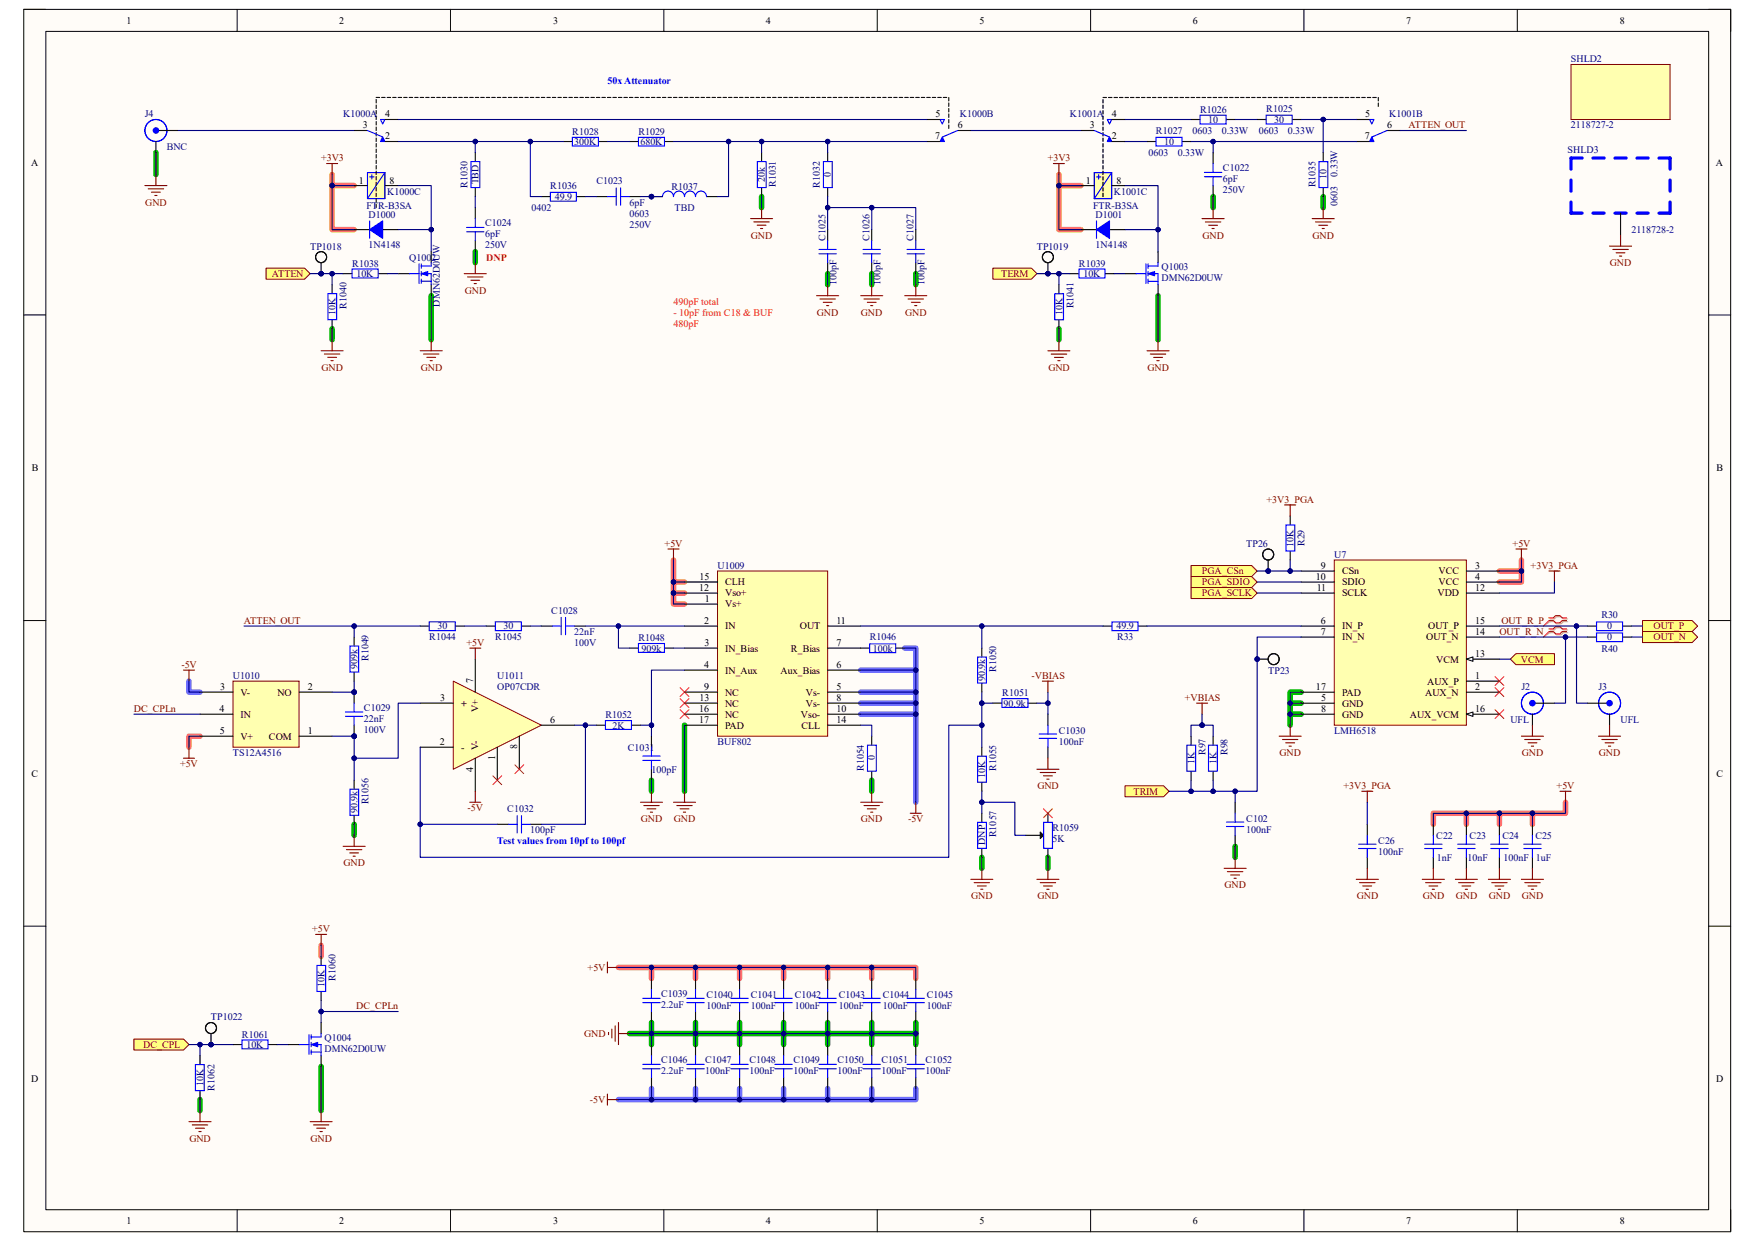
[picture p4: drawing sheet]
<svg xmlns="http://www.w3.org/2000/svg" width="297mm" height="210mm" viewBox="0 0 297 210" stroke-linecap="round" stroke-linejoin="round" font-family="sans-serif">
<defs><g id="words">
<g font-size="1.7">
<text x="21.4" y="4">1</text>
<text x="57.4" y="4">2</text>
<text x="93.6" y="4">3</text>
<text x="129.6" y="4">4</text>
<text x="165.8" y="4">5</text>
<text x="201.8" y="4">6</text>
<text x="238" y="4">7</text>
<text x="274.1" y="4">8</text>
<text x="61.4" y="21.7">3</text>
<text x="65.2" y="23.6">2</text>
<text x="65.2" y="19.9">4</text>
<text x="158.3" y="23.6">7</text>
<text x="158.3" y="19.9">5</text>
<text x="162.1" y="21.7">6</text>
<text x="184.4" y="21.7">3</text>
<text x="188.2" y="23.6">2</text>
<text x="188.2" y="19.9">4</text>
<text x="231" y="23.6">7</text>
<text x="231" y="19.9">5</text>
<text x="234.8" y="21.7">6</text>
<text x="5.3" y="28">A</text>
<text x="290.4" y="28">A</text>
<text x="60.7" y="31.1">1</text>
<text x="65.9" y="31.1">8</text>
<text x="183.8" y="31.1">1</text>
<text x="188.9" y="31.1">8</text>
<text x="5.4" y="79.8">B</text>
<text x="290.5" y="79.8">B</text>
<text x="118.3" y="100">12</text>
<text x="118.4" y="98.1">15</text>
<text x="119.3" y="101.9">1</text>
<text x="122.7" y="100.9">Vso+</text>
<text x="122.7" y="99.1">CLH</text>
<text x="222.7" y="98.1">10</text>
<text x="222.8" y="100">11</text>
<text x="223.5" y="96.3">9</text>
<text x="227.1" y="97.2">CSn</text>
<text x="227.1" y="99.1">SDIO</text>
<text x="227.1" y="100.9">SCLK</text>
<text x="243.3" y="100.9">VDD</text>
<text x="243.5" y="97.2">VCC</text>
<text x="243.5" y="99.1">VCC</text>
<text x="249.6" y="100">12</text>
<text x="249.6" y="96.3">3</text>
<text x="249.6" y="98.1">4</text>
<text x="119.2" y="105.6">2</text>
<text x="122.7" y="102.8">Vs+</text>
<text x="122.7" y="106.5">IN</text>
<text x="135.3" y="106.5">OUT</text>
<text x="141.6" y="105.6">11</text>
<text x="223.5" y="105.6">6</text>
<text x="223.5" y="107.4">7</text>
<text x="227.1" y="106.5">IN_P</text>
<text x="241.7" y="106.5">OUT_P</text>
<text x="249.6" y="107.4">14</text>
<text x="249.6" y="105.6">15</text>
<text x="119.2" y="113.1">4</text>
<text x="119.3" y="109.3">3</text>
<text x="122.7" y="110.3">IN_Bias</text>
<text x="133.9" y="110.3">R_Bias</text>
<text x="141.6" y="113.1">6</text>
<text x="141.6" y="109.3">7</text>
<text x="227.1" y="108.4">IN_N</text>
<text x="241.4" y="108.4">OUT_N</text>
<text x="243.1" y="112.1">VCM</text>
<text x="249.6" y="111.2">13</text>
<text x="37.3" y="116.8">3</text>
<text x="40.7" y="117.7">V-</text>
<text x="46.9" y="117.7">NO</text>
<text x="52.1" y="116.8">2</text>
<text x="74.5" y="118.7">3</text>
<text x="78" y="119.6">+</text>
<text x="80.1" y="115.7" transform="rotate(-90 80.1 115.7)">7</text>
<text x="118.4" y="118.7">13</text>
<text x="119.2" y="116.8">9</text>
<text x="122.7" y="114">IN_Aux</text>
<text x="122.7" y="117.7">NC</text>
<text x="122.7" y="119.6">NC</text>
<text x="132.1" y="114">Aux_Bias</text>
<text x="136.4" y="117.7">Vs-</text>
<text x="136.4" y="119.6">Vs-</text>
<text x="141.6" y="116.8">5</text>
<text x="141.6" y="118.7">8</text>
<text x="222.7" y="116.8">17</text>
<text x="223.6" y="118.7">5</text>
<text x="227.1" y="119.6">GND</text>
<text x="227.1" y="117.7">PAD</text>
<text x="241.2" y="117.7">AUX_N</text>
<text x="241.5" y="115.9">AUX_P</text>
<text x="249.6" y="114.9">1</text>
<text x="249.6" y="116.8">2</text>
<text x="37.2" y="120.5">4</text>
<text x="37.2" y="124.2">5</text>
<text x="40.7" y="125.2">V+</text>
<text x="40.7" y="121.5">IN</text>
<text x="45.5" y="125.2">COM</text>
<text x="52.1" y="124.2">1</text>
<text x="81" y="120.6" transform="rotate(-90 81 120.6)">V+</text>
<text x="93.1" y="122.4">6</text>
<text x="118.3" y="120.5">16</text>
<text x="118.3" y="122.4">17</text>
<text x="122.7" y="121.5">NC</text>
<text x="122.7" y="123.3">PAD</text>
<text x="135.6" y="121.5">Vso-</text>
<text x="135.6" y="123.3">CLL</text>
<text x="141.6" y="120.5">10</text>
<text x="141.6" y="122.4">14</text>
<text x="223.6" y="120.5">8</text>
<text x="227.1" y="121.5">GND</text>
<text x="238.6" y="121.5">AUX_VCM</text>
<text x="249.6" y="120.5">16</text>
<text x="5.3" y="131.4">C</text>
<text x="74.4" y="126.1">2</text>
<text x="78" y="127">-</text>
<text x="80.1" y="130.6" transform="rotate(-90 80.1 130.6)">4</text>
<text x="81" y="127" transform="rotate(-90 81 127)">V-</text>
<text x="83.8" y="128.6" transform="rotate(-90 83.8 128.6)">1</text>
<text x="87.5" y="126.8" transform="rotate(-90 87.5 126.8)">8</text>
<text x="290.5" y="131.4">C</text>
<text x="5.3" y="183.2">D</text>
<text x="290.4" y="183.2">D</text>
<text x="21.4" y="207.2">1</text>
<text x="57.4" y="207.2">2</text>
<text x="93.6" y="207.2">3</text>
<text x="129.6" y="207.2">4</text>
<text x="165.8" y="207.2">5</text>
<text x="201.8" y="207.2">6</text>
<text x="238" y="207.2">7</text>
<text x="274.1" y="207.2">8</text>
</g>
<g font-size="1.7" fill="#000080">
<text x="265.9" y="10.5">SHLD2</text>
<text x="24.5" y="19.9">J4</text>
<text x="58.1" y="19.9">K1000A</text>
<text x="96.9" y="22.9">R1028</text>
<text x="108" y="22.9">R1029</text>
<text x="162.4" y="19.9">K1000B</text>
<text x="181.1" y="19.9">K1001A</text>
<text x="195.6" y="22.6">R1027</text>
<text x="201.8" y="22.6">0603</text>
<text x="203.1" y="19.1">R1026</text>
<text x="204.5" y="20.8">10</text>
<text x="206.8" y="22.6">0.33W</text>
<text x="213" y="22.6">0603</text>
<text x="214.3" y="18.9">R1025</text>
<text x="215.6" y="20.8">30</text>
<text x="217.9" y="22.6">0.33W</text>
<text x="235.1" y="19.9">K1001B</text>
<text x="265.9" y="21.7">2118727-2</text>
<text x="28.2" y="25.4">BNC</text>
<text x="97.2" y="24.5">300K</text>
<text x="108.4" y="24.5">680K</text>
<text x="140.6" y="29.9" transform="rotate(-90 140.6 29.9)">0</text>
<text x="194.4" y="26.4">0603</text>
<text x="197" y="24.5">10</text>
<text x="199.3" y="26.4">0.33W</text>
<text x="207" y="29">C1022</text>
<text x="226.4" y="29.9" transform="rotate(-90 226.4 29.9)">0.33W</text>
<text x="265.3" y="25.8">SHLD3</text>
<text x="62" y="35.3">FTR-B3SA</text>
<text x="65.5" y="32.9">K1000C</text>
<text x="79.1" y="31.7" transform="rotate(-90 79.1 31.7)">R1030</text>
<text x="81" y="31.2" transform="rotate(-90 81 31.2)">TBD</text>
<text x="90" y="35.7">0402</text>
<text x="93.1" y="32">R1036</text>
<text x="93.9" y="33.9">49.9</text>
<text x="100.9" y="31.1">C1023</text>
<text x="106.5" y="34.8">6pF</text>
<text x="113.6" y="32.2">R1037</text>
<text x="114.2" y="35.7">TBD</text>
<text x="129.5" y="30.8" transform="rotate(-90 129.5 30.8)">20k</text>
<text x="131.3" y="31.7" transform="rotate(-90 131.3 31.7)">R1031</text>
<text x="138.8" y="31.7" transform="rotate(-90 138.8 31.7)">R1032</text>
<text x="185" y="35.3">FTR-B3SA</text>
<text x="188.5" y="32.9">K1001C</text>
<text x="207" y="32.7">250V</text>
<text x="207" y="30.9">6pF</text>
<text x="222.6" y="31.7" transform="rotate(-90 222.6 31.7)">R1035</text>
<text x="224.5" y="30.4" transform="rotate(-90 224.5 30.4)">10</text>
<text x="226.4" y="34.9" transform="rotate(-90 226.4 34.9)">0603</text>
<text x="62.4" y="36.9">D1000</text>
<text x="82.1" y="38.3">C1024</text>
<text x="82.1" y="40.2">6pF</text>
<text x="106.5" y="36.7">0603</text>
<text x="106.5" y="38.5">250V</text>
<text x="139.7" y="40.7" transform="rotate(-90 139.7 40.7)">C1025</text>
<text x="147.1" y="40.7" transform="rotate(-90 147.1 40.7)">C1026</text>
<text x="154.6" y="40.7" transform="rotate(-90 154.6 40.7)">C1027</text>
<text x="185.4" y="36.9">D1001</text>
<text x="276.1" y="39.5">2118728-2</text>
<text x="52.5" y="42.2">TP1018</text>
<text x="59.6" y="45.2">R1038</text>
<text x="60.3" y="46.9">10K</text>
<text x="62.4" y="42">1N4148</text>
<text x="69.3" y="44.1">Q1002</text>
<text x="82.1" y="42">250V</text>
<text x="175.5" y="42.2">TP1019</text>
<text x="182.6" y="45.2">R1039</text>
<text x="183.3" y="46.9">10K</text>
<text x="185.4" y="42">1N4148</text>
<text x="196.6" y="45.8">Q1003</text>
<text x="196.6" y="47.6">DMN62D0UW</text>
<text x="56.8" y="53.3" transform="rotate(-90 56.8 53.3)">10K</text>
<text x="58.6" y="52.2" transform="rotate(-90 58.6 52.2)">R1040</text>
<text x="74.5" y="51.9" transform="rotate(-90 74.5 51.9)">DMN62D0UW</text>
<text x="141.6" y="48.2" transform="rotate(-90 141.6 48.2)">100pF</text>
<text x="149" y="48.2" transform="rotate(-90 149 48.2)">100pF</text>
<text x="156.5" y="48.2" transform="rotate(-90 156.5 48.2)">100pF</text>
<text x="179.8" y="53.3" transform="rotate(-90 179.8 53.3)">10K</text>
<text x="181.6" y="52.2" transform="rotate(-90 181.6 52.2)">R1041</text>
<text x="210.9" y="92.5">TP26</text>
<text x="218.9" y="92.5" transform="rotate(-90 218.9 92.5)">10K</text>
<text x="220.8" y="92.4" transform="rotate(-90 220.8 92.4)">R29</text>
<text x="225.8" y="94.4">U7</text>
<text x="121.4" y="96.3">U1009</text>
<text x="74" y="106.5">30</text>
<text x="85.2" y="106.5">30</text>
<text x="93.3" y="103.9">C1028</text>
<text x="97.2" y="107.4">22nF</text>
<text x="188.9" y="106.5">49.9</text>
<text x="271" y="104.6">R30</text>
<text x="272" y="106.5">0</text>
<text x="60.5" y="113.2" transform="rotate(-90 60.5 113.2)">909k</text>
<text x="62.4" y="111.9" transform="rotate(-90 62.4 111.9)">R1049</text>
<text x="72.6" y="108.4">R1044</text>
<text x="83.8" y="108.4">R1045</text>
<text x="97.2" y="109.3">100V</text>
<text x="108" y="108.5">R1048</text>
<text x="108.5" y="110.3">909k</text>
<text x="147.2" y="108.4">R1046</text>
<text x="147.7" y="110.3">100k</text>
<text x="168.6" y="113.7" transform="rotate(-90 168.6 113.7)">R1050</text>
<text x="189.1" y="108.4">R33</text>
<text x="271" y="110.3">R40</text>
<text x="272" y="108.4">0</text>
<text x="39.4" y="114.9">U1010</text>
<text x="84.2" y="114.9">U1011</text>
<text x="84.2" y="116.8">OP07CDR</text>
<text x="166.7" y="115.3" transform="rotate(-90 166.7 115.3)">90.9k</text>
<text x="169.6" y="117.7">R1051</text>
<text x="169.8" y="119.6">90.9k</text>
<text x="214.6" y="114">TP23</text>
<text x="257.5" y="116.8">J2</text>
<text x="270.5" y="116.8">J3</text>
<text x="61.6" y="124">100V</text>
<text x="61.6" y="120.3">C1029</text>
<text x="61.6" y="122.2">22nF</text>
<text x="102.4" y="121.6">R1052</text>
<text x="103.6" y="123.3">2K</text>
<text x="179.2" y="124.2">C1030</text>
<text x="225.8" y="124.2">LMH6518</text>
<text x="255.6" y="122.4">UFL</text>
<text x="274.2" y="122.4">UFL</text>
<text x="39.4" y="128">TS12A4516</text>
<text x="106.3" y="127">C1031</text>
<text x="110.2" y="130.8">100pF</text>
<text x="121.4" y="126.1">BUF802</text>
<text x="146.2" y="130.5" transform="rotate(-90 146.2 130.5)">R1054</text>
<text x="148.1" y="128.7" transform="rotate(-90 148.1 128.7)">0</text>
<text x="166.7" y="131.6" transform="rotate(-90 166.7 131.6)">10K</text>
<text x="168.6" y="130.5" transform="rotate(-90 168.6 130.5)">R1055</text>
<text x="179.2" y="126.1">100nF</text>
<text x="202.1" y="129.3" transform="rotate(-90 202.1 129.3)">1K</text>
<text x="204" y="127.8" transform="rotate(-90 204 127.8)">R97</text>
<text x="205.9" y="129.3" transform="rotate(-90 205.9 129.3)">1K</text>
<text x="207.7" y="127.8" transform="rotate(-90 207.7 127.8)">R98</text>
<text x="60.5" y="137.7" transform="rotate(-90 60.5 137.7)">90.9k</text>
<text x="62.4" y="136.1" transform="rotate(-90 62.4 136.1)">R1056</text>
<text x="85.9" y="137.5">C1032</text>
<text x="89.7" y="141">100pF</text>
<text x="166.7" y="143" transform="rotate(-90 166.7 143)">DNP</text>
<text x="168.6" y="141.7" transform="rotate(-90 168.6 141.7)">R1057</text>
<text x="178.1" y="140.7">R1059</text>
<text x="178.1" y="142.5">5K</text>
<text x="210.9" y="139.1">C102</text>
<text x="210.9" y="141">100nF</text>
<text x="233.3" y="142.9">C26</text>
<text x="243.1" y="141.9">C22</text>
<text x="248.7" y="141.9">C23</text>
<text x="254.3" y="141.9">C24</text>
<text x="259.8" y="141.9">C25</text>
<text x="233.3" y="144.7">100nF</text>
<text x="243.2" y="145.7">1nF</text>
<text x="248.3" y="145.7">10nF</text>
<text x="254.4" y="145.7">100nF 1uF</text>
<text x="54.9" y="167" transform="rotate(-90 54.9 167)">10K</text>
<text x="56.8" y="165.9" transform="rotate(-90 56.8 165.9)">R1060</text>
<text x="35.7" y="172.7">TP1022</text>
<text x="111.9" y="168.8">C1039</text>
<text x="111.9" y="170.6">2.2uF</text>
<text x="119.5" y="169">C1040</text>
<text x="119.5" y="170.8">100nF</text>
<text x="127" y="169">C1041</text>
<text x="127" y="170.8">100nF</text>
<text x="134.5" y="169">C1042</text>
<text x="134.5" y="170.8">100nF</text>
<text x="141.9" y="169">C1043</text>
<text x="141.9" y="170.8">100nF</text>
<text x="149.4" y="169">C1044</text>
<text x="149.4" y="170.8">100nF</text>
<text x="156.8" y="169">C1045</text>
<text x="156.8" y="170.8">100nF</text>
<text x="40.9" y="175.6">R1061</text>
<text x="41.7" y="177.3">10K</text>
<text x="54.9" y="176.2">Q1004</text>
<text x="54.9" y="178.1">DMN62D0UW</text>
<text x="111.9" y="180">C1046</text>
<text x="119.3" y="180">C1047</text>
<text x="126.8" y="180">C1048</text>
<text x="134.3" y="180">C1049</text>
<text x="141.7" y="180">C1050</text>
<text x="149.2" y="180">C1051</text>
<text x="156.6" y="180">C1052</text>
<text x="34.4" y="183.8" transform="rotate(-90 34.4 183.8)">10K</text>
<text x="36.3" y="184.6" transform="rotate(-90 36.3 184.6)">R1062</text>
<text x="111.9" y="181.8">2.2uF</text>
<text x="119.3" y="181.8">100nF</text>
<text x="126.8" y="181.8">100nF</text>
<text x="134.3" y="181.8">100nF</text>
<text x="141.7" y="181.8">100nF</text>
<text x="149.2" y="181.8">100nF</text>
<text x="156.6" y="181.8">100nF</text>
</g>
<g font-size="1.7" fill="#00f">
<text x="102.8" y="14.3">50x Attenuator</text>
<text x="84.2" y="142.9">Test values from 10pf to 100pf</text>
</g>
<g font-size="1.7" fill="#800000">
<text x="238.4" y="21.7">ATTEN_OUT</text>
<text x="54.4" y="27.3">+3V3</text>
<text x="177.3" y="27.3">+3V3</text>
<text x="24.6" y="34.8">GND</text>
<text x="127.1" y="40.4">GND</text>
<text x="203.5" y="40.4">GND</text>
<text x="222.1" y="40.4">GND</text>
<text x="46" y="46.9">ATTEN</text>
<text x="169.4" y="46.9">TERM</text>
<text x="272.5" y="45">GND</text>
<text x="78.7" y="49.7">GND</text>
<text x="138.3" y="53.4">GND</text>
<text x="145.7" y="53.4">GND</text>
<text x="153.2" y="53.4">GND</text>
<text x="54.4" y="62.7">GND</text>
<text x="71.2" y="62.7">GND</text>
<text x="177.4" y="62.7">GND</text>
<text x="194.2" y="62.7">GND</text>
<text x="214.3" y="85.1">+3V3_PGA</text>
<text x="112.5" y="92.5">+5V</text>
<text x="256" y="92.5">+5V</text>
<text x="203.4" y="97.2">PGA_CSn</text>
<text x="203.4" y="100.9">PGA_SCLK</text>
<text x="203.4" y="99.1">PGA_SDIO</text>
<text x="259" y="96.3">+3V3_PGA</text>
<text x="41.3" y="105.6">ATTEN_OUT</text>
<text x="253.7" y="107.4">OUT_R_N</text>
<text x="254.1" y="105.6">OUT_R_P</text>
<text x="279.8" y="106.5">OUT_P</text>
<text x="30.7" y="113.1">-5V</text>
<text x="79" y="109.3">+5V</text>
<text x="257.4" y="112.1">VCM</text>
<text x="279.8" y="108.4">OUT_N</text>
<text x="174.6" y="114.9">-VBIAS</text>
<text x="200.5" y="118.7">+VBIAS</text>
<text x="22.6" y="120.5">DC_CPLn</text>
<text x="30.5" y="129.8">+5V</text>
<text x="216.5" y="128">GND</text>
<text x="257.6" y="128">GND</text>
<text x="270.6" y="128">GND</text>
<text x="79.1" y="137.3">-5V</text>
<text x="175.6" y="133.6">GND</text>
<text x="191.8" y="134.5">TRIM</text>
<text x="227.4" y="133.6">+3V3_PGA</text>
<text x="263.4" y="133.6">+5V</text>
<text x="108.5" y="139.1">GND</text>
<text x="114" y="139.1">GND</text>
<text x="145.7" y="139.1">GND</text>
<text x="153.7" y="139.1">-5V</text>
<text x="58.1" y="146.6">GND</text>
<text x="164.4" y="152.2">GND</text>
<text x="175.6" y="152.2">GND</text>
<text x="207.2" y="150.3">GND</text>
<text x="229.6" y="152.2">GND</text>
<text x="240.8" y="152.2">GND</text>
<text x="246.4" y="152.2">GND</text>
<text x="252" y="152.2">GND</text>
<text x="257.6" y="152.2">GND</text>
<text x="52.8" y="157.8">+5V</text>
<text x="99.4" y="164.3">+5V</text>
<text x="60.3" y="170.8">DC_CPLn</text>
<text x="24.2" y="177.3">DC_CPL</text>
<text x="98.8" y="175.5">GND</text>
<text x="99.8" y="186.6">-5V</text>
<text x="32" y="193.2">GND</text>
<text x="52.5" y="193.2">GND</text>
</g>
<g font-size="1.7" fill="#f00">
<text x="82.3" y="44.1">DNP</text>
<text x="114" y="51.6">490pF total</text>
<text x="114" y="53.4">- 10pF from C18 &amp; BUF</text>
<text x="114" y="55.3">480pF</text>
</g>
</g></defs>
<path d="M4 1.6h288.9v206.8h-288.9z" fill-rule="evenodd" fill="#fffcf8"/>
<path d="M4 1.6h288.9v206.8h-288.9z" fill="none" stroke="#000" stroke-width=".17"/>
<path d="M7.8 5.3h281.4v199.4h-281.4z" fill-rule="evenodd" fill="#fffcf8"/>
<g fill="none" stroke="#000" stroke-width=".17">
<path d="M4 1.6h3.7M7.8 5.3h281.4v199.4h-281.4zM40.1 1.6v3.7M76.2 1.6v3.7M112.3 1.6v3.7M148.5 1.6v3.7M184.6 1.6v3.7M220.7 1.6v3.7M256.8 1.6v3.7M289.2 1.6h3.7v3.7M4 53.3h3.7M289.2 53.3h3.7"/>
<path d="M4 105h3.8M289.2 105h3.7M4 156.7h3.8M289.2 156.7h3.7M40.1 204.7v3.7M76.2 204.7v3.7M112.4 204.7v3.7M148.5 204.7v3.7M184.6 204.7v3.7M220.7 204.7v3.7M256.8 204.7v3.7M292.9 204.7v3.7"/>
</g>
<g fill="none" stroke="#00be00" stroke-width=".93">
<path d="M26.4 25.8v3.7M128.9 33.3v1.8M205.3 33.3v1.8M223.9 33.3v1.8M56.2 55.6v1.9M73 50v7.5M80.4 42.6v1.8M140.1 46.3v1.9M147.5 46.3v1.9M155 46.3v1.9M179.2 55.6v1.9M196 50v7.5"/>
<path d="M218.3 119h1.9M220.2 117.1h-1.9v3.8h1.9M59.9 139.5v1.9M110.3 132v1.9M115.8 122.7v11.2M147.5 132v1.9M218.3 120.9v1.8M166.2 145.1v1.8M177.3 145.1v1.8M209 143.2v1.9M110.3 173v3.8M117.7 173v3.8"/>
<path d="M125.2 173v3.8M132.6 173v3.8M140.1 173v3.8M147.5 173v3.8M155 173v1.9h-48.5M155 174.9v1.9M33.8 186.1v1.8M54.3 180.5v7.4"/>
</g>
<g fill="none" stroke="#ff6e6e" stroke-width=".93">
<path d="M114 94.8v7.4h1.8M114 98.5h1.8M253.8 96.6h3.7M257.5 94.8v3.7h-3.7M114 100.4h1.8M33.8 124.6h-1.8v1.8M248.2 137.6h-5.6v1.9M253.8 137.6h-5.6v1.9M259.3 137.6v1.9M264.9 135.8v1.8h-11.1v1.9M54.3 160v1.9M104.7 163.7h13v1.9"/>
<path d="M110.3 163.7v1.9M117.7 163.7h29.8v1.9M125.2 163.7v1.9M132.6 163.7v1.9M140.1 163.7v1.9M147.5 163.7h7.5v1.9"/>
</g>
<path d="M56.2 31.4v7.5h3.7M56.2 29.5v1.9h3.7M179.2 31.4v7.5h3.7M179.2 29.5v1.9h3.7" fill="none" stroke="#f90" stroke-width=".93"/>
<g fill="none" stroke="#6e6eff" stroke-width=".93">
<path d="M32 115.3v1.8h1.8M145.7 113.4h9.3v3.7h-9.3M145.7 119h9.3v1.9h-9.3M153.1 109.7h1.9v3.7M155 117.1v1.9M155 120.9v14.9M110.3 184.2v1.9M117.7 184.2v1.9M125.2 184.2v1.9M132.6 184.2v1.9M140.1 184.2v1.9M147.5 184.2v1.9h-42.8"/>
<path d="M155 184.2v1.9h-7.5"/>
</g>
<path d="M265.9 30.5v1.8M265.9 34.2v1.9h1.8M267.7 26.7h-1.8v1.9M269.6 36.1h1.9M269.6 26.7h1.9M273.3 36.1h1.9M273.3 26.7h1.9M277.1 36.1h1.8M277.1 26.7h1.8M280.8 26.7h1.8v1.9M282.6 34.2v1.9h-1.8M282.6 30.5v1.8" fill="none" stroke="#00f" stroke-width=".56"/>
<path d="M274.3 36.1v3.7" fill="none" stroke="#000" stroke-width=".19"/>
<path d="M274.3 39.8v1.9M272.4 41.7h3.7M273 42.2h2.6M273.5 42.8h1.5M274.1 43.3h.3" fill="none" stroke="#800000" stroke-width=".19"/>
<path d="M265.9 10.9h16.7v9.3h-16.7z" fill-rule="evenodd" fill="#ffffb0"/>
<path d="M265.9 10.9h16.7v9.3h-16.7z" fill="none" stroke="#800000" stroke-width=".17"/>
<path d="M24.5 31.4h3.7M25.1 32h2.6M25.6 32.5h1.5M26.2 33.1h.4M26.4 29.5v1.9" fill="none" stroke="#800000" stroke-width=".19"/>
<circle cx="26.4" cy="22.1" r="1.86" fill="none" stroke="#00f" stroke-width=".19"/>
<path d="M26.4 22.1h3.7M26.4 23.9v1.9" fill="none" stroke="#000" stroke-width=".19"/>
<circle cx="26.4" cy="22.1" r=".47" fill="#00f"/>
<circle cx="26.4" cy="22.1" r=".47" fill="none" stroke="#00f" stroke-width=".17"/>
<path d="M186.7 105.9h1.4M192.6 105.9h1.5" fill="none" stroke="#000" stroke-width=".19"/>
<path d="M188.2 105.2h4.4v1.5h-4.4z" fill="none" stroke="#00f" stroke-width=".19"/>
<path d="M225.8 94.8h22.4v27.9h-22.4z" fill-rule="evenodd" fill="#ffffb0"/>
<path d="M225.8 94.8h22.4v27.9h-22.4z" fill="none" stroke="#800000" stroke-width=".17"/>
<path d="M220.2 96.6h5.6M220.2 98.5h5.6M220.2 100.4h5.6M248.2 100.4h5.6M248.2 111.5h5.6" fill="none" stroke="#000" stroke-width=".19"/>
<path d="M248.2 111.5l1.1-.3v.7z" fill="#f8fcff"/>
<path d="M248.2 111.5l1.1-.3v.7z" fill="none" stroke="#000" stroke-width=".17"/>
<path d="M248.2 107.8h5.6M248.2 105.9h5.6M248.2 115.3h5.6M248.2 117.1h5.6M248.2 120.9h5.6" fill="none" stroke="#000" stroke-width=".19"/>
<path d="M248.2 120.9l1.1-.4v.7z" fill="#f8fcff"/>
<path d="M248.2 120.9l1.1-.4v.7z" fill="none" stroke="#000" stroke-width=".17"/>
<path d="M248.2 96.6h5.6M248.2 98.5h5.6M220.2 119h5.6M220.2 117.1h5.6M220.2 105.9h5.6M220.2 107.8h5.6M220.2 120.9h5.6" fill="none" stroke="#000" stroke-width=".19"/>
<path d="M201.6 95.7h10.2l1 .9-1 1h-10.2z" fill-rule="evenodd" fill="#ffff80"/>
<path d="M201.6 95.7h10.2l1 .9-1 1h-10.2z" fill="none" stroke="#800000" stroke-width=".17"/>
<path d="M218.3 87.3v1.5M218.3 93.3v1.5" fill="none" stroke="#000" stroke-width=".19"/>
<path d="M217.6 88.8h1.5v4.4h-1.5z" fill="none" stroke="#00f" stroke-width=".19"/>
<path d="M201.6 99.4h10.2l1 1-1 .9h-10.2z" fill-rule="evenodd" fill="#ffff80"/>
<path d="M201.6 99.4h10.2l1 1-1 .9h-10.2z" fill="none" stroke="#800000" stroke-width=".17"/>
<path d="M201.6 97.6h10.2l1 .9-1 .9h-10.2z" fill-rule="evenodd" fill="#ffff80"/>
<path d="M201.6 97.6h10.2l1 .9-1 .9h-10.2z" fill="none" stroke="#800000" stroke-width=".17"/>
<path d="M216.5 124.6h3.7M217 125.1h2.6M217.6 125.7h1.5M218.2 126.3h.3M218.3 122.7v1.9" fill="none" stroke="#800000" stroke-width=".19"/>
<path d="M255.6 111.5l1-.9h6.5v1.9h-6.5z" fill-rule="evenodd" fill="#ffff80"/>
<path d="M255.6 111.5l1-.9h6.5v1.9h-6.5z" fill="none" stroke="#800000" stroke-width=".17"/>
<path d="M253 114.5l1.5 1.5M253 116.4l1.5 1.5M254.5 114.5l-1.5 1.5M254.5 116.4l-1.5 1.5M253 120.1l1.5 1.5M254.5 120.1l-1.5 1.5" fill="none" stroke="#f00" stroke-width=".17"/>
<path d="M278 105h8.4l.9 .9-.9 1h-8.4z" fill-rule="evenodd" fill="#ffff80"/>
<path d="M278 105h8.4l.9 .9-.9 1h-8.4z" fill="none" stroke="#800000" stroke-width=".17"/>
<path d="M278 106.9h8.4l.9 .9-.9 .9h-8.4z" fill-rule="evenodd" fill="#ffff80"/>
<path d="M278 106.9h8.4l.9 .9-.9 .9h-8.4z" fill="none" stroke="#800000" stroke-width=".17"/>
<path d="M259.3 119h3.8M268.7 105.9h1.4M268.7 107.8h1.4M274.6 105.9h1.5M274.6 107.8h1.5M259.3 120.9v1.8" fill="none" stroke="#000" stroke-width=".19"/>
<g fill="none" stroke="#00f" stroke-width=".19">
<path d="M270.2 105.2h4.4v1.5h-4.4zM270.2 107.1h4.4v1.5h-4.4z"/>
<circle cx="259.3" cy="119" r="1.86"/>
</g>
<circle cx="259.3" cy="119" r=".47" fill="#00f"/>
<circle cx="259.3" cy="119" r=".47" fill="none" stroke="#00f" stroke-width=".17"/>
<path d="M257.5 124.6h3.7M258 125.1h2.7M258.6 125.7h1.5M259.2 126.3h.3M259.3 122.7v1.9" fill="none" stroke="#800000" stroke-width=".19"/>
<circle cx="272.4" cy="119" r="1.86" fill="none" stroke="#00f" stroke-width=".19"/>
<path d="M268.7 119h3.7M272.4 120.9v1.8" fill="none" stroke="#000" stroke-width=".19"/>
<circle cx="272.4" cy="119" r=".47" fill="#00f"/>
<circle cx="272.4" cy="119" r=".47" fill="none" stroke="#00f" stroke-width=".17"/>
<path d="M270.5 124.6h3.8M271.1 125.1h2.6M271.6 125.7h1.5M272.2 126.3h.4M272.4 122.7v1.9" fill="none" stroke="#800000" stroke-width=".19"/>
<path d="M262.3 104.7h.8l.4-.3h.7l.4 .3h.7M262.3 105.2h.8l.4 .4h.7l.4-.4h.7" fill="none" stroke="#d0a19e" stroke-width=".19"/>
<path d="M262.3 105.2l-1.1 .7" fill="none" stroke="#d0a19e" stroke-width=".17"/>
<path d="M262.1 104.6h.8l.4-.4h.7l.4 .4h.7M262.1 105h.8l.4 .4h.7l.4-.4h.7" fill="none" stroke="#f00" stroke-width=".19"/>
<path d="M262.1 105l-.9 .9" fill="none" stroke="#f00" stroke-width=".17"/>
<circle cx="214.6" cy="96.6" r=".37" fill="#000080"/>
<circle cx="214.6" cy="96.6" r=".37" fill="none" stroke="#000080" stroke-width=".17"/>
<path d="M214.6 94.8v1.8" fill="none" stroke="#000" stroke-width=".19"/>
<circle cx="214.6" cy="96.6" r=".37" fill="#000080"/>
<circle cx="214.6" cy="96.6" r=".37" fill="none" stroke="#000080" stroke-width=".17"/>
<g fill="none" stroke="#000" stroke-width=".19">
<path d="M201.6 124.6v1.5M201.6 130.6v1.4M205.3 124.6v1.5M205.3 130.6v1.4M231.4 139.5v1.9M242.6 139.5v1.9M248.2 139.5v1.9M253.8 139.5v1.9M259.3 139.5v1.9M231.4 145.1v1.8M242.6 145.1v1.8M248.2 145.1v1.8"/>
<path d="M253.8 145.1v1.8M259.3 145.1v1.8"/>
<circle cx="214.6" cy="93.8" r=".93"/>
</g>
<g fill="none" stroke="#00f" stroke-width=".19">
<path d="M200.9 126.1h1.5v4.4h-1.5zM204.5 126.1h1.5v4.4h-1.5zM229.9 143.6h3M229.9 142.9h3M231.4 141.4v1.5M231.4 143.6v1.5M241.1 143.6h2.9M241.1 142.9h2.9M242.6 141.4v1.5M242.6 143.6v1.5M246.7 143.6h2.9M246.7 142.9h2.9"/>
<path d="M248.2 141.4v1.5M248.2 143.6v1.5M252.3 143.6h2.9M252.3 142.9h2.9M253.8 141.4v1.5M253.8 143.6v1.5M257.9 143.6h2.9M257.9 142.9h2.9M259.3 141.4v1.5M259.3 143.6v1.5"/>
</g>
<g fill="none" stroke="#800000" stroke-width=".19">
<path d="M256.6 92.9h1.8M257.5 92.9v1.9M264 133.9h1.9M264.9 133.9v1.9M229.5 148.8h3.8M230.1 149.4h2.6M230.6 149.9h1.5M231.2 150.5h.4M231.4 146.9v1.9M240.7 148.8h3.7M241.3 149.4h2.6M241.8 149.9h1.5"/>
<path d="M242.4 150.5h.4M242.6 146.9v1.9M246.3 148.8h3.7M246.9 149.4h2.6M247.4 149.9h1.5M248 150.5h.3M248.2 146.9v1.9M251.9 148.8h3.7M252.5 149.4h2.6M253 149.9h1.5M253.6 150.5h.3M253.8 146.9v1.9"/>
<path d="M257.5 148.8h3.7M258 149.4h2.7M258.6 149.9h1.5M259.2 150.5h.3M259.3 146.9v1.9"/>
</g>
<path d="M262.3 106.6h.8l.4-.4h.7l.4 .4h.7M262.3 107.1h.8l.4 .3h.7l.4-.3h.7" fill="none" stroke="#d0a19e" stroke-width=".19"/>
<path d="M262.3 107.1l-1.1 .7" fill="none" stroke="#d0a19e" stroke-width=".17"/>
<path d="M262.1 106.4h.8l.4-.4h.7l.4 .4h.7M262.1 106.9h.8l.4 .4h.7l.4-.4h.7" fill="none" stroke="#f00" stroke-width=".19"/>
<path d="M262.1 106.9l-.9 .9" fill="none" stroke="#f00" stroke-width=".17"/>
<path d="M190.4 133h6.5l.9 .9-.9 .9h-6.5z" fill-rule="evenodd" fill="#ffff80"/>
<path d="M190.4 133h6.5l.9 .9-.9 .9h-6.5z" fill="none" stroke="#800000" stroke-width=".17"/>
<path d="M202.5 119h1.9M203.4 119v1.9" fill="none" stroke="#800000" stroke-width=".19"/>
<circle cx="212.8" cy="111.5" r=".37" fill="#000080"/>
<circle cx="212.8" cy="111.5" r=".37" fill="none" stroke="#000080" stroke-width=".17"/>
<path d="M212.8 111.5h1.8" fill="none" stroke="#000" stroke-width=".19"/>
<circle cx="212.8" cy="111.5" r=".37" fill="#000080"/>
<circle cx="212.8" cy="111.5" r=".37" fill="none" stroke="#000080" stroke-width=".17"/>
<g fill="none" stroke="#000" stroke-width=".19">
<path d="M209 135.8v1.8M209 141.4v1.8"/>
<circle cx="215.6" cy="111.5" r=".93"/>
</g>
<path d="M207.6 139.1h2.9M207.6 139.9h2.9M209 137.6v1.5M209 139.9v1.5" fill="none" stroke="#00f" stroke-width=".19"/>
<path d="M217.4 85.4h1.9M218.3 85.4v1.9M262.1 96.6h1.9M263.1 96.6v1.9M230.5 133.9h1.8M231.4 133.9v1.9M207.2 146.9h3.7M207.7 147.5h2.6M208.3 148.1h1.5M208.8 148.6h.4M209 145.1v1.8" fill="none" stroke="#800000" stroke-width=".19"/>
<path d="M62.2 29.2h2.9v4.4h-2.9z" fill-rule="evenodd" fill="#ffffb0"/>
<path d="M62.2 29.2h2.9v4.4h-2.9z" fill="none" stroke="#800000" stroke-width=".17"/>
<path d="M62.6 29.9h.7M62.9 29.6v.7M65.1 29.2l-2.9 4.4M65.1 29.2h-2.9v4.4M65.1 29.2v4.4h-2.9" fill="none" stroke="#00f" stroke-width=".19"/>
<path d="M59.9 31.4h2.2M59.9 38.9h2.8M64.6 38.9h2.8M65.2 31.4h2.2" fill="none" stroke="#000" stroke-width=".19"/>
<path d="M55.3 27.7h1.8M56.2 27.7v1.8" fill="none" stroke="#800000" stroke-width=".19"/>
<path d="M62.6 38.9l2.2-1.5v2.9z" fill="#00f"/>
<path d="M62.6 38.9l2.2-1.5v2.9zM62.6 37.4v2.9M69.3 46.3h1.6M70.9 44.7v3.3M71.3 45h1.7M71.3 46.3h1.7v1.9M71.3 47.6h1.7M71.3 44.7v.7M71.3 45.9v.8M71.3 47.2v.8" fill="none" stroke="#00f" stroke-width=".19"/>
<path d="M67.4 46.3h1.9M73 42.6v1.8M73 48.2v1.8" fill="none" stroke="#000" stroke-width=".19"/>
<path d="M71.3 46.3l1.1-.4v.8z" fill="#00f"/>
<path d="M71.3 46.3l1.1-.4v.8z" fill="none" stroke="#00f" stroke-width=".17"/>
<path d="M55.5 49.7h1.5v4.4h-1.5zM73 44.4v.6" fill="none" stroke="#00f" stroke-width=".19"/>
<path d="M54.3 59.4h3.8M54.9 59.9h2.6M56.2 57.5v1.9M71.1 59.4h3.7M71.7 59.9h2.6M73 57.5v1.9M55.5 60.5h1.5M56 61h.4M72.2 60.5h1.5M72.8 61h.4" fill="none" stroke="#800000" stroke-width=".19"/>
<path d="M56.2 48.2v1.4M56.2 54.2v1.4" fill="none" stroke="#000" stroke-width=".19"/>
<path d="M45 45.4h6.5l1 .9-1 .9h-6.5z" fill-rule="evenodd" fill="#ffff80"/>
<path d="M45 45.4h6.5l1 .9-1 .9h-6.5z" fill="none" stroke="#800000" stroke-width=".17"/>
<g fill="none" stroke="#000" stroke-width=".19">
<path d="M63.7 16.8v.6M63.7 17.8v.6M63.7 18.7v.6M63.7 19.6v.6M63.7 16.5h.5M64.6 16.5h.6M65.5 16.5h.6M66.5 16.5h.5M67.4 16.5h.6M68.3 16.5h.6M69.3 16.5h.5M70.2 16.5h.6"/>
<path d="M71.1 16.5h.6M72 16.5h.6M73 16.5h.6M73.9 16.5h.6M74.8 16.5h.6M75.8 16.5h.6M76.7 16.5h.6M77.6 16.5h.6M78.6 16.5h.6M79.5 16.5h.6M80.4 16.5h.6M81.4 16.5h.5"/>
<path d="M82.3 16.5h.6M83.2 16.5h.6M84.2 16.5h.5M85.1 16.5h.6M86 16.5h.6M87 16.5h.5M87.9 16.5h.6M88.8 16.5h.6M89.8 16.5h.5M90.7 16.5h.6M91.6 16.5h.6M92.5 16.5h.6"/>
<path d="M93.5 16.5h.6M94.4 16.5h.6M95.3 16.5h.6M96.3 16.5h.6M97.2 16.5h.6M98.1 16.5h.6M99.1 16.5h.6M100 16.5h.6M100.9 16.5h.6M101.9 16.5h.5M102.8 16.5h.6M103.7 16.5h.6"/>
<path d="M104.7 16.5h.5M105.6 16.5h.6M106.5 16.5h.6M107.5 16.5h.5M108.4 16.5h.6M109.3 16.5h.6M110.3 16.5h.5M111.2 16.5h.6M112.1 16.5h.6M113 16.5h.6M114 16.5h.6M114.9 16.5h.6"/>
<path d="M115.8 16.5h.6M116.8 16.5h.6M117.7 16.5h.6M118.6 16.5h.6M119.6 16.5h.6M120.5 16.5h.6M121.4 16.5h.6M122.4 16.5h.5M123.3 16.5h.6M124.2 16.5h.6M125.2 16.5h.5M126.1 16.5h.6"/>
<path d="M127 16.5h.6M128 16.5h.5M128.9 16.5h.6M129.8 16.5h.6M130.8 16.5h.5M131.7 16.5h.6M132.6 16.5h.6M133.5 16.5h.6M134.5 16.5h.6M135.4 16.5h.6M136.3 16.5h.6M137.3 16.5h.6"/>
<path d="M138.2 16.5h.6M139.1 16.5h.6M140.1 16.5h.6M141 16.5h.6M141.9 16.5h.6M142.9 16.5h.5M143.8 16.5h.6M144.7 16.5h.6M145.7 16.5h.5M146.6 16.5h.6M147.5 16.5h.6M148.5 16.5h.5"/>
<path d="M149.4 16.5h.6M150.3 16.5h.6M151.3 16.5h.5M152.2 16.5h.6M153.1 16.5h.6M154 16.5h.6M155 16.5h.6M155.9 16.5h.6M156.8 16.5h.6M157.8 16.5h.6M158.7 16.5h.6M159.6 16.5h.6"/>
<path d="M160.6 16.5v.6M160.6 17.4v.6M160.6 18.4v.5M160.6 19.3v.6M59.9 22.1h2.2M63.7 20.6v.6M63.7 21.5v.6M63.7 22.4v.6M63.7 23.4v.5M63.7 24.3v.6M63.7 25.2v.6M63.7 26.2v.5"/>
<path d="M63.7 27.1v.6M63.7 28v.6M63.7 29v.5M63.7 29.9v.6M63.7 30.8v.6M63.7 31.8v.5M63.7 32.7v.6M63.7 33.6v.6M63.7 34.5v.6M95.3 24h1.5M100.9 33.3h1.9M101.3 24h1.5"/>
<path d="M106.5 24h1.5M106.5 33.3h1.9M112.5 24h1.5M128.9 25.8v1.5M128.9 31.8v1.5M140.1 38.9v1.8M147.5 38.9v1.8M160.6 20.2v.6M160.6 21.2v.5M140.1 44.4v1.9M147.5 44.4v1.9"/>
</g>
<g fill="none" stroke="#00f" stroke-width=".19">
<path d="M62.2 22.1l2.6 1.1M96.9 23.2h4.4v1.5h-4.4zM102.8 33.3h1.5M104.3 31.8v2.9M105 33.3h1.5M105 31.8v2.9M108.1 23.2h4.4v1.5h-4.4zM128.2 27.3h1.5v4.4h-1.5zM138.6 43h2.9M138.6 42.2h2.9M140.1 40.7v1.5M140.1 43v1.4"/>
<path d="M146.1 43h2.9M146.1 42.2h2.9M147.5 40.7v1.5M147.5 43v1.4"/>
</g>
<path d="M127 37h3.8M127.6 37.6h2.6M128.1 38.1h1.5M128.7 38.7h.4M128.9 35.1v1.9M138.2 50h3.7M138.8 50.6h2.6M139.3 51.2h1.5M139.9 51.7h.4M140.1 48.2v1.8" fill="none" stroke="#800000" stroke-width=".19"/>
<path d="M64.8 23.2l.3 .7h-.7z" fill="#00f"/>
<path d="M64.4 20.2h.7l-.3 .8zM64.8 23.2l.3 .7h-.7zM159.1 20.2h.7l-.3 .8zM162.1 22.1l-2.6 1.1" fill="none" stroke="#00f" stroke-width=".19"/>
<path d="M65.2 23.9h2.2M65.2 20.2h2.2M162.1 22.1h2.2" fill="none" stroke="#000" stroke-width=".19"/>
<path d="M159.5 23.2l.3 .8h-.7z" fill="#00f"/>
<path d="M159.5 23.2l.3 .8h-.7zM59.6 45.5h4.4v1.5h-4.4z" fill="none" stroke="#00f" stroke-width=".19"/>
<path d="M156.8 20.2h2.2M156.8 24h2.2M58.1 46.3h1.4M64.1 46.3h1.4" fill="none" stroke="#000" stroke-width=".19"/>
<circle cx="54.3" cy="46.3" r=".37" fill="#000080"/>
<circle cx="54.3" cy="46.3" r=".37" fill="none" stroke="#000080" stroke-width=".17"/>
<path d="M54.3 44.4v1.9" fill="none" stroke="#000" stroke-width=".19"/>
<circle cx="54.3" cy="46.3" r=".37" fill="#000080"/>
<circle cx="54.3" cy="46.3" r=".37" fill="none" stroke="#000080" stroke-width=".17"/>
<circle cx="54.3" cy="43.5" r=".93" fill="none" stroke="#000" stroke-width=".19"/>
<path d="M168 45.4h6.6l.9 .9-.9 .9h-6.6z" fill-rule="evenodd" fill="#ffff80"/>
<path d="M168 45.4h6.6l.9 .9-.9 .9h-6.6z" fill="none" stroke="#800000" stroke-width=".17"/>
<path d="M203.4 37h3.8M204 37.6h2.6M204.6 38.1h1.4M205.1 38.7h.4M205.3 35.1v1.9" fill="none" stroke="#800000" stroke-width=".19"/>
<path d="M205.3 25.8v1.9M205.3 31.4v1.9" fill="none" stroke="#000" stroke-width=".19"/>
<path d="M203.8 29.2h3M203.8 29.9h3M205.3 27.7v1.5M205.3 29.9v1.5" fill="none" stroke="#00f" stroke-width=".19"/>
<path d="M185.2 29.2h2.9v4.4h-2.9z" fill-rule="evenodd" fill="#ffffb0"/>
<path d="M185.2 29.2h2.9v4.4h-2.9z" fill="none" stroke="#800000" stroke-width=".17"/>
<path d="M185.6 29.9h.7M185.9 29.6v.7M188.1 29.2l-2.9 4.4M188.1 29.2h-2.9v4.4M188.1 29.2v4.4h-2.9" fill="none" stroke="#00f" stroke-width=".19"/>
<path d="M182.9 31.4h2.2M182.9 38.9h2.8M187.6 38.9h2.8M188.2 31.4h2.2" fill="none" stroke="#000" stroke-width=".19"/>
<path d="M178.3 27.7h1.8M179.2 27.7v1.8" fill="none" stroke="#800000" stroke-width=".19"/>
<path d="M185.6 38.9l2.2-1.5v2.9z" fill="#00f"/>
<path d="M185.6 38.9l2.2-1.5v2.9zM185.6 37.4v2.9M192.3 46.3h1.6M193.9 44.7v3.3M194.3 45h1.7M194.3 46.3h1.7v1.9M194.3 47.6h1.7M194.3 44.7v.7M194.3 46v.7M194.3 47.2v.8" fill="none" stroke="#00f" stroke-width=".19"/>
<path d="M190.4 46.3h1.9M196 42.6v1.8M196 48.2v1.8" fill="none" stroke="#000" stroke-width=".19"/>
<path d="M194.3 46.3l1.1-.3v.7z" fill="#00f"/>
<path d="M194.3 46.3l1.1-.3v.7z" fill="none" stroke="#00f" stroke-width=".17"/>
<path d="M185.2 22.1l2.6 1.1M178.5 49.7h1.5v4.4h-1.5zM196 44.4v.6" fill="none" stroke="#00f" stroke-width=".19"/>
<path d="M177.3 59.4h3.8M177.9 59.9h2.6M179.2 57.5v1.9M194.1 59.4h3.7M194.7 59.9h2.6M196 57.5v1.9M178.5 60.5h1.5M179 61h.4M195.2 60.5h1.5M195.8 61h.4" fill="none" stroke="#800000" stroke-width=".19"/>
<g fill="none" stroke="#000" stroke-width=".19">
<path d="M186.7 16.8v.6M186.7 17.8v.6M186.7 18.7v.6M186.7 19.6v.6M186.7 16.5h.6M187.6 16.5h.6M188.5 16.5h.6M189.5 16.5h.5M190.4 16.5h.6M191.3 16.5h.6M192.3 16.5h.5M193.2 16.5h.6"/>
<path d="M194.1 16.5h.6M195.1 16.5h.5M196 16.5h.6M196.9 16.5h.6M197.8 16.5h.6M198.8 16.5h.6M199.7 16.5h.6M200.6 16.5h.6M201.6 16.5h.6M202.5 16.5h.6M203.4 16.5h.6M204.4 16.5h.6"/>
<path d="M205.3 16.5h.6M206.2 16.5h.6M207.2 16.5h.6M208.1 16.5h.6M209 16.5h.6M210 16.5h.5M210.9 16.5h.6M211.8 16.5h.6M212.8 16.5h.5M213.7 16.5h.6M214.6 16.5h.6M215.6 16.5h.5"/>
<path d="M216.5 16.5h.6M217.4 16.5h.6M218.3 16.5h.6M219.3 16.5h.6M220.2 16.5h.6M221.1 16.5h.6M222.1 16.5h.6M223 16.5h.6M223.9 16.5h.6M224.9 16.5h.6M225.8 16.5h.6M226.7 16.5h.6"/>
<path d="M227.7 16.5h.6M228.6 16.5h.6M229.5 16.5h.6M230.5 16.5h.5M231.4 16.5h.6M232.3 16.5h.6M233.3 16.5v.6M233.3 17.4v.6M182.9 22.1h2.2M186.7 20.6v.6M186.7 21.5v.6M186.7 22.4v.6"/>
<path d="M186.7 23.4v.6M186.7 24.3v.6M186.7 25.2v.6M186.7 26.2v.5M186.7 27.1v.6M186.7 28v.6M186.7 29v.5M186.7 29.9v.6M186.7 30.8v.6M186.7 31.8v.5M186.7 32.7v.6M179.2 48.2v1.4"/>
<path d="M179.2 54.2v1.4"/>
</g>
<path d="M187.8 23.2l.3 .8h-.7z" fill="#00f"/>
<path d="M187.4 20.2h.7l-.3 .8zM187.8 23.2l.3 .8h-.7zM231.8 20.2h.7l-.3 .8zM234.7 22.1l-2.5 1.1" fill="none" stroke="#00f" stroke-width=".19"/>
<path d="M188.2 24h2.2M188.2 20.2h2.2M234.8 22.1h2.2" fill="none" stroke="#000" stroke-width=".19"/>
<path d="M232.2 23.2l.3 .8h-.7z" fill="#00f"/>
<path d="M232.2 23.2l.3 .8h-.7zM182.6 45.5h4.4v1.5h-4.4z" fill="none" stroke="#00f" stroke-width=".19"/>
<path d="M229.5 20.2h2.2M229.5 24h2.2M181.1 46.3h1.4M187.1 46.3h1.4" fill="none" stroke="#000" stroke-width=".19"/>
<circle cx="177.3" cy="46.3" r=".37" fill="#000080"/>
<circle cx="177.3" cy="46.3" r=".37" fill="none" stroke="#000080" stroke-width=".17"/>
<path d="M177.3 44.4v1.9" fill="none" stroke="#000" stroke-width=".19"/>
<circle cx="177.3" cy="46.3" r=".37" fill="#000080"/>
<circle cx="177.3" cy="46.3" r=".37" fill="none" stroke="#000080" stroke-width=".17"/>
<g fill="none" stroke="#000" stroke-width=".19">
<path d="M80.4 35.1v1.9M91.6 33.3h1.5M97.6 33.3h1.5M140.1 25.8v1.5M140.1 31.8v1.5M155 38.9v1.8M194.1 24h1.5M200.1 24h1.5M201.6 20.2h1.4M207.6 20.2h1.4M212.8 20.2h1.4M218.7 20.2h1.5"/>
<path d="M223.9 25.8v1.5M223.9 31.8v1.5M80.4 40.7v1.9M155 44.4v1.9"/>
<circle cx="177.3" cy="43.5" r=".93"/>
</g>
<g fill="none" stroke="#00f" stroke-width=".19">
<path d="M203.1 19.5h4.4v1.5h-4.4zM214.3 19.5h4.4v1.5h-4.4zM79 39.2h2.9M79 38.5h2.9M80.4 37v1.5M80.4 39.2v1.5M93.1 32.6h4.4v1.4h-4.4zM139.4 27.3h1.4v4.4h-1.4zM195.6 23.2h4.4v1.5h-4.4zM223.2 27.3h1.5v4.4h-1.5zM153.5 43h2.9M153.5 42.2h2.9"/>
<path d="M155 40.7v1.5M155 43v1.4"/>
</g>
<g fill="none" stroke="#800000" stroke-width=".19">
<path d="M222.1 37h3.7M222.6 37.6h2.6M223.2 38.1h1.5M223.8 38.7h.3M223.9 35.1v1.9M78.6 46.3h3.7M79.1 46.9h2.6M79.7 47.4h1.5M80.2 48h.4M80.4 44.4v1.9M145.7 50h3.7M146.2 50.6h2.6"/>
<path d="M146.8 51.2h1.5M147.3 51.7h.4M147.5 48.2v1.8M153.1 50h3.7M153.7 50.6h2.6M154.2 51.2h1.5M154.8 51.7h.4M155 48.2v1.8"/>
</g>
<circle cx="110.3" cy="33.3" r=".37" fill="#000080"/>
<circle cx="110.3" cy="33.3" r=".37" fill="none" stroke="#000080" stroke-width=".17"/>
<path d="M110.3 33.3h1.8" fill="none" stroke="#000" stroke-width=".19"/>
<circle cx="110.3" cy="33.3" r=".37" fill="#000080"/>
<circle cx="110.3" cy="33.3" r=".37" fill="none" stroke="#000080" stroke-width=".17"/>
<path d="M80.4 25.8v1.5M80.4 31.8v1.5M119.6 33.3h1.8" fill="none" stroke="#000" stroke-width=".19"/>
<path d="M79.7 27.3h1.5v4.4h-1.5zM112.1 33.3a.93 .93 0 0 1 .9-1 .93 .93 0 0 1 1 1 .93 .93 0 0 1 .9-1 .93 .93 0 0 1 .9 1 .93 .93 0 0 1 1-1 .93 .93 0 0 1 .9 1 .93 .93 0 0 1 .9-1 .93 .93 0 0 1 1 1" fill="none" stroke="#00f" stroke-width=".19"/>
<path d="M58.1 143.2h3.7M58.6 143.8h2.6M59.2 144.3h1.5M59.7 144.9h.4M59.9 141.4v1.8" fill="none" stroke="#800000" stroke-width=".19"/>
<path d="M76.7 115.3l14.9 7.4-14.9 7.5z" fill="#ffffb0"/>
<path d="M76.7 115.3l14.9 7.4-14.9 7.5z" fill="none" stroke="#800000" stroke-width=".17"/>
<g fill="none" stroke="#000" stroke-width=".19">
<path d="M59.9 107.8v1.5M59.9 113.8v1.5M71.1 119h5.6M80.4 111.5v5.6M82.3 105.9h1.5M88.3 105.9h1.5M91.6 105.9h1.9M97.2 105.9h1.9M166.2 109.7v1.4M166.2 115.7v1.4M168 119h1.5M174 119h1.5"/>
<path d="M59.9 132v1.5M59.9 138v1.5M71.1 126.4h5.6M80.4 128.3v5.6M84.2 126.4v5.6M84.2 139.5h1.8M87.9 124.6v5.6M89.8 139.5h1.8M91.6 122.7h5.6M100.9 122.7h1.5M106.9 122.7h1.5M166.2 126.4v1.5"/>
<path d="M166.2 132.4v1.5M166.2 137.6v1.5M177.3 120.9v1.8M177.3 126.4v1.9M166.2 143.6v1.5M117.7 165.6v1.8M117.7 171.2v1.8M125.2 165.6v1.8M125.2 171.2v1.8M132.6 165.6v1.8M132.6 171.2v1.8M140.1 165.6v1.8"/>
<path d="M140.1 171.2v1.8M147.5 165.6v1.8M147.5 171.2v1.8"/>
</g>
<path d="M83.4 131.3l1.5 1.5M84.9 131.3l-1.5 1.5M87.1 129.4l1.5 1.5M88.6 129.4l-1.5 1.5" fill="none" stroke="#f00" stroke-width=".17"/>
<g fill="none" stroke="#00f" stroke-width=".19">
<path d="M59.2 109.3h1.5v4.4h-1.5zM83.8 105.2h4.4v1.5h-4.4zM93.5 105.9h1.5M95 104.5v2.9M95.7 105.9h1.5M95.7 104.5v2.9M165.4 111.2h1.5v4.4h-1.5zM169.6 118.2h4.4v1.5h-4.4zM59.2 133.6h1.5v4.4h-1.5zM86 139.5h1.5M87.5 138v3M88.3 139.5h1.5"/>
<path d="M88.3 138v3M102.5 121.9h4.4v1.5h-4.4zM165.4 128h1.5v4.4h-1.5zM165.4 139.2h1.5v4.4h-1.5zM175.9 124.2h2.9M175.9 125h2.9M177.3 122.7v1.5M177.3 125v1.4M116.2 168.9h3M116.2 169.7h3M117.7 167.4v1.5M117.7 169.7v1.5"/>
<path d="M123.7 168.9h2.9M123.7 169.7h2.9M125.2 167.4v1.5M125.2 169.7v1.5M131.1 168.9h3M131.1 169.7h3M132.6 167.4v1.5M132.6 169.7v1.5M138.6 168.9h2.9M138.6 169.7h2.9M140.1 167.4v1.5M140.1 169.7v1.5"/>
<path d="M146.1 168.9h2.9M146.1 169.7h2.9M147.5 167.4v1.5M147.5 169.7v1.5"/>
</g>
<g fill="none" stroke="#800000" stroke-width=".19">
<path d="M79.5 109.7h1.9M80.4 109.7v1.8M176.4 115.3h1.9M177.3 115.3v1.8M79.5 135.8h1.9M80.4 133.9v1.9M175.5 130.2h3.7M176 130.7h2.6M176.6 131.3h1.5M177.2 131.9h.3M177.3 128.3v1.9M164.3 148.8h3.7"/>
<path d="M164.9 149.4h2.6M165.4 149.9h1.5M166 150.5h.3M166.2 146.9v1.9"/>
</g>
<path d="M121.4 96.6h18.7v28h-18.7z" fill-rule="evenodd" fill="#ffffb0"/>
<path d="M121.4 96.6h18.7v28h-18.7z" fill="none" stroke="#800000" stroke-width=".17"/>
<g fill="none" stroke="#000" stroke-width=".19">
<path d="M115.8 98.5h5.6M106.5 109.7h1.5M112.5 109.7h1.5M115.8 102.2h5.6M115.8 105.9h5.6M115.8 109.7h5.6M115.8 113.4h5.6M115.8 117.1h5.6M115.8 119h5.6M115.8 100.4h5.6M140.1 105.9h5.6M140.1 109.7h7"/>
<path d="M140.1 113.4h5.6M140.1 117.1h5.6M140.1 119h5.6M151.6 109.7h1.5M110.3 124.6v1.8M110.3 130.2v1.8M115.8 120.9h5.6M115.8 122.7h5.6M140.1 120.9h5.6M140.1 122.7h5.6M147.5 124.6v1.5M147.5 130.6v1.4"/>
<path d="M177.3 137.6v1.5M173.6 141.4h3M177.3 143.6v1.5M54.3 161.9v1.4M54.3 167.8v1.5M110.3 165.6v1.8M110.3 171.2v1.8M117.7 176.8v1.8M125.2 176.8v1.8M132.6 176.8v1.8M140.1 176.8v1.8M117.7 182.4v1.8"/>
<path d="M125.2 182.4v1.8M132.6 182.4v1.8M140.1 182.4v1.8"/>
</g>
<path d="M115.1 116.4l1.5 1.5M115.1 118.3l1.5 1.4M116.6 116.4l-1.5 1.5M116.6 118.3l-1.5 1.4M115.1 120.1l1.5 1.5M116.6 120.1l-1.5 1.5M176.6 136.9l1.5 1.5M178.1 136.9l-1.5 1.5" fill="none" stroke="#f00" stroke-width=".17"/>
<g fill="none" stroke="#800000" stroke-width=".19">
<path d="M113 92.9h1.9M114 92.9v1.9M108.4 135.8h3.7M109 136.3h2.6M109.5 136.9h1.5M110.1 137.4h.3M110.3 133.9v1.9M114 135.8h3.7M114.5 136.3h2.6M115.1 136.9h1.5M115.7 137.4h.3M115.8 133.9v1.9"/>
<path d="M145.7 135.8h3.7M146.2 136.3h2.6M146.8 136.9h1.5M147.3 137.4h.4M147.5 133.9v1.9M154 137.6h1.9M155 135.8v1.8M175.5 148.8h3.7M176 149.4h2.6M176.6 149.9h1.5M177.2 150.5h.3M177.3 146.9v1.9"/>
<path d="M102.8 162.8v1.9M102.8 163.7h1.9M103 174.7v.4M103.5 174.2v1.5M104.1 173.6v2.6M104.7 173v3.8M104.7 174.9h1.8M102.8 185.2v1.8M102.8 186.1h1.9"/>
</g>
<g fill="none" stroke="#00f" stroke-width=".19">
<path d="M108.1 108.9h4.4v1.5h-4.4zM147.2 109h4.4v1.5h-4.4zM108.8 128.7h2.9M108.8 127.9h2.9M110.3 126.4v1.5M110.3 128.7v1.5M146.8 126.1h1.5v4.4h-1.5zM176.6 139.2h1.5v4.4h-1.5zM53.6 163.4h1.5v4.4h-1.5zM108.8 169.7h2.9M108.8 168.9h2.9M110.3 167.4v1.5"/>
<path d="M110.3 169.7v1.5M117.7 178.6v1.5M125.2 178.6v1.5M132.6 178.6v1.5M140.1 178.6v1.5M116.2 180.9h3M116.2 180.1h3M117.7 180.9v1.5M123.7 180.9h2.9M123.7 180.1h2.9M125.2 180.9v1.5M131.1 180.9h3"/>
<path d="M131.1 180.1h3M132.6 180.9v1.5M138.6 180.9h2.9M138.6 180.1h2.9M140.1 180.9v1.5"/>
</g>
<path d="M176 140.8l.6 .6-.6 .5z" fill="#000"/>
<path d="M176 140.8l.6 .6-.6 .5z" fill="none" stroke="#000" stroke-width=".17"/>
<circle cx="35.7" cy="176.8" r=".37" fill="#000080"/>
<circle cx="35.7" cy="176.8" r=".37" fill="none" stroke="#000080" stroke-width=".17"/>
<path d="M35.7 174.9v1.9" fill="none" stroke="#000" stroke-width=".19"/>
<circle cx="35.7" cy="176.8" r=".37" fill="#000080"/>
<circle cx="35.7" cy="176.8" r=".37" fill="none" stroke="#000080" stroke-width=".17"/>
<g fill="none" stroke="#000" stroke-width=".19">
<path d="M33.8 178.6v1.5M33.8 184.6v1.5"/>
<circle cx="35.7" cy="174" r=".93"/>
</g>
<path d="M33.1 180.2h1.5v4.4h-1.5z" fill="none" stroke="#00f" stroke-width=".19"/>
<path d="M32 189.8h3.7M32.5 190.4h2.6M33.1 190.9h1.5M33.7 191.5h.3M33.8 187.9v1.9" fill="none" stroke="#800000" stroke-width=".19"/>
<path d="M22.7 175.8h8.4l.9 1-.9 .9h-8.4z" fill-rule="evenodd" fill="#ffff80"/>
<path d="M22.7 175.8h8.4l.9 1-.9 .9h-8.4z" fill="none" stroke="#800000" stroke-width=".17"/>
<path d="M110.3 176.8v1.8M147.5 176.8v1.8M155 165.6v1.8M155 171.2v1.8M155 176.8v1.8M110.3 182.4v1.8M147.5 182.4v1.8M155 182.4v1.8" fill="none" stroke="#000" stroke-width=".19"/>
<g fill="none" stroke="#00f" stroke-width=".19">
<path d="M110.3 178.6v1.5M147.5 178.6v1.5M153.5 169.7h2.9M153.5 168.9h2.9M155 167.4v1.5M155 169.7v1.5M155 178.6v1.5M108.8 180.1h2.9M108.8 180.9h2.9M110.3 180.9v1.5M146.1 180.1h2.9M146.1 180.9h2.9"/>
<path d="M147.5 180.9v1.5M153.5 180.1h3M153.5 180.9h3M155 180.9v1.5"/>
</g>
<path d="M39.4 115.3h11.2v11.1h-11.2z" fill-rule="evenodd" fill="#ffffb0"/>
<path d="M39.4 115.3h11.2v11.1h-11.2z" fill="none" stroke="#800000" stroke-width=".17"/>
<path d="M33.8 117.1h5.6M50.6 117.1h5.6M33.8 124.6h5.6M33.8 120.9h5.6M50.6 124.6h5.6" fill="none" stroke="#000" stroke-width=".19"/>
<circle cx="59.9" cy="117.1" r=".37" fill="#000080"/>
<circle cx="59.9" cy="117.1" r=".37" fill="none" stroke="#000080" stroke-width=".17"/>
<circle cx="59.9" cy="124.6" r=".37" fill="#000080"/>
<circle cx="59.9" cy="124.6" r=".37" fill="none" stroke="#000080" stroke-width=".17"/>
<path d="M59.9 117.1v1.9" fill="none" stroke="#000" stroke-width=".19"/>
<circle cx="59.9" cy="117.1" r=".37" fill="#000080"/>
<circle cx="59.9" cy="117.1" r=".37" fill="none" stroke="#000080" stroke-width=".17"/>
<path d="M59.9 122.7v1.9" fill="none" stroke="#000" stroke-width=".19"/>
<circle cx="59.9" cy="124.6" r=".37" fill="#000080"/>
<circle cx="59.9" cy="124.6" r=".37" fill="none" stroke="#000080" stroke-width=".17"/>
<path d="M59.9 119v1.5M58.5 120.5h2.9M58.5 121.2h2.9M59.9 121.2v1.5M50.6 176.8h1.7M52.3 175.1v3.3M52.7 175.5h1.6M52.7 176.8h1.6v1.8M52.7 178.1h1.6M52.7 175.1v.8M52.7 176.4v.7M52.7 177.7v.7" fill="none" stroke="#00f" stroke-width=".19"/>
<path d="M31 113.4h1.9M32 113.4v1.9M31 128.3h1.9M32 126.4v1.9" fill="none" stroke="#800000" stroke-width=".19"/>
<path d="M48.8 176.8h1.8M54.3 173v1.9M54.3 178.6v1.9" fill="none" stroke="#000" stroke-width=".19"/>
<path d="M52.7 176.8l1.1-.4v.7z" fill="#00f"/>
<path d="M52.7 176.8l1.1-.4v.7z" fill="none" stroke="#00f" stroke-width=".17"/>
<path d="M72.6 105.2h4.4v1.5h-4.4zM41 176h4.4v1.5h-4.4zM54.3 174.9v.6" fill="none" stroke="#00f" stroke-width=".19"/>
<path d="M53.4 158.1h1.9M54.3 158.1v1.9M52.5 189.8h3.7M53 190.4h2.6M53.6 190.9h1.5M54.2 191.5h.3M54.3 187.9v1.9" fill="none" stroke="#800000" stroke-width=".19"/>
<path d="M71.1 105.9h1.5M77.1 105.9h1.5M39.4 176.8h1.5M45.4 176.8h1.5" fill="none" stroke="#000" stroke-width=".19"/>
<path d="M26.4 25.8v3.7M212.8 98.5h7.4M194.1 105.9h26.1M212.8 100.4h7.4M218.3 119h1.9" fill="none" stroke="#000080" stroke-width=".19"/>
<circle cx="218.3" cy="119" r=".37" fill="#000080"/>
<circle cx="218.3" cy="119" r=".37" fill="none" stroke="#000080" stroke-width=".17"/>
<path d="M253.8 96.6h3.7M253.8 111.5h1.8" fill="none" stroke="#000080" stroke-width=".19"/>
<circle cx="257.5" cy="96.6" r=".37" fill="#000080"/>
<circle cx="257.5" cy="96.6" r=".37" fill="none" stroke="#000080" stroke-width=".17"/>
<path d="M218.3 120.9v1.8" fill="none" stroke="#000080" stroke-width=".19"/>
<circle cx="218.3" cy="120.9" r=".37" fill="#000080"/>
<circle cx="218.3" cy="120.9" r=".37" fill="none" stroke="#000080" stroke-width=".17"/>
<path d="M218.3 94.8v1.8" fill="none" stroke="#000080" stroke-width=".19"/>
<circle cx="218.3" cy="96.6" r=".37" fill="#000080"/>
<circle cx="218.3" cy="96.6" r=".37" fill="none" stroke="#000080" stroke-width=".17"/>
<path d="M263.1 98.5v1.9h-9.3M264.9 107.8v11.2h-1.8M276.1 105.9h1.9M276.1 107.8h1.9" fill="none" stroke="#000080" stroke-width=".19"/>
<circle cx="264.9" cy="107.8" r=".37" fill="#000080"/>
<circle cx="264.9" cy="107.8" r=".37" fill="none" stroke="#000080" stroke-width=".17"/>
<path d="M259.3 137.6v1.9" fill="none" stroke="#000080" stroke-width=".19"/>
<circle cx="259.3" cy="137.6" r=".37" fill="#000080"/>
<circle cx="259.3" cy="137.6" r=".37" fill="none" stroke="#000080" stroke-width=".17"/>
<path d="M248.2 137.6h-5.6v1.9" fill="none" stroke="#000080" stroke-width=".19"/>
<circle cx="248.2" cy="137.6" r=".37" fill="#000080"/>
<circle cx="248.2" cy="137.6" r=".37" fill="none" stroke="#000080" stroke-width=".17"/>
<path d="M253.8 137.6h-5.6v1.9" fill="none" stroke="#000080" stroke-width=".19"/>
<circle cx="248.2" cy="137.6" r=".37" fill="#000080"/>
<circle cx="248.2" cy="137.6" r=".37" fill="none" stroke="#000080" stroke-width=".17"/>
<circle cx="253.8" cy="137.6" r=".37" fill="#000080"/>
<circle cx="253.8" cy="137.6" r=".37" fill="none" stroke="#000080" stroke-width=".17"/>
<path d="M266.8 105.9v13.1h1.9M231.4 135.8v3.7" fill="none" stroke="#000080" stroke-width=".19"/>
<circle cx="266.8" cy="105.9" r=".37" fill="#000080"/>
<circle cx="266.8" cy="105.9" r=".37" fill="none" stroke="#000080" stroke-width=".17"/>
<path d="M203.4 120.9v1.8" fill="none" stroke="#000080" stroke-width=".19"/>
<circle cx="203.4" cy="122.7" r=".37" fill="#000080"/>
<circle cx="203.4" cy="122.7" r=".37" fill="none" stroke="#000080" stroke-width=".17"/>
<path d="M212.8 96.6h7.4M209 143.2v1.9" fill="none" stroke="#000080" stroke-width=".19"/>
<circle cx="214.6" cy="96.6" r=".37" fill="#000080"/>
<circle cx="214.6" cy="96.6" r=".37" fill="none" stroke="#000080" stroke-width=".17"/>
<circle cx="218.3" cy="96.6" r=".37" fill="#000080"/>
<circle cx="218.3" cy="96.6" r=".37" fill="none" stroke="#000080" stroke-width=".17"/>
<path d="M220.2 117.1h-1.9v3.8h1.9" fill="none" stroke="#000080" stroke-width=".19"/>
<circle cx="218.3" cy="119" r=".37" fill="#000080"/>
<circle cx="218.3" cy="119" r=".37" fill="none" stroke="#000080" stroke-width=".17"/>
<circle cx="218.3" cy="120.9" r=".37" fill="#000080"/>
<circle cx="218.3" cy="120.9" r=".37" fill="none" stroke="#000080" stroke-width=".17"/>
<path d="M253.8 107.8h14.9" fill="none" stroke="#000080" stroke-width=".19"/>
<circle cx="264.9" cy="107.8" r=".37" fill="#000080"/>
<circle cx="264.9" cy="107.8" r=".37" fill="none" stroke="#000080" stroke-width=".17"/>
<path d="M253.8 105.9h14.9" fill="none" stroke="#000080" stroke-width=".19"/>
<circle cx="266.8" cy="105.9" r=".37" fill="#000080"/>
<circle cx="266.8" cy="105.9" r=".37" fill="none" stroke="#000080" stroke-width=".17"/>
<path d="M257.5 94.8v3.7h-3.7" fill="none" stroke="#000080" stroke-width=".19"/>
<circle cx="257.5" cy="96.6" r=".37" fill="#000080"/>
<circle cx="257.5" cy="96.6" r=".37" fill="none" stroke="#000080" stroke-width=".17"/>
<path d="M264.9 135.8v1.8h-11.1v1.9" fill="none" stroke="#000080" stroke-width=".19"/>
<circle cx="253.8" cy="137.6" r=".37" fill="#000080"/>
<circle cx="253.8" cy="137.6" r=".37" fill="none" stroke="#000080" stroke-width=".17"/>
<circle cx="259.3" cy="137.6" r=".37" fill="#000080"/>
<circle cx="259.3" cy="137.6" r=".37" fill="none" stroke="#000080" stroke-width=".17"/>
<path d="M52.5 46.3h3.7" fill="none" stroke="#000080" stroke-width=".19"/>
<circle cx="56.2" cy="46.3" r=".37" fill="#000080"/>
<circle cx="56.2" cy="46.3" r=".37" fill="none" stroke="#000080" stroke-width=".17"/>
<circle cx="54.3" cy="46.3" r=".37" fill="#000080"/>
<circle cx="54.3" cy="46.3" r=".37" fill="none" stroke="#000080" stroke-width=".17"/>
<path d="M58.1 46.3h-1.9v1.9" fill="none" stroke="#000080" stroke-width=".19"/>
<circle cx="56.2" cy="46.3" r=".37" fill="#000080"/>
<circle cx="56.2" cy="46.3" r=".37" fill="none" stroke="#000080" stroke-width=".17"/>
<path d="M56.2 31.4v7.5h3.7" fill="none" stroke="#000080" stroke-width=".19"/>
<circle cx="56.2" cy="31.4" r=".37" fill="#000080"/>
<circle cx="56.2" cy="31.4" r=".37" fill="none" stroke="#000080" stroke-width=".17"/>
<path d="M56.2 29.5v1.9h3.7" fill="none" stroke="#000080" stroke-width=".19"/>
<circle cx="56.2" cy="31.4" r=".37" fill="#000080"/>
<circle cx="56.2" cy="31.4" r=".37" fill="none" stroke="#000080" stroke-width=".17"/>
<path d="M67.4 38.9h5.6M65.5 46.3h1.9" fill="none" stroke="#000080" stroke-width=".19"/>
<circle cx="73" cy="38.9" r=".37" fill="#000080"/>
<circle cx="73" cy="38.9" r=".37" fill="none" stroke="#000080" stroke-width=".17"/>
<path d="M67.4 31.4h5.6v11.2M102.8 24h3.7M128.9 33.3v1.8M56.2 55.6v1.9M73 50v7.5" fill="none" stroke="#000080" stroke-width=".19"/>
<circle cx="73" cy="38.9" r=".37" fill="#000080"/>
<circle cx="73" cy="38.9" r=".37" fill="none" stroke="#000080" stroke-width=".17"/>
<path d="M164.3 22.1h18.6M205.3 33.3v1.8M175.5 46.3h3.7" fill="none" stroke="#000080" stroke-width=".19"/>
<circle cx="179.2" cy="46.3" r=".37" fill="#000080"/>
<circle cx="179.2" cy="46.3" r=".37" fill="none" stroke="#000080" stroke-width=".17"/>
<circle cx="177.3" cy="46.3" r=".37" fill="#000080"/>
<circle cx="177.3" cy="46.3" r=".37" fill="none" stroke="#000080" stroke-width=".17"/>
<path d="M181.1 46.3h-1.9v1.9" fill="none" stroke="#000080" stroke-width=".19"/>
<circle cx="179.2" cy="46.3" r=".37" fill="#000080"/>
<circle cx="179.2" cy="46.3" r=".37" fill="none" stroke="#000080" stroke-width=".17"/>
<path d="M179.2 31.4v7.5h3.7" fill="none" stroke="#000080" stroke-width=".19"/>
<circle cx="179.2" cy="31.4" r=".37" fill="#000080"/>
<circle cx="179.2" cy="31.4" r=".37" fill="none" stroke="#000080" stroke-width=".17"/>
<path d="M179.2 29.5v1.9h3.7" fill="none" stroke="#000080" stroke-width=".19"/>
<circle cx="179.2" cy="31.4" r=".37" fill="#000080"/>
<circle cx="179.2" cy="31.4" r=".37" fill="none" stroke="#000080" stroke-width=".17"/>
<path d="M190.4 38.9h5.6M188.5 46.3h1.9" fill="none" stroke="#000080" stroke-width=".19"/>
<circle cx="196" cy="38.9" r=".37" fill="#000080"/>
<circle cx="196" cy="38.9" r=".37" fill="none" stroke="#000080" stroke-width=".17"/>
<path d="M190.4 31.4h5.6v11.2M179.2 55.6v1.9M196 50v7.5" fill="none" stroke="#000080" stroke-width=".19"/>
<circle cx="196" cy="38.9" r=".37" fill="#000080"/>
<circle cx="196" cy="38.9" r=".37" fill="none" stroke="#000080" stroke-width=".17"/>
<path d="M67.4 20.2h89.4M89.8 24v9.3h1.8M190.4 20.2h11.2M190.4 24h3.7M209 20.2h3.8M223.9 33.3v1.8M237 22.1h11.2M80.4 42.6v1.8M140.1 46.3v1.9M147.5 46.3v1.9" fill="none" stroke="#000080" stroke-width=".19"/>
<circle cx="89.8" cy="23.9" r=".37" fill="#000080"/>
<circle cx="89.8" cy="23.9" r=".37" fill="none" stroke="#000080" stroke-width=".17"/>
<path d="M99.1 33.3h1.8M147.5 35.1v3.8M155 46.3v1.9" fill="none" stroke="#000080" stroke-width=".19"/>
<circle cx="147.5" cy="35.1" r=".37" fill="#000080"/>
<circle cx="147.5" cy="35.1" r=".37" fill="none" stroke="#000080" stroke-width=".17"/>
<path d="M140.1 35.1v3.8" fill="none" stroke="#000080" stroke-width=".19"/>
<circle cx="140.1" cy="35.1" r=".37" fill="#000080"/>
<circle cx="140.1" cy="35.1" r=".37" fill="none" stroke="#000080" stroke-width=".17"/>
<path d="M201.6 24h27.9" fill="none" stroke="#000080" stroke-width=".19"/>
<circle cx="205.3" cy="23.9" r=".37" fill="#000080"/>
<circle cx="205.3" cy="23.9" r=".37" fill="none" stroke="#000080" stroke-width=".17"/>
<path d="M205.3 24v1.8" fill="none" stroke="#000080" stroke-width=".19"/>
<circle cx="205.3" cy="23.9" r=".37" fill="#000080"/>
<circle cx="205.3" cy="23.9" r=".37" fill="none" stroke="#000080" stroke-width=".17"/>
<path d="M220.2 20.2h9.3" fill="none" stroke="#000080" stroke-width=".19"/>
<circle cx="223.9" cy="20.2" r=".37" fill="#000080"/>
<circle cx="223.9" cy="20.2" r=".37" fill="none" stroke="#000080" stroke-width=".17"/>
<path d="M223.9 20.2v5.6" fill="none" stroke="#000080" stroke-width=".19"/>
<circle cx="223.9" cy="20.2" r=".37" fill="#000080"/>
<circle cx="223.9" cy="20.2" r=".37" fill="none" stroke="#000080" stroke-width=".17"/>
<path d="M128.9 24v1.8" fill="none" stroke="#000080" stroke-width=".19"/>
<circle cx="128.9" cy="23.9" r=".37" fill="#000080"/>
<circle cx="128.9" cy="23.9" r=".37" fill="none" stroke="#000080" stroke-width=".17"/>
<path d="M110.3 33.3h1.8" fill="none" stroke="#000080" stroke-width=".19"/>
<circle cx="110.3" cy="33.3" r=".37" fill="#000080"/>
<circle cx="110.3" cy="33.3" r=".37" fill="none" stroke="#000080" stroke-width=".17"/>
<path d="M67.4 24h27.9" fill="none" stroke="#000080" stroke-width=".19"/>
<circle cx="80.4" cy="23.9" r=".37" fill="#000080"/>
<circle cx="80.4" cy="23.9" r=".37" fill="none" stroke="#000080" stroke-width=".17"/>
<circle cx="89.8" cy="23.9" r=".37" fill="#000080"/>
<circle cx="89.8" cy="23.9" r=".37" fill="none" stroke="#000080" stroke-width=".17"/>
<path d="M80.4 23.9v1.9M80.4 33.3v1.8" fill="none" stroke="#000080" stroke-width=".19"/>
<circle cx="80.4" cy="23.9" r=".37" fill="#000080"/>
<circle cx="80.4" cy="23.9" r=".37" fill="none" stroke="#000080" stroke-width=".17"/>
<path d="M30.1 22.1h29.8M177.3 119v1.9" fill="none" stroke="#000080" stroke-width=".19"/>
<circle cx="177.3" cy="119" r=".37" fill="#000080"/>
<circle cx="177.3" cy="119" r=".37" fill="none" stroke="#000080" stroke-width=".17"/>
<path d="M97.2 122.7h1.9v16.8h-7.5" fill="none" stroke="#000080" stroke-width=".19"/>
<circle cx="99.1" cy="122.7" r=".37" fill="#000080"/>
<circle cx="99.1" cy="122.7" r=".37" fill="none" stroke="#000080" stroke-width=".17"/>
<path d="M166.2 119h1.8" fill="none" stroke="#000080" stroke-width=".19"/>
<circle cx="166.2" cy="119" r=".37" fill="#000080"/>
<circle cx="166.2" cy="119" r=".37" fill="none" stroke="#000080" stroke-width=".17"/>
<path d="M110.3 163.7v1.9" fill="none" stroke="#000080" stroke-width=".19"/>
<circle cx="110.3" cy="163.7" r=".37" fill="#000080"/>
<circle cx="110.3" cy="163.7" r=".37" fill="none" stroke="#000080" stroke-width=".17"/>
<path d="M125.2 163.7v1.9" fill="none" stroke="#000080" stroke-width=".19"/>
<circle cx="125.2" cy="163.7" r=".37" fill="#000080"/>
<circle cx="125.2" cy="163.7" r=".37" fill="none" stroke="#000080" stroke-width=".17"/>
<path d="M132.6 163.7v1.9" fill="none" stroke="#000080" stroke-width=".19"/>
<circle cx="132.6" cy="163.7" r=".37" fill="#000080"/>
<circle cx="132.6" cy="163.7" r=".37" fill="none" stroke="#000080" stroke-width=".17"/>
<path d="M59.9 139.5v1.9M140.1 163.7v1.9" fill="none" stroke="#000080" stroke-width=".19"/>
<circle cx="140.1" cy="163.7" r=".37" fill="#000080"/>
<circle cx="140.1" cy="163.7" r=".37" fill="none" stroke="#000080" stroke-width=".17"/>
<path d="M89.8 105.9h1.8M99.1 122.7h1.8M166.2 145.1v1.8" fill="none" stroke="#000080" stroke-width=".19"/>
<circle cx="99.1" cy="122.7" r=".37" fill="#000080"/>
<circle cx="99.1" cy="122.7" r=".37" fill="none" stroke="#000080" stroke-width=".17"/>
<path d="M153.1 109.7h1.9v3.7M115.8 122.7v11.2M147.5 132v1.9" fill="none" stroke="#000080" stroke-width=".19"/>
<circle cx="155" cy="113.4" r=".37" fill="#000080"/>
<circle cx="155" cy="113.4" r=".37" fill="none" stroke="#000080" stroke-width=".17"/>
<path d="M114 100.4h1.8" fill="none" stroke="#000080" stroke-width=".19"/>
<circle cx="114" cy="100.4" r=".37" fill="#000080"/>
<circle cx="114" cy="100.4" r=".37" fill="none" stroke="#000080" stroke-width=".17"/>
<path d="M114 98.5h1.8" fill="none" stroke="#000080" stroke-width=".19"/>
<circle cx="114" cy="98.5" r=".37" fill="#000080"/>
<circle cx="114" cy="98.5" r=".37" fill="none" stroke="#000080" stroke-width=".17"/>
<path d="M110.3 122.7v1.9" fill="none" stroke="#000080" stroke-width=".19"/>
<circle cx="110.3" cy="122.7" r=".37" fill="#000080"/>
<circle cx="110.3" cy="122.7" r=".37" fill="none" stroke="#000080" stroke-width=".17"/>
<path d="M110.3 132v1.9M166.2 135.8h5.6v5.6h1.8M177.3 145.1v1.8" fill="none" stroke="#000080" stroke-width=".19"/>
<circle cx="166.2" cy="135.8" r=".37" fill="#000080"/>
<circle cx="166.2" cy="135.8" r=".37" fill="none" stroke="#000080" stroke-width=".17"/>
<path d="M132.6 184.2v1.9" fill="none" stroke="#000080" stroke-width=".19"/>
<circle cx="132.6" cy="186.1" r=".37" fill="#000080"/>
<circle cx="132.6" cy="186.1" r=".37" fill="none" stroke="#000080" stroke-width=".17"/>
<path d="M125.2 184.2v1.9" fill="none" stroke="#000080" stroke-width=".19"/>
<circle cx="125.2" cy="186.1" r=".37" fill="#000080"/>
<circle cx="125.2" cy="186.1" r=".37" fill="none" stroke="#000080" stroke-width=".17"/>
<path d="M117.7 184.2v1.9" fill="none" stroke="#000080" stroke-width=".19"/>
<circle cx="117.7" cy="186.1" r=".37" fill="#000080"/>
<circle cx="117.7" cy="186.1" r=".37" fill="none" stroke="#000080" stroke-width=".17"/>
<path d="M166.2 105.9v3.8" fill="none" stroke="#000080" stroke-width=".19"/>
<circle cx="166.2" cy="105.9" r=".37" fill="#000080"/>
<circle cx="166.2" cy="105.9" r=".37" fill="none" stroke="#000080" stroke-width=".17"/>
<path d="M104.7 105.9v3.8h1.8M114 109.7h1.8" fill="none" stroke="#000080" stroke-width=".19"/>
<circle cx="104.7" cy="105.9" r=".37" fill="#000080"/>
<circle cx="104.7" cy="105.9" r=".37" fill="none" stroke="#000080" stroke-width=".17"/>
<path d="M177.3 117.1v1.9h-1.8" fill="none" stroke="#000080" stroke-width=".19"/>
<circle cx="177.3" cy="119" r=".37" fill="#000080"/>
<circle cx="177.3" cy="119" r=".37" fill="none" stroke="#000080" stroke-width=".17"/>
<path d="M145.7 113.4h9.3v3.7h-9.3M145.7 122.7h1.8v1.9" fill="none" stroke="#000080" stroke-width=".19"/>
<circle cx="155" cy="117.1" r=".37" fill="#000080"/>
<circle cx="155" cy="117.1" r=".37" fill="none" stroke="#000080" stroke-width=".17"/>
<circle cx="155" cy="113.4" r=".37" fill="#000080"/>
<circle cx="155" cy="113.4" r=".37" fill="none" stroke="#000080" stroke-width=".17"/>
<path d="M155 117.1v1.9" fill="none" stroke="#000080" stroke-width=".19"/>
<circle cx="155" cy="119" r=".37" fill="#000080"/>
<circle cx="155" cy="119" r=".37" fill="none" stroke="#000080" stroke-width=".17"/>
<circle cx="155" cy="117.1" r=".37" fill="#000080"/>
<circle cx="155" cy="117.1" r=".37" fill="none" stroke="#000080" stroke-width=".17"/>
<path d="M115.8 113.4h-5.5v9.3h-1.9" fill="none" stroke="#000080" stroke-width=".19"/>
<circle cx="110.3" cy="122.7" r=".37" fill="#000080"/>
<circle cx="110.3" cy="122.7" r=".37" fill="none" stroke="#000080" stroke-width=".17"/>
<path d="M110.3 184.2v1.9" fill="none" stroke="#000080" stroke-width=".19"/>
<circle cx="110.3" cy="186.1" r=".37" fill="#000080"/>
<circle cx="110.3" cy="186.1" r=".37" fill="none" stroke="#000080" stroke-width=".17"/>
<path d="M140.1 184.2v1.9" fill="none" stroke="#000080" stroke-width=".19"/>
<circle cx="140.1" cy="186.1" r=".37" fill="#000080"/>
<circle cx="140.1" cy="186.1" r=".37" fill="none" stroke="#000080" stroke-width=".17"/>
<path d="M155 120.9v14.9" fill="none" stroke="#000080" stroke-width=".19"/>
<circle cx="155" cy="120.9" r=".37" fill="#000080"/>
<circle cx="155" cy="120.9" r=".37" fill="none" stroke="#000080" stroke-width=".17"/>
<path d="M33.8 176.8v1.8M33.8 186.1v1.8" fill="none" stroke="#000080" stroke-width=".19"/>
<circle cx="33.8" cy="176.8" r=".37" fill="#000080"/>
<circle cx="33.8" cy="176.8" r=".37" fill="none" stroke="#000080" stroke-width=".17"/>
<path d="M166.2 122.7h-5.6v22.4h-89.5v-5.6h13.1" fill="none" stroke="#000080" stroke-width=".19"/>
<circle cx="166.2" cy="122.7" r=".37" fill="#000080"/>
<circle cx="166.2" cy="122.7" r=".37" fill="none" stroke="#000080" stroke-width=".17"/>
<circle cx="71.1" cy="139.5" r=".37" fill="#000080"/>
<circle cx="71.1" cy="139.5" r=".37" fill="none" stroke="#000080" stroke-width=".17"/>
<path d="M71.1 126.4v13.1" fill="none" stroke="#000080" stroke-width=".19"/>
<circle cx="71.1" cy="139.5" r=".37" fill="#000080"/>
<circle cx="71.1" cy="139.5" r=".37" fill="none" stroke="#000080" stroke-width=".17"/>
<path d="M145.7 119h9.3v1.9h-9.3" fill="none" stroke="#000080" stroke-width=".19"/>
<circle cx="155" cy="120.9" r=".37" fill="#000080"/>
<circle cx="155" cy="120.9" r=".37" fill="none" stroke="#000080" stroke-width=".17"/>
<circle cx="155" cy="119" r=".37" fill="#000080"/>
<circle cx="155" cy="119" r=".37" fill="none" stroke="#000080" stroke-width=".17"/>
<path d="M132.6 174.9v1.9" fill="none" stroke="#000080" stroke-width=".19"/>
<circle cx="132.6" cy="174.9" r=".37" fill="#000080"/>
<circle cx="132.6" cy="174.9" r=".37" fill="none" stroke="#000080" stroke-width=".17"/>
<path d="M147.5 163.7h7.5v1.9" fill="none" stroke="#000080" stroke-width=".19"/>
<circle cx="147.5" cy="163.7" r=".37" fill="#000080"/>
<circle cx="147.5" cy="163.7" r=".37" fill="none" stroke="#000080" stroke-width=".17"/>
<path d="M155 184.2v1.9h-7.5" fill="none" stroke="#000080" stroke-width=".19"/>
<circle cx="147.5" cy="186.1" r=".37" fill="#000080"/>
<circle cx="147.5" cy="186.1" r=".37" fill="none" stroke="#000080" stroke-width=".17"/>
<path d="M155 173v1.9h-7.5" fill="none" stroke="#000080" stroke-width=".19"/>
<circle cx="147.5" cy="174.9" r=".37" fill="#000080"/>
<circle cx="147.5" cy="174.9" r=".37" fill="none" stroke="#000080" stroke-width=".17"/>
<circle cx="155" cy="174.9" r=".37" fill="#000080"/>
<circle cx="155" cy="174.9" r=".37" fill="none" stroke="#000080" stroke-width=".17"/>
<path d="M155 174.9v1.9" fill="none" stroke="#000080" stroke-width=".19"/>
<circle cx="155" cy="174.9" r=".37" fill="#000080"/>
<circle cx="155" cy="174.9" r=".37" fill="none" stroke="#000080" stroke-width=".17"/>
<path d="M140.1 173v1.9" fill="none" stroke="#000080" stroke-width=".19"/>
<circle cx="140.1" cy="174.9" r=".37" fill="#000080"/>
<circle cx="140.1" cy="174.9" r=".37" fill="none" stroke="#000080" stroke-width=".17"/>
<path d="M140.1 174.9v1.9" fill="none" stroke="#000080" stroke-width=".19"/>
<circle cx="140.1" cy="174.9" r=".37" fill="#000080"/>
<circle cx="140.1" cy="174.9" r=".37" fill="none" stroke="#000080" stroke-width=".17"/>
<path d="M132.6 173v1.9" fill="none" stroke="#000080" stroke-width=".19"/>
<circle cx="132.6" cy="174.9" r=".37" fill="#000080"/>
<circle cx="132.6" cy="174.9" r=".37" fill="none" stroke="#000080" stroke-width=".17"/>
<path d="M125.2 173v1.9" fill="none" stroke="#000080" stroke-width=".19"/>
<circle cx="125.2" cy="174.9" r=".37" fill="#000080"/>
<circle cx="125.2" cy="174.9" r=".37" fill="none" stroke="#000080" stroke-width=".17"/>
<path d="M125.2 174.9v1.9" fill="none" stroke="#000080" stroke-width=".19"/>
<circle cx="125.2" cy="174.9" r=".37" fill="#000080"/>
<circle cx="125.2" cy="174.9" r=".37" fill="none" stroke="#000080" stroke-width=".17"/>
<path d="M117.7 174.9v1.9" fill="none" stroke="#000080" stroke-width=".19"/>
<circle cx="117.7" cy="174.9" r=".37" fill="#000080"/>
<circle cx="117.7" cy="174.9" r=".37" fill="none" stroke="#000080" stroke-width=".17"/>
<path d="M117.7 173v1.9" fill="none" stroke="#000080" stroke-width=".19"/>
<circle cx="117.7" cy="174.9" r=".37" fill="#000080"/>
<circle cx="117.7" cy="174.9" r=".37" fill="none" stroke="#000080" stroke-width=".17"/>
<path d="M114 94.8v7.4h1.8" fill="none" stroke="#000080" stroke-width=".19"/>
<circle cx="114" cy="100.4" r=".37" fill="#000080"/>
<circle cx="114" cy="100.4" r=".37" fill="none" stroke="#000080" stroke-width=".17"/>
<circle cx="114" cy="98.5" r=".37" fill="#000080"/>
<circle cx="114" cy="98.5" r=".37" fill="none" stroke="#000080" stroke-width=".17"/>
<path d="M166.2 133.9v3.7" fill="none" stroke="#000080" stroke-width=".19"/>
<circle cx="166.2" cy="135.8" r=".37" fill="#000080"/>
<circle cx="166.2" cy="135.8" r=".37" fill="none" stroke="#000080" stroke-width=".17"/>
<path d="M166.2 117.1v9.3" fill="none" stroke="#000080" stroke-width=".19"/>
<circle cx="166.2" cy="119" r=".37" fill="#000080"/>
<circle cx="166.2" cy="119" r=".37" fill="none" stroke="#000080" stroke-width=".17"/>
<circle cx="166.2" cy="122.7" r=".37" fill="#000080"/>
<circle cx="166.2" cy="122.7" r=".37" fill="none" stroke="#000080" stroke-width=".17"/>
<path d="M41.3 105.9h18.6" fill="none" stroke="#000080" stroke-width=".19"/>
<circle cx="59.9" cy="105.9" r=".37" fill="#000080"/>
<circle cx="59.9" cy="105.9" r=".37" fill="none" stroke="#000080" stroke-width=".17"/>
<path d="M59.9 124.6v7.4" fill="none" stroke="#000080" stroke-width=".19"/>
<circle cx="59.9" cy="128.3" r=".37" fill="#000080"/>
<circle cx="59.9" cy="128.3" r=".37" fill="none" stroke="#000080" stroke-width=".17"/>
<circle cx="59.9" cy="124.6" r=".37" fill="#000080"/>
<circle cx="59.9" cy="124.6" r=".37" fill="none" stroke="#000080" stroke-width=".17"/>
<path d="M59.9 115.3v1.8" fill="none" stroke="#000080" stroke-width=".19"/>
<circle cx="59.9" cy="117.1" r=".37" fill="#000080"/>
<circle cx="59.9" cy="117.1" r=".37" fill="none" stroke="#000080" stroke-width=".17"/>
<path d="M71.1 119h-3.7v9.3h-7.5" fill="none" stroke="#000080" stroke-width=".19"/>
<circle cx="59.9" cy="128.3" r=".37" fill="#000080"/>
<circle cx="59.9" cy="128.3" r=".37" fill="none" stroke="#000080" stroke-width=".17"/>
<path d="M32 115.3v1.8h1.8M33.8 124.6h-1.8v1.8M54.3 160v1.9M46.9 176.8h1.9M54.3 171.2h13.1M54.3 180.5v7.4" fill="none" stroke="#000080" stroke-width=".19"/>
<circle cx="54.3" cy="171.2" r=".37" fill="#000080"/>
<circle cx="54.3" cy="171.2" r=".37" fill="none" stroke="#000080" stroke-width=".17"/>
<path d="M56.2 117.1h3.7M22.7 120.9h11.1" fill="none" stroke="#000080" stroke-width=".19"/>
<circle cx="59.9" cy="117.1" r=".37" fill="#000080"/>
<circle cx="59.9" cy="117.1" r=".37" fill="none" stroke="#000080" stroke-width=".17"/>
<path d="M56.2 124.6h3.7" fill="none" stroke="#000080" stroke-width=".19"/>
<circle cx="59.9" cy="124.6" r=".37" fill="#000080"/>
<circle cx="59.9" cy="124.6" r=".37" fill="none" stroke="#000080" stroke-width=".17"/>
<path d="M71.1 105.9h-11.2v1.9" fill="none" stroke="#000080" stroke-width=".19"/>
<circle cx="59.9" cy="105.9" r=".37" fill="#000080"/>
<circle cx="59.9" cy="105.9" r=".37" fill="none" stroke="#000080" stroke-width=".17"/>
<path d="M78.6 105.9h3.7M99.1 105.9h16.7" fill="none" stroke="#000080" stroke-width=".19"/>
<circle cx="104.7" cy="105.9" r=".37" fill="#000080"/>
<circle cx="104.7" cy="105.9" r=".37" fill="none" stroke="#000080" stroke-width=".17"/>
<path d="M145.7 105.9h41" fill="none" stroke="#000080" stroke-width=".19"/>
<circle cx="166.2" cy="105.9" r=".37" fill="#000080"/>
<circle cx="166.2" cy="105.9" r=".37" fill="none" stroke="#000080" stroke-width=".17"/>
<path d="M32 176.8h7.4" fill="none" stroke="#000080" stroke-width=".19"/>
<circle cx="33.8" cy="176.8" r=".37" fill="#000080"/>
<circle cx="33.8" cy="176.8" r=".37" fill="none" stroke="#000080" stroke-width=".17"/>
<circle cx="35.7" cy="176.8" r=".37" fill="#000080"/>
<circle cx="35.7" cy="176.8" r=".37" fill="none" stroke="#000080" stroke-width=".17"/>
<path d="M147.5 184.2v1.9h-42.8" fill="none" stroke="#000080" stroke-width=".19"/>
<circle cx="110.3" cy="186.1" r=".37" fill="#000080"/>
<circle cx="110.3" cy="186.1" r=".37" fill="none" stroke="#000080" stroke-width=".17"/>
<circle cx="117.7" cy="186.1" r=".37" fill="#000080"/>
<circle cx="117.7" cy="186.1" r=".37" fill="none" stroke="#000080" stroke-width=".17"/>
<circle cx="125.2" cy="186.1" r=".37" fill="#000080"/>
<circle cx="125.2" cy="186.1" r=".37" fill="none" stroke="#000080" stroke-width=".17"/>
<circle cx="132.6" cy="186.1" r=".37" fill="#000080"/>
<circle cx="132.6" cy="186.1" r=".37" fill="none" stroke="#000080" stroke-width=".17"/>
<circle cx="140.1" cy="186.1" r=".37" fill="#000080"/>
<circle cx="140.1" cy="186.1" r=".37" fill="none" stroke="#000080" stroke-width=".17"/>
<circle cx="147.5" cy="186.1" r=".37" fill="#000080"/>
<circle cx="147.5" cy="186.1" r=".37" fill="none" stroke="#000080" stroke-width=".17"/>
<path d="M104.7 163.7h13v1.9" fill="none" stroke="#000080" stroke-width=".19"/>
<circle cx="110.3" cy="163.7" r=".37" fill="#000080"/>
<circle cx="110.3" cy="163.7" r=".37" fill="none" stroke="#000080" stroke-width=".17"/>
<circle cx="117.7" cy="163.7" r=".37" fill="#000080"/>
<circle cx="117.7" cy="163.7" r=".37" fill="none" stroke="#000080" stroke-width=".17"/>
<path d="M110.3 174.9h37.2" fill="none" stroke="#000080" stroke-width=".19"/>
<circle cx="147.5" cy="174.9" r=".37" fill="#000080"/>
<circle cx="147.5" cy="174.9" r=".37" fill="none" stroke="#000080" stroke-width=".17"/>
<circle cx="140.1" cy="174.9" r=".37" fill="#000080"/>
<circle cx="140.1" cy="174.9" r=".37" fill="none" stroke="#000080" stroke-width=".17"/>
<circle cx="132.6" cy="174.9" r=".37" fill="#000080"/>
<circle cx="132.6" cy="174.9" r=".37" fill="none" stroke="#000080" stroke-width=".17"/>
<circle cx="125.2" cy="174.9" r=".37" fill="#000080"/>
<circle cx="125.2" cy="174.9" r=".37" fill="none" stroke="#000080" stroke-width=".17"/>
<circle cx="117.7" cy="174.9" r=".37" fill="#000080"/>
<circle cx="117.7" cy="174.9" r=".37" fill="none" stroke="#000080" stroke-width=".17"/>
<circle cx="110.3" cy="174.9" r=".37" fill="#000080"/>
<circle cx="110.3" cy="174.9" r=".37" fill="none" stroke="#000080" stroke-width=".17"/>
<path d="M117.7 163.7h29.8v1.9" fill="none" stroke="#000080" stroke-width=".19"/>
<circle cx="117.7" cy="163.7" r=".37" fill="#000080"/>
<circle cx="117.7" cy="163.7" r=".37" fill="none" stroke="#000080" stroke-width=".17"/>
<circle cx="125.2" cy="163.7" r=".37" fill="#000080"/>
<circle cx="125.2" cy="163.7" r=".37" fill="none" stroke="#000080" stroke-width=".17"/>
<circle cx="132.6" cy="163.7" r=".37" fill="#000080"/>
<circle cx="132.6" cy="163.7" r=".37" fill="none" stroke="#000080" stroke-width=".17"/>
<circle cx="140.1" cy="163.7" r=".37" fill="#000080"/>
<circle cx="140.1" cy="163.7" r=".37" fill="none" stroke="#000080" stroke-width=".17"/>
<circle cx="147.5" cy="163.7" r=".37" fill="#000080"/>
<circle cx="147.5" cy="163.7" r=".37" fill="none" stroke="#000080" stroke-width=".17"/>
<path d="M54.3 169.3v3.7" fill="none" stroke="#000080" stroke-width=".19"/>
<circle cx="54.3" cy="171.2" r=".37" fill="#000080"/>
<circle cx="54.3" cy="171.2" r=".37" fill="none" stroke="#000080" stroke-width=".17"/>
<path d="M110.3 173v3.8" fill="none" stroke="#000080" stroke-width=".19"/>
<circle cx="110.3" cy="174.9" r=".37" fill="#000080"/>
<circle cx="110.3" cy="174.9" r=".37" fill="none" stroke="#000080" stroke-width=".17"/>
<path d="M147.5 173v3.8" fill="none" stroke="#000080" stroke-width=".19"/>
<circle cx="147.5" cy="174.9" r=".37" fill="#000080"/>
<circle cx="147.5" cy="174.9" r=".37" fill="none" stroke="#000080" stroke-width=".17"/>
<path d="M106.5 174.9h3.8" fill="none" stroke="#000080" stroke-width=".19"/>
<circle cx="110.3" cy="174.9" r=".37" fill="#000080"/>
<circle cx="110.3" cy="174.9" r=".37" fill="none" stroke="#000080" stroke-width=".17"/>
<path d="M201.6 132v1.9" fill="none" stroke="#000080" stroke-width=".19"/>
<circle cx="201.6" cy="133.9" r=".37" fill="#000080"/>
<circle cx="201.6" cy="133.9" r=".37" fill="none" stroke="#000080" stroke-width=".17"/>
<path d="M203.4 122.7h1.9v1.9" fill="none" stroke="#000080" stroke-width=".19"/>
<circle cx="203.4" cy="122.7" r=".37" fill="#000080"/>
<circle cx="203.4" cy="122.7" r=".37" fill="none" stroke="#000080" stroke-width=".17"/>
<path d="M203.4 122.7h-1.8v1.9" fill="none" stroke="#000080" stroke-width=".19"/>
<circle cx="203.4" cy="122.7" r=".37" fill="#000080"/>
<circle cx="203.4" cy="122.7" r=".37" fill="none" stroke="#000080" stroke-width=".17"/>
<path d="M209 133.9v1.9" fill="none" stroke="#000080" stroke-width=".19"/>
<circle cx="209" cy="133.9" r=".37" fill="#000080"/>
<circle cx="209" cy="133.9" r=".37" fill="none" stroke="#000080" stroke-width=".17"/>
<path d="M197.8 133.9h7.5" fill="none" stroke="#000080" stroke-width=".19"/>
<circle cx="201.6" cy="133.9" r=".37" fill="#000080"/>
<circle cx="201.6" cy="133.9" r=".37" fill="none" stroke="#000080" stroke-width=".17"/>
<circle cx="205.3" cy="133.9" r=".37" fill="#000080"/>
<circle cx="205.3" cy="133.9" r=".37" fill="none" stroke="#000080" stroke-width=".17"/>
<path d="M220.2 107.8h-7.4v26.1h-7.5v-1.9" fill="none" stroke="#000080" stroke-width=".19"/>
<circle cx="212.8" cy="111.5" r=".37" fill="#000080"/>
<circle cx="212.8" cy="111.5" r=".37" fill="none" stroke="#000080" stroke-width=".17"/>
<circle cx="209" cy="133.9" r=".37" fill="#000080"/>
<circle cx="209" cy="133.9" r=".37" fill="none" stroke="#000080" stroke-width=".17"/>
<circle cx="205.3" cy="133.9" r=".37" fill="#000080"/>
<circle cx="205.3" cy="133.9" r=".37" fill="none" stroke="#000080" stroke-width=".17"/>
<path d="M140.1 24v1.8" fill="none" stroke="#000080" stroke-width=".19"/>
<circle cx="140.1" cy="23.9" r=".37" fill="#000080"/>
<circle cx="140.1" cy="23.9" r=".37" fill="none" stroke="#000080" stroke-width=".17"/>
<path d="M140.1 33.3v1.8h14.9v3.8" fill="none" stroke="#000080" stroke-width=".19"/>
<circle cx="140.1" cy="35.1" r=".37" fill="#000080"/>
<circle cx="140.1" cy="35.1" r=".37" fill="none" stroke="#000080" stroke-width=".17"/>
<circle cx="147.5" cy="35.1" r=".37" fill="#000080"/>
<circle cx="147.5" cy="35.1" r=".37" fill="none" stroke="#000080" stroke-width=".17"/>
<path d="M108.4 33.3h1.9" fill="none" stroke="#000080" stroke-width=".19"/>
<circle cx="110.3" cy="33.3" r=".37" fill="#000080"/>
<circle cx="110.3" cy="33.3" r=".37" fill="none" stroke="#000080" stroke-width=".17"/>
<path d="M123.3 24v9.3" fill="none" stroke="#000080" stroke-width=".19"/>
<circle cx="123.3" cy="23.9" r=".37" fill="#000080"/>
<circle cx="123.3" cy="23.9" r=".37" fill="none" stroke="#000080" stroke-width=".17"/>
<path d="M114 24h42.8M121.4 33.3h1.9" fill="none" stroke="#000080" stroke-width=".19"/>
<circle cx="123.3" cy="23.9" r=".37" fill="#000080"/>
<circle cx="123.3" cy="23.9" r=".37" fill="none" stroke="#000080" stroke-width=".17"/>
<circle cx="128.9" cy="23.9" r=".37" fill="#000080"/>
<circle cx="128.9" cy="23.9" r=".37" fill="none" stroke="#000080" stroke-width=".17"/>
<circle cx="140.1" cy="23.9" r=".37" fill="#000080"/>
<circle cx="140.1" cy="23.9" r=".37" fill="none" stroke="#000080" stroke-width=".17"/>
<use href="#words"/>
</svg>
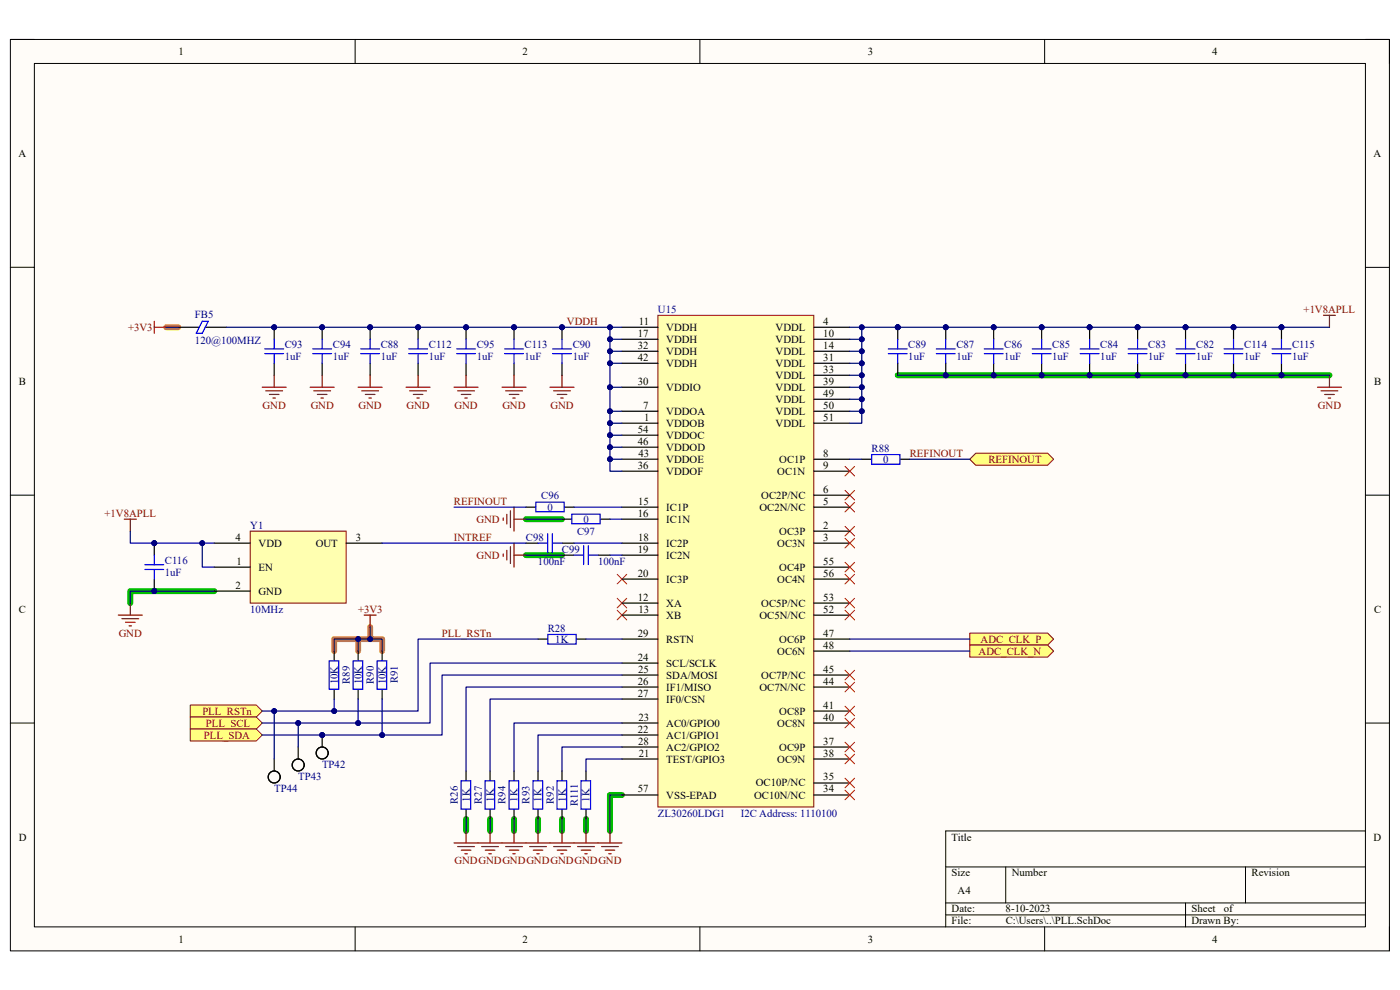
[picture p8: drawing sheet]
<svg xmlns="http://www.w3.org/2000/svg" width="297mm" height="210mm" viewBox="0 0 297 210" stroke-linecap="round" stroke-linejoin="round" font-family="sans-serif">
<defs><g id="words">
<g font-size="2.3">
<text x="37.9" y="11.7">1</text>
<text x="110.9" y="11.7">2</text>
<text x="184.1" y="11.7">3</text>
<text x="257.1" y="11.7">4</text>
<text x="3.9" y="33.3">A</text>
<text x="291.4" y="33.3">A</text>
<text x="135.3" y="71.5">17</text>
<text x="135.5" y="68.9">11</text>
<text x="141.4" y="70.2">VDDH</text>
<text x="164.5" y="70.2">VDDL</text>
<text x="174.7" y="68.9">4</text>
<text x="174.7" y="71.5">10</text>
<text x="135.3" y="74">32</text>
<text x="135.3" y="76.5">42</text>
<text x="141.4" y="72.7">VDDH</text>
<text x="141.4" y="75.3">VDDH</text>
<text x="141.4" y="77.8">VDDH</text>
<text x="164.5" y="72.7">VDDL</text>
<text x="164.5" y="75.3">VDDL</text>
<text x="164.5" y="77.8">VDDL</text>
<text x="174.7" y="74">14</text>
<text x="174.7" y="76.5">31</text>
<text x="4" y="81.6">B</text>
<text x="135.3" y="81.6">30</text>
<text x="141.4" y="82.9">VDDIO</text>
<text x="164.5" y="80.3">VDDL</text>
<text x="164.5" y="82.9">VDDL</text>
<text x="174.7" y="79.1">33</text>
<text x="174.7" y="81.6">39</text>
<text x="291.5" y="81.6">B</text>
<text x="136.5" y="86.7">7</text>
<text x="136.7" y="89.3">1</text>
<text x="141.4" y="88">VDDOA</text>
<text x="164.5" y="85.4">VDDL</text>
<text x="164.5" y="88">VDDL</text>
<text x="174.7" y="84.2">49</text>
<text x="174.7" y="86.7">50</text>
<text x="174.7" y="89.3">51</text>
<text x="135.3" y="91.8">54</text>
<text x="135.3" y="94.4">46</text>
<text x="141.4" y="90.6">VDDOB</text>
<text x="141.4" y="93.1">VDDOC</text>
<text x="141.4" y="95.6">VDDOD</text>
<text x="164.5" y="90.6">VDDL</text>
<text x="135.3" y="99.4">36</text>
<text x="135.4" y="96.9">43</text>
<text x="141.4" y="98.2">VDDOE</text>
<text x="141.4" y="100.7">VDDOF</text>
<text x="164.9" y="100.7">OC1N</text>
<text x="165.3" y="98.2">OC1P</text>
<text x="174.7" y="99.4">9</text>
<text x="174.7" y="96.9">8</text>
<text x="135.4" y="107.1">15</text>
<text x="161.5" y="105.8">OC2P/NC</text>
<text x="174.7" y="104.5">6</text>
<text x="174.7" y="107.1">5</text>
<text x="135.3" y="109.6">16</text>
<text x="141.4" y="110.9">IC1N</text>
<text x="141.4" y="108.3">IC1P</text>
<text x="161.1" y="108.3">OC2N/NC</text>
<text x="165.3" y="113.4">OC3P</text>
<text x="174.7" y="112.1">2</text>
<text x="50" y="114.7">4</text>
<text x="50.2" y="119.8">1</text>
<text x="54.9" y="116">VDD</text>
<text x="67" y="116">OUT</text>
<text x="75.5" y="114.7">3</text>
<text x="135.3" y="117.3">19</text>
<text x="135.4" y="114.7">18</text>
<text x="141.4" y="118.5">IC2N</text>
<text x="141.4" y="116">IC2P</text>
<text x="164.9" y="116">OC3N</text>
<text x="174.7" y="114.7">3</text>
<text x="174.7" y="119.8">55</text>
<text x="50" y="124.9">2</text>
<text x="54.9" y="121.1">EN</text>
<text x="135.3" y="122.3">20</text>
<text x="141.4" y="123.6">IC3P</text>
<text x="164.9" y="123.6">OC4N</text>
<text x="165.3" y="121.1">OC4P</text>
<text x="174.7" y="122.3">56</text>
<text x="4" y="130">C</text>
<text x="54.9" y="126.2">GND</text>
<text x="135.3" y="127.4">12</text>
<text x="135.4" y="130">13</text>
<text x="141.4" y="128.7">XA</text>
<text x="141.4" y="131.2">XB</text>
<text x="161.1" y="131.2">OC5N/NC</text>
<text x="161.5" y="128.7">OC5P/NC</text>
<text x="174.7" y="127.4">53</text>
<text x="174.7" y="130">52</text>
<text x="291.5" y="130">C</text>
<text x="135.3" y="135">29</text>
<text x="141.4" y="136.3">RSTN</text>
<text x="165.3" y="136.3">OC6P</text>
<text x="174.7" y="137.6">48</text>
<text x="174.7" y="135">47</text>
<text x="135.3" y="140.1">24</text>
<text x="135.4" y="142.7">25</text>
<text x="141.4" y="144">SDA/MOSI</text>
<text x="141.4" y="141.4">SCL/SCLK</text>
<text x="161.5" y="144">OC7P/NC</text>
<text x="164.9" y="138.9">OC6N</text>
<text x="174.7" y="142.7">45</text>
<text x="135.3" y="145.2">26</text>
<text x="135.3" y="147.8">27</text>
<text x="141.4" y="146.5">IF1/MISO</text>
<text x="141.4" y="149.1">IF0/CSN</text>
<text x="161.1" y="146.5">OC7N/NC</text>
<text x="174.7" y="145.2">44</text>
<text x="135.3" y="155.4">22</text>
<text x="135.4" y="152.9">23</text>
<text x="141.4" y="154.1">AC0/GPIO0</text>
<text x="164.9" y="154.1">OC8N</text>
<text x="165.3" y="151.6">OC8P</text>
<text x="174.7" y="150.3">41</text>
<text x="174.7" y="152.9">40</text>
<text x="135.4" y="157.9">28</text>
<text x="135.5" y="160.5">21</text>
<text x="141.4" y="159.2">AC2/GPIO2</text>
<text x="141.4" y="156.7">AC1/GPIO1</text>
<text x="141.4" y="161.8">TEST/GPIO3</text>
<text x="164.9" y="161.8">OC9N</text>
<text x="165.3" y="159.2">OC9P</text>
<text x="174.7" y="160.5">38</text>
<text x="174.7" y="157.9">37</text>
<text x="160.4" y="166.8">OC10P/NC</text>
<text x="174.7" y="165.6">35</text>
<text x="135.3" y="168.1">57</text>
<text x="141.4" y="169.4">VSS-EPAD</text>
<text x="160" y="169.4">OC10N/NC</text>
<text x="174.7" y="168.1">34</text>
<text x="4" y="178.3">D</text>
<text x="201.9" y="178.3">Title</text>
<text x="291.4" y="178.3">D</text>
<text x="201.9" y="185.9">Size</text>
<text x="214.6" y="185.9">Number</text>
<text x="265.5" y="185.9">Revision</text>
<text x="203.2" y="189.7">A4</text>
<text x="201.9" y="193.5">Date:</text>
<text x="201.9" y="196.1">File:</text>
<text x="213.3" y="193.5">8-10-2023</text>
<text x="213.4" y="196.1">C:\Users\..\PLL.SchDoc</text>
<text x="252.8" y="196.1">Drawn By:</text>
<text x="252.8" y="193.5">Sheet</text>
<text x="259.6" y="193.5">of</text>
<text x="37.9" y="199.9">1</text>
<text x="110.9" y="199.9">2</text>
<text x="184.1" y="199.9">3</text>
<text x="257.1" y="199.9">4</text>
</g>
<g font-size="2.3" fill="#800000">
<text x="27.2" y="70.2">+3V3</text>
<text x="120.3" y="68.9">VDDH</text>
<text x="276.6" y="66.4">+1V8APLL</text>
<text x="55.7" y="86.7">GND</text>
<text x="65.9" y="86.7">GND</text>
<text x="76.1" y="86.7">GND</text>
<text x="86.2" y="86.7">GND</text>
<text x="96.4" y="86.7">GND</text>
<text x="106.6" y="86.7">GND</text>
<text x="116.8" y="86.7">GND</text>
<text x="279.6" y="86.7">GND</text>
<text x="193" y="96.9">REFINOUT</text>
<text x="209.7" y="98.2">REFINOUT</text>
<text x="96.3" y="107.1">REFINOUT</text>
<text x="22.2" y="109.6">+1V8APLL</text>
<text x="101.1" y="110.9">GND</text>
<text x="96.3" y="114.7">INTREF</text>
<text x="101.1" y="118.5">GND</text>
<text x="76" y="130">+3V3</text>
<text x="25.2" y="135">GND</text>
<text x="93.8" y="135">PLL_RSTn</text>
<text x="208" y="136.3">ADC_CLK_P</text>
<text x="207.6" y="138.9">ADC_CLK_N</text>
<text x="42.9" y="151.6">PLL_RSTn</text>
<text x="43.7" y="154.1">PLL_SCL</text>
<text x="43.3" y="156.7">PLL_SDA</text>
<text x="96.4" y="183.4">GNDGNDGNDGNDGNDGNDGND</text>
</g>
<g font-size="2.3" fill="#000080">
<text x="41.4" y="67.4">FB5</text>
<text x="139.6" y="66.4">U15</text>
<text x="41.4" y="73">120@100MHZ</text>
<text x="60.4" y="73.7">C93</text>
<text x="60.4" y="76.3">1uF</text>
<text x="70.6" y="73.7">C94</text>
<text x="70.6" y="76.3">1uF</text>
<text x="80.8" y="73.7">C88</text>
<text x="80.8" y="76.3">1uF</text>
<text x="91" y="73.7">C112</text>
<text x="91" y="76.3">1uF</text>
<text x="101.1" y="73.7">C95</text>
<text x="101.1" y="76.3">1uF</text>
<text x="111.3" y="73.7">C113</text>
<text x="111.3" y="76.3">1uF</text>
<text x="121.5" y="73.7">C90</text>
<text x="121.5" y="76.3">1uF</text>
<text x="192.7" y="73.7">C89</text>
<text x="192.7" y="76.3">1uF</text>
<text x="202.9" y="73.7">C87</text>
<text x="202.9" y="76.3">1uF</text>
<text x="213.1" y="73.7">C86</text>
<text x="213.1" y="76.3">1uF</text>
<text x="223.2" y="73.7">C85</text>
<text x="223.2" y="76.3">1uF</text>
<text x="233.4" y="73.7">C84</text>
<text x="233.4" y="76.3">1uF</text>
<text x="243.6" y="73.7">C83</text>
<text x="243.6" y="76.3">1uF</text>
<text x="253.8" y="73.7">C82</text>
<text x="253.8" y="76.3">1uF</text>
<text x="263.9" y="73.7">C114</text>
<text x="263.9" y="76.3">1uF</text>
<text x="274.1" y="73.7">C115</text>
<text x="274.1" y="76.3">1uF</text>
<text x="184.9" y="95.9">R88</text>
<text x="187.4" y="98.2">0</text>
<text x="114.8" y="105.8">C96</text>
<text x="53.1" y="112.1">Y1</text>
<text x="116.2" y="108.3">0</text>
<text x="122.4" y="113.4">C97</text>
<text x="123.8" y="110.9">0</text>
<text x="35" y="119.5">C116</text>
<text x="111.6" y="114.7">C98</text>
<text x="114.1" y="119.8">100nF</text>
<text x="119.2" y="117.3">C99</text>
<text x="126.9" y="119.8">100nF</text>
<text x="35" y="122.1">1uF</text>
<text x="53.1" y="130">10MHz</text>
<text x="116.2" y="134.1">R28</text>
<text x="117.8" y="136.3">1K</text>
<text x="71.7" y="145.2" transform="rotate(-90 71.7 145.2)">10K</text>
<text x="74.2" y="145.1" transform="rotate(-90 74.2 145.1)">R89</text>
<text x="76.8" y="145.2" transform="rotate(-90 76.8 145.2)">10K</text>
<text x="79.3" y="145.1" transform="rotate(-90 79.3 145.1)">R90</text>
<text x="81.8" y="145.2" transform="rotate(-90 81.8 145.2)">10K</text>
<text x="84.4" y="145" transform="rotate(-90 84.4 145)">R91</text>
<text x="63.2" y="165.6">TP43</text>
<text x="68.3" y="163">TP42</text>
<text x="58.2" y="168.1">TP44</text>
<text x="97.1" y="170.5" transform="rotate(-90 97.1 170.5)">R26</text>
<text x="99.7" y="170.1" transform="rotate(-90 99.7 170.1)">1K</text>
<text x="102.2" y="170.5" transform="rotate(-90 102.2 170.5)">R27</text>
<text x="104.7" y="170.1" transform="rotate(-90 104.7 170.1)">1K</text>
<text x="107.3" y="170.5" transform="rotate(-90 107.3 170.5)">R94</text>
<text x="109.8" y="170.1" transform="rotate(-90 109.8 170.1)">1K</text>
<text x="112.4" y="170.5" transform="rotate(-90 112.4 170.5)">R93</text>
<text x="114.9" y="170.1" transform="rotate(-90 114.9 170.1)">1K</text>
<text x="117.5" y="170.5" transform="rotate(-90 117.5 170.5)">R92</text>
<text x="120" y="170.1" transform="rotate(-90 120 170.1)">1K</text>
<text x="122.6" y="171" transform="rotate(-90 122.6 171)">R111</text>
<text x="125.1" y="170.1" transform="rotate(-90 125.1 170.1)">1K</text>
<text x="139.6" y="173.2">ZL30260LDG1</text>
<text x="157.2" y="173.2">I2C Address: 1110100</text>
</g>
</g></defs>
<path d="M2.2 8.4h292.6v193.3h-292.6z" fill-rule="evenodd" fill="#fffcf8"/>
<path d="M2.2 8.4h292.6v193.3h-292.6z" fill="none" stroke="#000" stroke-width=".21"/>
<path d="M7.3 13.5h282.4v183.1h-282.4z" fill-rule="evenodd" fill="#fffcf8"/>
<g fill="none" stroke="#000" stroke-width=".21">
<path d="M2.2 8.4h5.1M7.3 13.5h282.4v183.1h-282.4zM75.3 8.4v5.1M148.5 8.4v5.1M221.6 8.4v5.1M289.7 8.4h5.1v5.1M2.2 56.7h5.1M289.7 56.7h5.1M2.2 105h5.1M289.7 105.1h5.1M2.2 153.4h5.1M289.7 153.4h5.1"/>
<path d="M289.7 176.3h-89.1v20.3M75.3 196.6v5.1M148.5 196.6v5.1M200.6 183.9h89.1M200.6 191.5h89.1M200.6 194.1h89.1M213.4 183.9v7.6M221.6 196.6v5.1M251.5 191.5v5.1M264.2 183.9v7.6M294.8 196.6v5.1"/>
</g>
<path d="M35.3 69.4h2.5M76 135.6h-5.1v2.5M78.5 135.6h-2.5v2.5M78.5 133v2.6h2.6v2.5" fill="none" stroke="#f90" stroke-width="1.3"/>
<path d="M190.5 79.6h91.5M111.6 110.1h7.6M111.6 117.8h7.6M45.5 125.4h-17.9v2.5M98.9 173.7v2.6M104 173.7v2.6M109.1 173.7v2.6M114.1 173.7v2.6M119.2 173.7v2.6M124.3 173.7v2.6M132 168.6h-2.6v7.7" fill="none" stroke="#00be00" stroke-width="1.3"/>
<path d="M76 138.1v2M81.1 138.1v2M76 146.3v2M81.1 146.3v2" fill="none" stroke="#000" stroke-width=".25"/>
<path d="M74.9 140.2h2.1v6h-2.1zM80 140.2h2v6h-2z" fill="none" stroke="#00f" stroke-width=".25"/>
<path d="M77.3 130.5h2.5M78.5 130.5v2.5" fill="none" stroke="#800000" stroke-width=".25"/>
<path d="M40.4 149.6h14l1.2 1.2-1.2 1.3h-14z" fill-rule="evenodd" fill="#ffff80"/>
<path d="M40.4 149.6h14l1.2 1.2-1.2 1.3h-14z" fill="none" stroke="#800000" stroke-width=".21"/>
<circle cx="68.3" cy="155.9" r=".51" fill="#000080"/>
<circle cx="68.3" cy="155.9" r=".51" fill="none" stroke="#000080" stroke-width=".21"/>
<path d="M68.3 155.9v2.6" fill="none" stroke="#000" stroke-width=".25"/>
<circle cx="68.3" cy="155.9" r=".51" fill="#000080"/>
<circle cx="68.3" cy="155.9" r=".51" fill="none" stroke="#000080" stroke-width=".21"/>
<circle cx="68.3" cy="159.7" r="1.27" fill="none" stroke="#000" stroke-width=".25"/>
<path d="M121.8 178.8h10.2M122.5 179.6h3.6M124.3 176.3v2.5M127.6 179.6h3.6M129.4 176.3v2.5M123.3 180.4h2M124.1 181.1h.5M128.4 180.4h2M129.1 181.1h.6" fill="none" stroke="#800000" stroke-width=".25"/>
<path d="M40.4 152.1h14l1.2 1.3-1.2 1.3h-14z" fill-rule="evenodd" fill="#ffff80"/>
<path d="M40.4 152.1h14l1.2 1.3-1.2 1.3h-14z" fill="none" stroke="#800000" stroke-width=".21"/>
<path d="M40.4 154.7h14l1.2 1.2-1.2 1.3h-14z" fill-rule="evenodd" fill="#ffff80"/>
<path d="M40.4 154.7h14l1.2 1.2-1.2 1.3h-14z" fill="none" stroke="#800000" stroke-width=".21"/>
<g fill="none" stroke="#000" stroke-width=".25">
<path d="M37.8 69.4h4.5M43.5 69.4h4.5M111.6 107.6h2M119.2 110.1h2M119.8 107.6h2M127.4 110.1h2M70.9 138.1v2M63.3 158.5v2.5M70.9 146.3v2M58.2 161v2.6M109.1 163.6v2M109.1 171.7v2"/>
<path d="M114.1 163.6v2M114.1 171.7v2M119.2 163.6v2M119.2 171.7v2"/>
<circle cx="58.2" cy="164.8" r="1.27"/>
<circle cx="63.3" cy="162.3" r="1.27"/>
</g>
<path d="M42.9 68.2h1.3l-1.3 2.5h-1.3zM113.7 106.5h6v2.1h-6zM121.3 109.1h6v2h-6zM69.8 140.2h2.1v6h-2.1zM108 165.6h2v6.1h-2zM113.1 165.6h2v6.1h-2zM118.2 165.6h2v6.1h-2z" fill="none" stroke="#00f" stroke-width=".25"/>
<path d="M179.3 111.7l2 2M179.3 106.6l2 2M179.3 104l2 2.1M181.3 111.7l-2 2M181.3 106.6l-2 2M181.3 104l-2 2.1M130.9 129.5l2.1 2M130.9 126.9l2.1 2.1M130.9 121.8l2.1 2.1M133 129.5l-2.1 2M133 126.9l-2.1 2.1M133 121.8l-2.1 2.1" fill="none" stroke="#f00" stroke-width=".21"/>
<g fill="none" stroke="#800000" stroke-width=".25">
<path d="M106.8 109.9v.5M107.5 109.1v2.1M108.3 108.4v3.5M109.1 107.6v5.1M109.1 110.1h2.5M106.5 178.8h15.3M107.3 179.6h3.5M109.1 176.3v2.5M112.4 179.6h3.5M114.1 176.3v2.5M117.5 179.6h3.5M119.2 176.3v2.5"/>
<path d="M108 180.4h2.1M108.8 181.1h.5M113.1 180.4h2.1M113.9 181.1h.5M118.2 180.4h2M119 181.1h.5"/>
</g>
<circle cx="58.2" cy="69.4" r=".51" fill="#000080"/>
<circle cx="58.2" cy="69.4" r=".51" fill="none" stroke="#000080" stroke-width=".21"/>
<path d="M58.2 69.4v2.6" fill="none" stroke="#000" stroke-width=".25"/>
<circle cx="58.2" cy="69.4" r=".51" fill="#000080"/>
<circle cx="58.2" cy="69.4" r=".51" fill="none" stroke="#000080" stroke-width=".21"/>
<path d="M58.2 77.1v2.5" fill="none" stroke="#000" stroke-width=".25"/>
<path d="M56.2 74h4M56.2 75h4M58.2 72v2M58.2 75v2.1" fill="none" stroke="#00f" stroke-width=".25"/>
<path d="M58.2 79.6v2.5M55.6 82.1h5.1M56.4 82.9h3.6M57.2 83.7h2M57.9 84.4h.5" fill="none" stroke="#800000" stroke-width=".25"/>
<circle cx="98.9" cy="69.4" r=".51" fill="#000080"/>
<circle cx="98.9" cy="69.4" r=".51" fill="none" stroke="#000080" stroke-width=".21"/>
<path d="M98.9 69.4v2.6" fill="none" stroke="#000" stroke-width=".25"/>
<circle cx="98.9" cy="69.4" r=".51" fill="#000080"/>
<circle cx="98.9" cy="69.4" r=".51" fill="none" stroke="#000080" stroke-width=".21"/>
<path d="M98.9 77.1v2.5" fill="none" stroke="#000" stroke-width=".25"/>
<path d="M96.9 74h4M96.9 75h4M98.9 72v2M98.9 75v2.1" fill="none" stroke="#00f" stroke-width=".25"/>
<path d="M98.9 79.6v2.5M280.8 66.9h2.5M282 66.9v2.5M96.3 82.1h5.1M97.1 82.9h3.6M97.9 83.7h2M98.6 84.4h.5" fill="none" stroke="#800000" stroke-width=".25"/>
<circle cx="251.5" cy="69.4" r=".51" fill="#000080"/>
<circle cx="251.5" cy="69.4" r=".51" fill="none" stroke="#000080" stroke-width=".21"/>
<circle cx="251.5" cy="79.6" r=".51" fill="#000080"/>
<circle cx="251.5" cy="79.6" r=".51" fill="none" stroke="#000080" stroke-width=".21"/>
<path d="M251.5 69.4v2.6" fill="none" stroke="#000" stroke-width=".25"/>
<circle cx="251.5" cy="69.4" r=".51" fill="#000080"/>
<circle cx="251.5" cy="69.4" r=".51" fill="none" stroke="#000080" stroke-width=".21"/>
<path d="M251.5 77.1v2.5" fill="none" stroke="#000" stroke-width=".25"/>
<circle cx="251.5" cy="79.6" r=".51" fill="#000080"/>
<circle cx="251.5" cy="79.6" r=".51" fill="none" stroke="#000080" stroke-width=".21"/>
<path d="M249.5 74h4M249.5 75h4M251.5 72v2M251.5 75v2.1" fill="none" stroke="#00f" stroke-width=".25"/>
<circle cx="241.3" cy="69.4" r=".51" fill="#000080"/>
<circle cx="241.3" cy="69.4" r=".51" fill="none" stroke="#000080" stroke-width=".21"/>
<circle cx="241.3" cy="79.6" r=".51" fill="#000080"/>
<circle cx="241.3" cy="79.6" r=".51" fill="none" stroke="#000080" stroke-width=".21"/>
<path d="M241.3 69.4v2.6" fill="none" stroke="#000" stroke-width=".25"/>
<circle cx="241.3" cy="69.4" r=".51" fill="#000080"/>
<circle cx="241.3" cy="69.4" r=".51" fill="none" stroke="#000080" stroke-width=".21"/>
<path d="M241.3 77.1v2.5" fill="none" stroke="#000" stroke-width=".25"/>
<circle cx="241.3" cy="79.6" r=".51" fill="#000080"/>
<circle cx="241.3" cy="79.6" r=".51" fill="none" stroke="#000080" stroke-width=".21"/>
<path d="M239.3 74h4M239.3 75h4M241.3 72v2M241.3 75v2.1" fill="none" stroke="#00f" stroke-width=".25"/>
<circle cx="231.2" cy="69.4" r=".51" fill="#000080"/>
<circle cx="231.2" cy="69.4" r=".51" fill="none" stroke="#000080" stroke-width=".21"/>
<circle cx="231.2" cy="79.6" r=".51" fill="#000080"/>
<circle cx="231.2" cy="79.6" r=".51" fill="none" stroke="#000080" stroke-width=".21"/>
<path d="M231.2 69.4v2.6" fill="none" stroke="#000" stroke-width=".25"/>
<circle cx="231.2" cy="69.4" r=".51" fill="#000080"/>
<circle cx="231.2" cy="69.4" r=".51" fill="none" stroke="#000080" stroke-width=".21"/>
<path d="M231.2 77.1v2.5" fill="none" stroke="#000" stroke-width=".25"/>
<circle cx="231.2" cy="79.6" r=".51" fill="#000080"/>
<circle cx="231.2" cy="79.6" r=".51" fill="none" stroke="#000080" stroke-width=".21"/>
<path d="M229.2 74h4M229.2 75h4M231.2 72v2M231.2 75v2.1" fill="none" stroke="#00f" stroke-width=".25"/>
<circle cx="221" cy="69.4" r=".51" fill="#000080"/>
<circle cx="221" cy="69.4" r=".51" fill="none" stroke="#000080" stroke-width=".21"/>
<circle cx="221" cy="79.6" r=".51" fill="#000080"/>
<circle cx="221" cy="79.6" r=".51" fill="none" stroke="#000080" stroke-width=".21"/>
<path d="M221 69.4v2.6" fill="none" stroke="#000" stroke-width=".25"/>
<circle cx="221" cy="69.4" r=".51" fill="#000080"/>
<circle cx="221" cy="69.4" r=".51" fill="none" stroke="#000080" stroke-width=".21"/>
<path d="M221 77.1v2.5" fill="none" stroke="#000" stroke-width=".25"/>
<circle cx="221" cy="79.6" r=".51" fill="#000080"/>
<circle cx="221" cy="79.6" r=".51" fill="none" stroke="#000080" stroke-width=".21"/>
<path d="M219 74h4M219 75h4M221 72v2M221 75v2.1" fill="none" stroke="#00f" stroke-width=".25"/>
<path d="M119.2 79.6v2.5M282 79.6v2.5M116.7 82.1h5.1M117.4 82.9h3.6M118.2 83.7h2M119 84.4h.5M279.5 82.1h5.1M280.3 82.9h3.5M281 83.7h2.1M281.8 84.4h.5" fill="none" stroke="#800000" stroke-width=".25"/>
<circle cx="200.6" cy="69.4" r=".51" fill="#000080"/>
<circle cx="200.6" cy="69.4" r=".51" fill="none" stroke="#000080" stroke-width=".21"/>
<circle cx="200.6" cy="79.6" r=".51" fill="#000080"/>
<circle cx="200.6" cy="79.6" r=".51" fill="none" stroke="#000080" stroke-width=".21"/>
<path d="M200.6 69.4v2.6" fill="none" stroke="#000" stroke-width=".25"/>
<circle cx="200.6" cy="69.4" r=".51" fill="#000080"/>
<circle cx="200.6" cy="69.4" r=".51" fill="none" stroke="#000080" stroke-width=".21"/>
<path d="M200.6 77.1v2.5" fill="none" stroke="#000" stroke-width=".25"/>
<circle cx="200.6" cy="79.6" r=".51" fill="#000080"/>
<circle cx="200.6" cy="79.6" r=".51" fill="none" stroke="#000080" stroke-width=".21"/>
<path d="M198.6 74h4M198.6 75h4M200.6 72v2M200.6 75v2.1" fill="none" stroke="#00f" stroke-width=".25"/>
<circle cx="210.8" cy="69.4" r=".51" fill="#000080"/>
<circle cx="210.8" cy="69.4" r=".51" fill="none" stroke="#000080" stroke-width=".21"/>
<circle cx="210.8" cy="79.6" r=".51" fill="#000080"/>
<circle cx="210.8" cy="79.6" r=".51" fill="none" stroke="#000080" stroke-width=".21"/>
<path d="M210.8 69.4v2.6" fill="none" stroke="#000" stroke-width=".25"/>
<circle cx="210.8" cy="69.4" r=".51" fill="#000080"/>
<circle cx="210.8" cy="69.4" r=".51" fill="none" stroke="#000080" stroke-width=".21"/>
<path d="M210.8 77.1v2.5" fill="none" stroke="#000" stroke-width=".25"/>
<circle cx="210.8" cy="79.6" r=".51" fill="#000080"/>
<circle cx="210.8" cy="79.6" r=".51" fill="none" stroke="#000080" stroke-width=".21"/>
<path d="M208.8 74h4M208.8 75h4M210.8 72v2M210.8 75v2.1" fill="none" stroke="#00f" stroke-width=".25"/>
<circle cx="68.3" cy="69.4" r=".51" fill="#000080"/>
<circle cx="68.3" cy="69.4" r=".51" fill="none" stroke="#000080" stroke-width=".21"/>
<path d="M68.3 69.4v2.6" fill="none" stroke="#000" stroke-width=".25"/>
<circle cx="68.3" cy="69.4" r=".51" fill="#000080"/>
<circle cx="68.3" cy="69.4" r=".51" fill="none" stroke="#000080" stroke-width=".21"/>
<path d="M68.3 77.1v2.5" fill="none" stroke="#000" stroke-width=".25"/>
<path d="M66.3 74h4.1M66.3 75h4.1M68.3 72v2M68.3 75v2.1" fill="none" stroke="#00f" stroke-width=".25"/>
<path d="M68.3 79.6v2.5M65.8 82.1h5.1M66.6 82.9h3.5M67.3 83.7h2.1M68.1 84.4h.5" fill="none" stroke="#800000" stroke-width=".25"/>
<path d="M53.1 112.7h20.3v15.2h-20.3z" fill-rule="evenodd" fill="#ffffb0"/>
<path d="M53.1 112.7h20.3v15.2h-20.3z" fill="none" stroke="#800000" stroke-width=".21"/>
<path d="M45.5 115.2h7.6M73.4 115.2h7.7M111.6 115.2h2.5M119.2 115.2h2.6M119.2 117.8h2.6M126.9 117.8h2.5M45.5 125.4h7.6M45.5 120.3h7.6" fill="none" stroke="#000" stroke-width=".25"/>
<path d="M26.4 110.1h2.5M27.6 110.1v2.6M106.8 117.5v.5M107.5 116.7v2.1M108.3 116v3.5M109.1 115.2v5.1M109.1 117.8h2.5M25.1 130.5h5.1M25.9 131.2h3.5M26.6 132h2.1M27.4 132.8h.5M27.6 127.9v2.6" fill="none" stroke="#800000" stroke-width=".25"/>
<path d="M114.1 115.2h2.1M116.2 113.2v4M117.2 115.2h2M117.2 113.2v4M121.8 117.8h2M123.8 115.8v4M124.8 117.8h2.1M124.8 115.8v4" fill="none" stroke="#00f" stroke-width=".25"/>
<circle cx="190.5" cy="69.4" r=".51" fill="#000080"/>
<circle cx="190.5" cy="69.4" r=".51" fill="none" stroke="#000080" stroke-width=".21"/>
<path d="M190.5 69.4v2.6" fill="none" stroke="#000" stroke-width=".25"/>
<circle cx="190.5" cy="69.4" r=".51" fill="#000080"/>
<circle cx="190.5" cy="69.4" r=".51" fill="none" stroke="#000080" stroke-width=".21"/>
<path d="M190.5 77.1v2.5" fill="none" stroke="#000" stroke-width=".25"/>
<path d="M188.5 74h4M188.5 75h4M190.5 72v2M190.5 75v2.1" fill="none" stroke="#00f" stroke-width=".25"/>
<path d="M32.7 68.2v2.5M32.7 69.4h2.6" fill="none" stroke="#800000" stroke-width=".25"/>
<circle cx="78.5" cy="69.4" r=".51" fill="#000080"/>
<circle cx="78.5" cy="69.4" r=".51" fill="none" stroke="#000080" stroke-width=".21"/>
<path d="M78.5 69.4v2.6" fill="none" stroke="#000" stroke-width=".25"/>
<circle cx="78.5" cy="69.4" r=".51" fill="#000080"/>
<circle cx="78.5" cy="69.4" r=".51" fill="none" stroke="#000080" stroke-width=".21"/>
<path d="M78.5 77.1v2.5" fill="none" stroke="#000" stroke-width=".25"/>
<path d="M76.5 74h4M76.5 75h4M78.5 72v2M78.5 75v2.1" fill="none" stroke="#00f" stroke-width=".25"/>
<path d="M78.5 79.6v2.5M76 82.1h5.1M76.7 82.9h3.6M77.5 83.7h2M78.3 84.4h.5" fill="none" stroke="#800000" stroke-width=".25"/>
<path d="M139.6 66.9h33.1v104.3h-33.1z" fill-rule="evenodd" fill="#ffffb0"/>
<path d="M139.6 66.9h33.1v104.3h-33.1z" fill="none" stroke="#800000" stroke-width=".21"/>
<g fill="none" stroke="#000" stroke-width=".25">
<path d="M131.9 69.4h7.7M131.9 72h7.7M131.9 74.5h7.7M131.9 77.1h7.7M172.7 69.4h7.6M172.7 72h7.6M172.7 74.5h7.6M172.7 77.1h7.6M172.7 79.6h7.6M131.9 100h7.7M131.9 97.4h7.7M131.9 82.1h7.7"/>
<path d="M131.9 87.2h7.7M131.9 89.8h7.7M131.9 92.3h7.7M131.9 94.9h7.7M172.7 100h7.6M172.7 97.4h7.6M172.7 82.1h7.6M172.7 84.7h7.6M172.7 87.2h7.6M172.7 89.8h7.6M131.9 117.8h7.7M131.9 115.2h7.7"/>
<path d="M131.9 110.1h7.7M131.9 107.6h7.7M172.7 115.2h7.6M172.7 107.6h7.6M172.7 112.7h7.6M172.7 105.1h7.6M131.9 122.9h7.7M131.9 127.9h7.7M131.9 130.5h7.7M131.9 135.6h7.7M172.7 122.9h7.6M172.7 127.9h7.6"/>
<path d="M172.7 130.5h7.6M172.7 135.6h7.6M172.7 138.1h7.6M172.7 120.3h7.6M131.9 145.7h7.7M131.9 143.2h7.7M131.9 158.5h7.7M131.9 155.9h7.7M131.9 153.4h7.7M131.9 140.7h7.7M131.9 148.3h7.7M172.7 145.8h7.6"/>
<path d="M172.7 143.2h7.6M172.7 158.5h7.6M172.7 153.4h7.6M172.7 150.8h7.6M124.3 163.6v2M124.3 171.7v2M131.9 168.6h7.7M131.9 161h7.7M172.7 168.6h7.6M172.7 161h7.6M172.7 166.1h7.6"/>
</g>
<path d="M123.3 165.6h2v6.1h-2z" fill="none" stroke="#00f" stroke-width=".25"/>
<g fill="none" stroke="#f00" stroke-width=".21">
<path d="M179.3 119.3l2 2M181.3 119.3l-2 2M179.3 121.8l2 2.1M179.3 129.5l2 2M179.3 126.9l2 2.1M181.3 121.8l-2 2.1M181.3 129.5l-2 2M181.3 126.9l-2 2.1M179.3 144.7l2 2.1M179.3 142.2l2 2M179.3 152.4l2 2M179.3 149.8l2 2.1"/>
<path d="M179.3 160l2 2M181.3 144.7l-2 2.1M181.3 142.2l-2 2M181.3 152.4l-2 2M181.3 149.8l-2 2.1M181.3 160l-2 2M179.3 167.6l2 2.1M179.3 165.1l2 2M181.3 167.6l-2 2.1M181.3 165.1l-2 2"/>
</g>
<circle cx="271.9" cy="69.4" r=".51" fill="#000080"/>
<circle cx="271.9" cy="69.4" r=".51" fill="none" stroke="#000080" stroke-width=".21"/>
<circle cx="271.9" cy="79.6" r=".51" fill="#000080"/>
<circle cx="271.9" cy="79.6" r=".51" fill="none" stroke="#000080" stroke-width=".21"/>
<path d="M271.9 69.4v2.6" fill="none" stroke="#000" stroke-width=".25"/>
<circle cx="271.9" cy="69.4" r=".51" fill="#000080"/>
<circle cx="271.9" cy="69.4" r=".51" fill="none" stroke="#000080" stroke-width=".21"/>
<path d="M271.9 77.1v2.5" fill="none" stroke="#000" stroke-width=".25"/>
<circle cx="271.9" cy="79.6" r=".51" fill="#000080"/>
<circle cx="271.9" cy="79.6" r=".51" fill="none" stroke="#000080" stroke-width=".21"/>
<path d="M269.9 74h4M269.9 75h4M271.9 72v2M271.9 75v2.1" fill="none" stroke="#00f" stroke-width=".25"/>
<circle cx="261.7" cy="69.4" r=".51" fill="#000080"/>
<circle cx="261.7" cy="69.4" r=".51" fill="none" stroke="#000080" stroke-width=".21"/>
<circle cx="261.7" cy="79.6" r=".51" fill="#000080"/>
<circle cx="261.7" cy="79.6" r=".51" fill="none" stroke="#000080" stroke-width=".21"/>
<path d="M261.7 69.4v2.6" fill="none" stroke="#000" stroke-width=".25"/>
<circle cx="261.7" cy="69.4" r=".51" fill="#000080"/>
<circle cx="261.7" cy="69.4" r=".51" fill="none" stroke="#000080" stroke-width=".21"/>
<path d="M261.7 77.1v2.5" fill="none" stroke="#000" stroke-width=".25"/>
<circle cx="261.7" cy="79.6" r=".51" fill="#000080"/>
<circle cx="261.7" cy="79.6" r=".51" fill="none" stroke="#000080" stroke-width=".21"/>
<path d="M259.7 74h4M259.7 75h4M261.7 72v2M261.7 75v2.1" fill="none" stroke="#00f" stroke-width=".25"/>
<circle cx="88.7" cy="69.4" r=".51" fill="#000080"/>
<circle cx="88.7" cy="69.4" r=".51" fill="none" stroke="#000080" stroke-width=".21"/>
<path d="M88.7 69.4v2.6" fill="none" stroke="#000" stroke-width=".25"/>
<circle cx="88.7" cy="69.4" r=".51" fill="#000080"/>
<circle cx="88.7" cy="69.4" r=".51" fill="none" stroke="#000080" stroke-width=".21"/>
<path d="M88.7 77.1v2.5" fill="none" stroke="#000" stroke-width=".25"/>
<path d="M86.7 74h4M86.7 75h4M88.7 72v2M88.7 75v2.1" fill="none" stroke="#00f" stroke-width=".25"/>
<path d="M88.7 79.6v2.5M86.2 82.1h5M86.9 82.9h3.6M87.7 83.7h2M88.4 84.4h.6" fill="none" stroke="#800000" stroke-width=".25"/>
<circle cx="109" cy="69.4" r=".51" fill="#000080"/>
<circle cx="109" cy="69.4" r=".51" fill="none" stroke="#000080" stroke-width=".21"/>
<path d="M109.1 69.4v2.6" fill="none" stroke="#000" stroke-width=".25"/>
<circle cx="109" cy="69.4" r=".51" fill="#000080"/>
<circle cx="109" cy="69.4" r=".51" fill="none" stroke="#000080" stroke-width=".21"/>
<path d="M109.1 77.1v2.5" fill="none" stroke="#000" stroke-width=".25"/>
<path d="M107.1 74h4M107.1 75h4M109.1 72v2M109.1 75v2.1" fill="none" stroke="#00f" stroke-width=".25"/>
<path d="M109.1 79.6v2.5M106.5 82.1h5.1M107.3 82.9h3.5M108 83.7h2.1M108.8 84.4h.5" fill="none" stroke="#800000" stroke-width=".25"/>
<circle cx="32.7" cy="115.2" r=".51" fill="#000080"/>
<circle cx="32.7" cy="115.2" r=".51" fill="none" stroke="#000080" stroke-width=".21"/>
<circle cx="32.7" cy="125.4" r=".51" fill="#000080"/>
<circle cx="32.7" cy="125.4" r=".51" fill="none" stroke="#000080" stroke-width=".21"/>
<path d="M32.7 115.2v2.6" fill="none" stroke="#000" stroke-width=".25"/>
<circle cx="32.7" cy="115.2" r=".51" fill="#000080"/>
<circle cx="32.7" cy="115.2" r=".51" fill="none" stroke="#000080" stroke-width=".21"/>
<path d="M32.7 122.9v2.5" fill="none" stroke="#000" stroke-width=".25"/>
<circle cx="32.7" cy="125.4" r=".51" fill="#000080"/>
<circle cx="32.7" cy="125.4" r=".51" fill="none" stroke="#000080" stroke-width=".21"/>
<path d="M30.7 119.8h4M32.7 117.8v2M30.7 120.8h4M32.7 120.8v2.1" fill="none" stroke="#00f" stroke-width=".25"/>
<path d="M205.7 134.3h16.6l1.2 1.3-1.2 1.2h-16.6z" fill-rule="evenodd" fill="#ffff80"/>
<path d="M205.7 134.3h16.6l1.2 1.3-1.2 1.2h-16.6z" fill="none" stroke="#800000" stroke-width=".21"/>
<path d="M205.7 136.8h16.6l1.2 1.3-1.2 1.3h-16.6z" fill-rule="evenodd" fill="#ffff80"/>
<path d="M205.7 136.8h16.6l1.2 1.3-1.2 1.3h-16.6z" fill="none" stroke="#800000" stroke-width=".21"/>
<path d="M179.3 98.9l2 2.1M181.3 98.9l-2 2.1M179.3 114.2l2 2M181.3 114.2l-2 2" fill="none" stroke="#f00" stroke-width=".21"/>
<circle cx="119.2" cy="69.4" r=".51" fill="#000080"/>
<circle cx="119.2" cy="69.4" r=".51" fill="none" stroke="#000080" stroke-width=".21"/>
<path d="M119.2 69.4v2.6" fill="none" stroke="#000" stroke-width=".25"/>
<circle cx="119.2" cy="69.4" r=".51" fill="#000080"/>
<circle cx="119.2" cy="69.4" r=".51" fill="none" stroke="#000080" stroke-width=".21"/>
<path d="M119.2 77.1v2.5M182.8 97.4h2M191 97.4h2" fill="none" stroke="#000" stroke-width=".25"/>
<path d="M117.2 74h4M117.2 75h4M119.2 72v2M119.2 75v2.1M184.9 96.4h6v2.1h-6z" fill="none" stroke="#00f" stroke-width=".25"/>
<path d="M179.3 157.5l2 2M181.3 157.5l-2 2" fill="none" stroke="#f00" stroke-width=".21"/>
<path d="M207 96.1h15.3l1.2 1.3-1.2 1.3h-15.3l-1.3-1.3z" fill-rule="evenodd" fill="#ffff80"/>
<path d="M207 96.1h15.3l1.2 1.3-1.2 1.3h-15.3l-1.3-1.3z" fill="none" stroke="#800000" stroke-width=".21"/>
<path d="M114.1 135.6h2M122.3 135.6h2M98.9 163.6v2M98.9 171.7v2M104 163.6v2M104 171.7v2" fill="none" stroke="#000" stroke-width=".25"/>
<path d="M116.2 134.6h6v2h-6zM97.8 165.6h2.1v6.1h-2.1zM102.9 165.6h2v6.1h-2z" fill="none" stroke="#00f" stroke-width=".25"/>
<path d="M96.3 178.8h10.2M97.1 179.6h3.6M98.9 176.3v2.5M102.2 179.6h3.5M104 176.3v2.5M97.9 180.4h2M98.6 181.1h.5M102.9 180.4h2.1M103.7 181.1h.5" fill="none" stroke="#800000" stroke-width=".25"/>
<path d="M78.5 135.6h-2.5v2.5" fill="none" stroke="#000080" stroke-width=".25"/>
<circle cx="76" cy="135.6" r=".51" fill="#000080"/>
<circle cx="76" cy="135.6" r=".51" fill="none" stroke="#000080" stroke-width=".21"/>
<circle cx="78.5" cy="135.6" r=".51" fill="#000080"/>
<circle cx="78.5" cy="135.6" r=".51" fill="none" stroke="#000080" stroke-width=".21"/>
<path d="M78.5 133v2.6h2.6v2.5" fill="none" stroke="#000080" stroke-width=".25"/>
<circle cx="78.5" cy="135.6" r=".51" fill="#000080"/>
<circle cx="78.5" cy="135.6" r=".51" fill="none" stroke="#000080" stroke-width=".21"/>
<path d="M76 148.3v5.1" fill="none" stroke="#000080" stroke-width=".25"/>
<circle cx="76" cy="153.4" r=".51" fill="#000080"/>
<circle cx="76" cy="153.4" r=".51" fill="none" stroke="#000080" stroke-width=".21"/>
<path d="M81.1 148.3v7.6" fill="none" stroke="#000080" stroke-width=".25"/>
<circle cx="81.1" cy="155.9" r=".51" fill="#000080"/>
<circle cx="81.1" cy="155.9" r=".51" fill="none" stroke="#000080" stroke-width=".21"/>
<path d="M76 135.6h-5.1v2.5" fill="none" stroke="#000080" stroke-width=".25"/>
<circle cx="76" cy="135.6" r=".51" fill="#000080"/>
<circle cx="76" cy="135.6" r=".51" fill="none" stroke="#000080" stroke-width=".21"/>
<path d="M70.9 148.3v2.5" fill="none" stroke="#000080" stroke-width=".25"/>
<circle cx="70.9" cy="150.8" r=".51" fill="#000080"/>
<circle cx="70.9" cy="150.8" r=".51" fill="none" stroke="#000080" stroke-width=".21"/>
<path d="M58.2 150.8v10.2" fill="none" stroke="#000080" stroke-width=".25"/>
<circle cx="58.2" cy="150.8" r=".51" fill="#000080"/>
<circle cx="58.2" cy="150.8" r=".51" fill="none" stroke="#000080" stroke-width=".21"/>
<path d="M27.6 112.7v2.5h17.9M96.3 107.6h15.3M111.6 110.1h7.6M121.8 107.6h10.1M129.4 110.1h2.5M109.1 173.7v2.6M114.1 173.7v2.6M119.2 173.7v2.6" fill="none" stroke="#000080" stroke-width=".25"/>
<circle cx="42.9" cy="115.2" r=".51" fill="#000080"/>
<circle cx="42.9" cy="115.2" r=".51" fill="none" stroke="#000080" stroke-width=".21"/>
<circle cx="32.7" cy="115.2" r=".51" fill="#000080"/>
<circle cx="32.7" cy="115.2" r=".51" fill="none" stroke="#000080" stroke-width=".21"/>
<path d="M42.9 115.2v5.1h2.6M81.1 115.2h30.5M111.6 117.8h7.6M129.4 117.8h2.5" fill="none" stroke="#000080" stroke-width=".25"/>
<circle cx="42.9" cy="115.2" r=".51" fill="#000080"/>
<circle cx="42.9" cy="115.2" r=".51" fill="none" stroke="#000080" stroke-width=".21"/>
<path d="M35.3 69.4h2.5M131.9 158.5h-12.7v5.1M131.9 155.9h-17.8v7.7M131.9 153.4h-22.8v10.2M131.9 143.2h-38.1v12.7h-38.2M124.3 173.7v2.6" fill="none" stroke="#000080" stroke-width=".25"/>
<circle cx="68.3" cy="155.9" r=".51" fill="#000080"/>
<circle cx="68.3" cy="155.9" r=".51" fill="none" stroke="#000080" stroke-width=".21"/>
<circle cx="81.1" cy="155.9" r=".51" fill="#000080"/>
<circle cx="81.1" cy="155.9" r=".51" fill="none" stroke="#000080" stroke-width=".21"/>
<path d="M131.9 140.7h-40.7v12.7h-35.6" fill="none" stroke="#000080" stroke-width=".25"/>
<circle cx="63.3" cy="153.4" r=".51" fill="#000080"/>
<circle cx="63.3" cy="153.4" r=".51" fill="none" stroke="#000080" stroke-width=".21"/>
<circle cx="76" cy="153.4" r=".51" fill="#000080"/>
<circle cx="76" cy="153.4" r=".51" fill="none" stroke="#000080" stroke-width=".21"/>
<path d="M190.5 79.6h91.5" fill="none" stroke="#000080" stroke-width=".25"/>
<circle cx="271.9" cy="79.6" r=".51" fill="#000080"/>
<circle cx="271.9" cy="79.6" r=".51" fill="none" stroke="#000080" stroke-width=".21"/>
<circle cx="261.7" cy="79.6" r=".51" fill="#000080"/>
<circle cx="261.7" cy="79.6" r=".51" fill="none" stroke="#000080" stroke-width=".21"/>
<circle cx="251.5" cy="79.6" r=".51" fill="#000080"/>
<circle cx="251.5" cy="79.6" r=".51" fill="none" stroke="#000080" stroke-width=".21"/>
<circle cx="241.3" cy="79.6" r=".51" fill="#000080"/>
<circle cx="241.3" cy="79.6" r=".51" fill="none" stroke="#000080" stroke-width=".21"/>
<circle cx="231.2" cy="79.6" r=".51" fill="#000080"/>
<circle cx="231.2" cy="79.6" r=".51" fill="none" stroke="#000080" stroke-width=".21"/>
<circle cx="221" cy="79.6" r=".51" fill="#000080"/>
<circle cx="221" cy="79.6" r=".51" fill="none" stroke="#000080" stroke-width=".21"/>
<circle cx="210.8" cy="79.6" r=".51" fill="#000080"/>
<circle cx="210.8" cy="79.6" r=".51" fill="none" stroke="#000080" stroke-width=".21"/>
<circle cx="200.6" cy="79.6" r=".51" fill="#000080"/>
<circle cx="200.6" cy="79.6" r=".51" fill="none" stroke="#000080" stroke-width=".21"/>
<path d="M190.5 69.4h91.5" fill="none" stroke="#000080" stroke-width=".25"/>
<circle cx="271.9" cy="69.4" r=".51" fill="#000080"/>
<circle cx="271.9" cy="69.4" r=".51" fill="none" stroke="#000080" stroke-width=".21"/>
<circle cx="261.7" cy="69.4" r=".51" fill="#000080"/>
<circle cx="261.7" cy="69.4" r=".51" fill="none" stroke="#000080" stroke-width=".21"/>
<circle cx="251.5" cy="69.4" r=".51" fill="#000080"/>
<circle cx="251.5" cy="69.4" r=".51" fill="none" stroke="#000080" stroke-width=".21"/>
<circle cx="241.3" cy="69.4" r=".51" fill="#000080"/>
<circle cx="241.3" cy="69.4" r=".51" fill="none" stroke="#000080" stroke-width=".21"/>
<circle cx="231.2" cy="69.4" r=".51" fill="#000080"/>
<circle cx="231.2" cy="69.4" r=".51" fill="none" stroke="#000080" stroke-width=".21"/>
<circle cx="221" cy="69.4" r=".51" fill="#000080"/>
<circle cx="221" cy="69.4" r=".51" fill="none" stroke="#000080" stroke-width=".21"/>
<circle cx="210.8" cy="69.4" r=".51" fill="#000080"/>
<circle cx="210.8" cy="69.4" r=".51" fill="none" stroke="#000080" stroke-width=".21"/>
<circle cx="200.6" cy="69.4" r=".51" fill="#000080"/>
<circle cx="200.6" cy="69.4" r=".51" fill="none" stroke="#000080" stroke-width=".21"/>
<circle cx="190.5" cy="69.4" r=".51" fill="#000080"/>
<circle cx="190.5" cy="69.4" r=".51" fill="none" stroke="#000080" stroke-width=".21"/>
<path d="M180.3 69.4h10.2" fill="none" stroke="#000080" stroke-width=".25"/>
<circle cx="182.8" cy="69.4" r=".51" fill="#000080"/>
<circle cx="182.8" cy="69.4" r=".51" fill="none" stroke="#000080" stroke-width=".21"/>
<circle cx="190.5" cy="69.4" r=".51" fill="#000080"/>
<circle cx="190.5" cy="69.4" r=".51" fill="none" stroke="#000080" stroke-width=".21"/>
<path d="M182.8 69.4v20.4h-2.5" fill="none" stroke="#000080" stroke-width=".25"/>
<circle cx="182.8" cy="87.2" r=".51" fill="#000080"/>
<circle cx="182.8" cy="87.2" r=".51" fill="none" stroke="#000080" stroke-width=".21"/>
<circle cx="182.8" cy="84.7" r=".51" fill="#000080"/>
<circle cx="182.8" cy="84.7" r=".51" fill="none" stroke="#000080" stroke-width=".21"/>
<circle cx="182.8" cy="82.1" r=".51" fill="#000080"/>
<circle cx="182.8" cy="82.1" r=".51" fill="none" stroke="#000080" stroke-width=".21"/>
<circle cx="182.8" cy="79.6" r=".51" fill="#000080"/>
<circle cx="182.8" cy="79.6" r=".51" fill="none" stroke="#000080" stroke-width=".21"/>
<circle cx="182.8" cy="77.1" r=".51" fill="#000080"/>
<circle cx="182.8" cy="77.1" r=".51" fill="none" stroke="#000080" stroke-width=".21"/>
<circle cx="182.8" cy="74.5" r=".51" fill="#000080"/>
<circle cx="182.8" cy="74.5" r=".51" fill="none" stroke="#000080" stroke-width=".21"/>
<circle cx="182.8" cy="72" r=".51" fill="#000080"/>
<circle cx="182.8" cy="72" r=".51" fill="none" stroke="#000080" stroke-width=".21"/>
<circle cx="182.8" cy="69.4" r=".51" fill="#000080"/>
<circle cx="182.8" cy="69.4" r=".51" fill="none" stroke="#000080" stroke-width=".21"/>
<path d="M180.3 87.2h2.5" fill="none" stroke="#000080" stroke-width=".25"/>
<circle cx="182.8" cy="87.2" r=".51" fill="#000080"/>
<circle cx="182.8" cy="87.2" r=".51" fill="none" stroke="#000080" stroke-width=".21"/>
<path d="M180.3 84.7h2.5" fill="none" stroke="#000080" stroke-width=".25"/>
<circle cx="182.8" cy="84.7" r=".51" fill="#000080"/>
<circle cx="182.8" cy="84.7" r=".51" fill="none" stroke="#000080" stroke-width=".21"/>
<path d="M180.3 82.1h2.5" fill="none" stroke="#000080" stroke-width=".25"/>
<circle cx="182.8" cy="82.1" r=".51" fill="#000080"/>
<circle cx="182.8" cy="82.1" r=".51" fill="none" stroke="#000080" stroke-width=".21"/>
<path d="M180.3 79.6h2.5" fill="none" stroke="#000080" stroke-width=".25"/>
<circle cx="182.8" cy="79.6" r=".51" fill="#000080"/>
<circle cx="182.8" cy="79.6" r=".51" fill="none" stroke="#000080" stroke-width=".21"/>
<path d="M180.3 77.1h2.5" fill="none" stroke="#000080" stroke-width=".25"/>
<circle cx="182.8" cy="77.1" r=".51" fill="#000080"/>
<circle cx="182.8" cy="77.1" r=".51" fill="none" stroke="#000080" stroke-width=".21"/>
<path d="M180.3 74.5h2.5" fill="none" stroke="#000080" stroke-width=".25"/>
<circle cx="182.8" cy="74.5" r=".51" fill="#000080"/>
<circle cx="182.8" cy="74.5" r=".51" fill="none" stroke="#000080" stroke-width=".21"/>
<path d="M180.3 72h2.5" fill="none" stroke="#000080" stroke-width=".25"/>
<circle cx="182.8" cy="72" r=".51" fill="#000080"/>
<circle cx="182.8" cy="72" r=".51" fill="none" stroke="#000080" stroke-width=".21"/>
<path d="M129.4 74.5h2.5" fill="none" stroke="#000080" stroke-width=".25"/>
<circle cx="129.4" cy="74.5" r=".51" fill="#000080"/>
<circle cx="129.4" cy="74.5" r=".51" fill="none" stroke="#000080" stroke-width=".21"/>
<path d="M129.4 72h2.5" fill="none" stroke="#000080" stroke-width=".25"/>
<circle cx="129.4" cy="72" r=".51" fill="#000080"/>
<circle cx="129.4" cy="72" r=".51" fill="none" stroke="#000080" stroke-width=".21"/>
<path d="M129.4 69.4h2.5" fill="none" stroke="#000080" stroke-width=".25"/>
<circle cx="129.4" cy="69.4" r=".51" fill="#000080"/>
<circle cx="129.4" cy="69.4" r=".51" fill="none" stroke="#000080" stroke-width=".21"/>
<path d="M45.5 125.4h-17.9v2.5" fill="none" stroke="#000080" stroke-width=".25"/>
<circle cx="32.7" cy="125.4" r=".51" fill="#000080"/>
<circle cx="32.7" cy="125.4" r=".51" fill="none" stroke="#000080" stroke-width=".21"/>
<path d="M129.4 97.4h2.5M180.3 135.6h25.4M180.3 138.1h25.4" fill="none" stroke="#000080" stroke-width=".25"/>
<circle cx="129.4" cy="97.4" r=".51" fill="#000080"/>
<circle cx="129.4" cy="97.4" r=".51" fill="none" stroke="#000080" stroke-width=".21"/>
<path d="M129.4 92.3h2.5" fill="none" stroke="#000080" stroke-width=".25"/>
<circle cx="129.4" cy="92.3" r=".51" fill="#000080"/>
<circle cx="129.4" cy="92.3" r=".51" fill="none" stroke="#000080" stroke-width=".21"/>
<path d="M129.4 89.8h2.5" fill="none" stroke="#000080" stroke-width=".25"/>
<circle cx="129.4" cy="89.8" r=".51" fill="#000080"/>
<circle cx="129.4" cy="89.8" r=".51" fill="none" stroke="#000080" stroke-width=".21"/>
<path d="M129.4 94.9h2.5" fill="none" stroke="#000080" stroke-width=".25"/>
<circle cx="129.4" cy="94.9" r=".51" fill="#000080"/>
<circle cx="129.4" cy="94.9" r=".51" fill="none" stroke="#000080" stroke-width=".21"/>
<path d="M131.9 87.2h-2.5v12.8h2.5" fill="none" stroke="#000080" stroke-width=".25"/>
<circle cx="129.4" cy="97.4" r=".51" fill="#000080"/>
<circle cx="129.4" cy="97.4" r=".51" fill="none" stroke="#000080" stroke-width=".21"/>
<circle cx="129.4" cy="94.9" r=".51" fill="#000080"/>
<circle cx="129.4" cy="94.9" r=".51" fill="none" stroke="#000080" stroke-width=".21"/>
<circle cx="129.4" cy="92.3" r=".51" fill="#000080"/>
<circle cx="129.4" cy="92.3" r=".51" fill="none" stroke="#000080" stroke-width=".21"/>
<circle cx="129.4" cy="89.8" r=".51" fill="#000080"/>
<circle cx="129.4" cy="89.8" r=".51" fill="none" stroke="#000080" stroke-width=".21"/>
<circle cx="129.4" cy="87.2" r=".51" fill="#000080"/>
<circle cx="129.4" cy="87.2" r=".51" fill="none" stroke="#000080" stroke-width=".21"/>
<path d="M129.4 77.1v5" fill="none" stroke="#000080" stroke-width=".25"/>
<circle cx="129.4" cy="82.1" r=".51" fill="#000080"/>
<circle cx="129.4" cy="82.1" r=".51" fill="none" stroke="#000080" stroke-width=".21"/>
<circle cx="129.4" cy="77.1" r=".51" fill="#000080"/>
<circle cx="129.4" cy="77.1" r=".51" fill="none" stroke="#000080" stroke-width=".21"/>
<path d="M131.9 82.1h-2.5v5.1" fill="none" stroke="#000080" stroke-width=".25"/>
<circle cx="129.4" cy="82.1" r=".51" fill="#000080"/>
<circle cx="129.4" cy="82.1" r=".51" fill="none" stroke="#000080" stroke-width=".21"/>
<circle cx="129.4" cy="87.2" r=".51" fill="#000080"/>
<circle cx="129.4" cy="87.2" r=".51" fill="none" stroke="#000080" stroke-width=".21"/>
<path d="M48 69.4h81.4v7.7h2.5" fill="none" stroke="#000080" stroke-width=".25"/>
<circle cx="58.2" cy="69.4" r=".51" fill="#000080"/>
<circle cx="58.2" cy="69.4" r=".51" fill="none" stroke="#000080" stroke-width=".21"/>
<circle cx="68.3" cy="69.4" r=".51" fill="#000080"/>
<circle cx="68.3" cy="69.4" r=".51" fill="none" stroke="#000080" stroke-width=".21"/>
<circle cx="78.5" cy="69.4" r=".51" fill="#000080"/>
<circle cx="78.5" cy="69.4" r=".51" fill="none" stroke="#000080" stroke-width=".21"/>
<circle cx="88.7" cy="69.4" r=".51" fill="#000080"/>
<circle cx="88.7" cy="69.4" r=".51" fill="none" stroke="#000080" stroke-width=".21"/>
<circle cx="98.9" cy="69.4" r=".51" fill="#000080"/>
<circle cx="98.9" cy="69.4" r=".51" fill="none" stroke="#000080" stroke-width=".21"/>
<circle cx="109" cy="69.4" r=".51" fill="#000080"/>
<circle cx="109" cy="69.4" r=".51" fill="none" stroke="#000080" stroke-width=".21"/>
<circle cx="119.2" cy="69.4" r=".51" fill="#000080"/>
<circle cx="119.2" cy="69.4" r=".51" fill="none" stroke="#000080" stroke-width=".21"/>
<circle cx="129.4" cy="69.4" r=".51" fill="#000080"/>
<circle cx="129.4" cy="69.4" r=".51" fill="none" stroke="#000080" stroke-width=".21"/>
<circle cx="129.4" cy="72" r=".51" fill="#000080"/>
<circle cx="129.4" cy="72" r=".51" fill="none" stroke="#000080" stroke-width=".21"/>
<circle cx="129.4" cy="74.5" r=".51" fill="#000080"/>
<circle cx="129.4" cy="74.5" r=".51" fill="none" stroke="#000080" stroke-width=".21"/>
<circle cx="129.4" cy="77.1" r=".51" fill="#000080"/>
<circle cx="129.4" cy="77.1" r=".51" fill="none" stroke="#000080" stroke-width=".21"/>
<path d="M180.3 97.4h2.5M193 97.4h12.7M63.3 153.4v5.1" fill="none" stroke="#000080" stroke-width=".25"/>
<circle cx="63.3" cy="153.4" r=".51" fill="#000080"/>
<circle cx="63.3" cy="153.4" r=".51" fill="none" stroke="#000080" stroke-width=".21"/>
<path d="M121.8 115.2h10.1M114.1 135.6h-25.4v15.2h-33.1M131.9 148.3h-27.9v15.3M131.9 145.7h-33v17.9M98.9 173.7v2.6M104 173.7v2.6M131.9 161h-7.6v2.6M132 168.6h-2.6v7.7" fill="none" stroke="#000080" stroke-width=".25"/>
<circle cx="58.2" cy="150.8" r=".51" fill="#000080"/>
<circle cx="58.2" cy="150.8" r=".51" fill="none" stroke="#000080" stroke-width=".21"/>
<circle cx="70.9" cy="150.8" r=".51" fill="#000080"/>
<circle cx="70.9" cy="150.8" r=".51" fill="none" stroke="#000080" stroke-width=".21"/>
<path d="M124.3 135.6h7.6" fill="none" stroke="#000080" stroke-width=".25"/>
<use href="#words"/>
</svg>
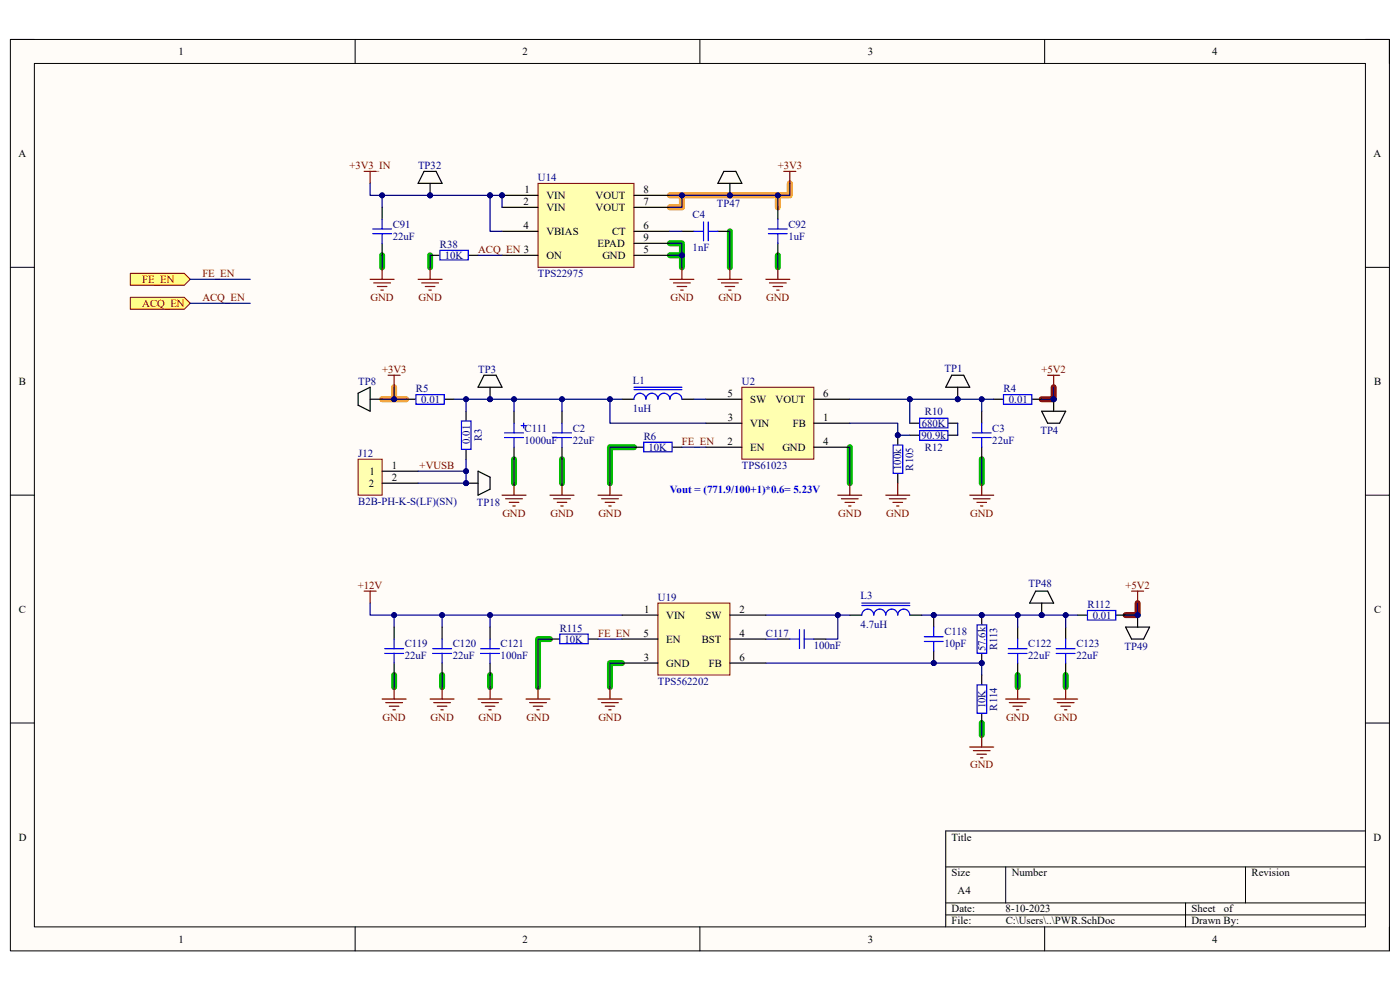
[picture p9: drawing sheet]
<svg xmlns="http://www.w3.org/2000/svg" width="297mm" height="210mm" viewBox="0 0 297 210" stroke-linecap="round" stroke-linejoin="round" font-family="sans-serif">
<defs><g id="words">
<g font-size="2.3">
<text x="37.9" y="11.7">1</text>
<text x="110.9" y="11.7">2</text>
<text x="184.1" y="11.7">3</text>
<text x="257.1" y="11.7">4</text>
<text x="3.9" y="33.3">A</text>
<text x="291.4" y="33.3">A</text>
<text x="111.3" y="40.9">1</text>
<text x="136.5" y="40.9">8</text>
<text x="111" y="43.5">2</text>
<text x="115.9" y="42.2">VIN</text>
<text x="115.9" y="44.7">VIN</text>
<text x="126.4" y="42.2">VOUT</text>
<text x="126.4" y="44.7">VOUT</text>
<text x="136.5" y="43.5">7</text>
<text x="111" y="48.6">4</text>
<text x="115.9" y="49.8">VBIAS</text>
<text x="126.8" y="52.4">EPAD</text>
<text x="129.8" y="49.8">CT</text>
<text x="136.5" y="53.6">5</text>
<text x="136.5" y="48.6">6</text>
<text x="136.5" y="51.1">9</text>
<text x="115.9" y="54.9">ON</text>
<text x="127.8" y="54.9">GND</text>
<text x="4" y="81.6">B</text>
<text x="291.5" y="81.6">B</text>
<text x="154.3" y="84.2">5</text>
<text x="154.4" y="89.3">3</text>
<text x="159.2" y="85.4">SW</text>
<text x="164.5" y="85.4">VOUT</text>
<text x="174.7" y="84.2">6</text>
<text x="174.7" y="89.3">1</text>
<text x="154.3" y="94.4">2</text>
<text x="159.2" y="90.6">VIN</text>
<text x="159.2" y="95.6">EN</text>
<text x="166" y="95.6">GND</text>
<text x="168.2" y="90.6">FB</text>
<text x="174.7" y="94.4">4</text>
<text x="78.4" y="100.7">1</text>
<text x="83.1" y="99.4">1</text>
<text x="83.1" y="102">2</text>
<text x="78.2" y="103.3">2</text>
<text x="4" y="130">C</text>
<text x="136.7" y="130">1</text>
<text x="141.4" y="131.2">VIN</text>
<text x="149.6" y="131.2">SW</text>
<text x="156.9" y="130">2</text>
<text x="291.5" y="130">C</text>
<text x="136.5" y="135">5</text>
<text x="141.4" y="136.3">EN</text>
<text x="148.9" y="136.3">BST</text>
<text x="156.9" y="135">4</text>
<text x="136.6" y="140.1">3</text>
<text x="141.4" y="141.4">GND</text>
<text x="150.4" y="141.4">FB</text>
<text x="156.9" y="140.1">6</text>
<text x="4" y="178.3">D</text>
<text x="201.9" y="178.3">Title</text>
<text x="291.4" y="178.3">D</text>
<text x="201.9" y="185.9">Size</text>
<text x="214.6" y="185.9">Number</text>
<text x="265.5" y="185.9">Revision</text>
<text x="203.2" y="189.7">A4</text>
<text x="201.9" y="193.5">Date:</text>
<text x="201.9" y="196.1">File:</text>
<text x="213.3" y="193.5">8-10-2023</text>
<text x="213.4" y="196.1">C:\Users\..\PWR.SchDoc</text>
<text x="252.8" y="193.5">Sheet</text>
<text x="252.8" y="196.1">Drawn By:</text>
<text x="259.6" y="193.5">of</text>
<text x="37.9" y="199.9">1</text>
<text x="110.9" y="199.9">2</text>
<text x="184.1" y="199.9">3</text>
<text x="257.1" y="199.9">4</text>
</g>
<g font-size="2.3" fill="#800000">
<text x="74.1" y="35.9">+3V3_IN</text>
<text x="165" y="35.9">+3V3</text>
<text x="101.4" y="53.6">ACQ_EN 3</text>
<text x="30.2" y="60">FE_EN</text>
<text x="42.9" y="58.7">FE_EN</text>
<text x="30.2" y="65.1">ACQ_EN</text>
<text x="42.9" y="63.8">ACQ_EN</text>
<text x="78.6" y="63.8">GND</text>
<text x="88.8" y="63.8">GND</text>
<text x="142.2" y="63.8">GND</text>
<text x="152.4" y="63.8">GND</text>
<text x="162.6" y="63.8">GND</text>
<text x="81.1" y="79.1">+3V3</text>
<text x="220.9" y="79.1">+5V2</text>
<text x="144.7" y="94.4">FE_EN</text>
<text x="89" y="99.4">+VUSB</text>
<text x="106.6" y="109.6">GND</text>
<text x="116.8" y="109.6">GND</text>
<text x="127" y="109.6">GND</text>
<text x="177.8" y="109.6">GND</text>
<text x="188" y="109.6">GND</text>
<text x="205.8" y="109.6">GND</text>
<text x="75.9" y="124.9">+12V</text>
<text x="238.8" y="124.9">+5V2</text>
<text x="126.9" y="135">FE_EN</text>
<text x="81.2" y="152.9">GND</text>
<text x="91.4" y="152.9">GND</text>
<text x="101.5" y="152.9">GND</text>
<text x="111.7" y="152.9">GND</text>
<text x="127" y="152.9">GND</text>
<text x="213.4" y="152.9">GND</text>
<text x="223.6" y="152.9">GND</text>
<text x="205.8" y="163">GND</text>
</g>
<g font-size="2.3" fill="#000080">
<text x="88.7" y="35.9">TP32</text>
<text x="114.1" y="38.4">U14</text>
<text x="146.9" y="46.3">C4</text>
<text x="152.1" y="44">TP47</text>
<text x="83.3" y="48.3">C91</text>
<text x="83.3" y="50.8">22uF</text>
<text x="93.3" y="52.6">R38</text>
<text x="146.9" y="53.3">1nF</text>
<text x="167.3" y="48.3">C92</text>
<text x="167.3" y="50.8">1uF</text>
<text x="94.4" y="54.9">10K</text>
<text x="114.1" y="58.7">TPS22975</text>
<text x="76" y="81.6">TP8</text>
<text x="88.2" y="83.2">R5</text>
<text x="101.4" y="79.1">TP3</text>
<text x="134.2" y="81.4">L1</text>
<text x="157.4" y="81.6">U2</text>
<text x="200.4" y="78.8">TP1</text>
<text x="212.9" y="83.2">R4</text>
<text x="89.4" y="85.4">0.01</text>
<text x="134.2" y="87.5">1uH</text>
<text x="196.2" y="88">R10</text>
<text x="214" y="85.4">0.01</text>
<text x="99.7" y="94.2" transform="rotate(-90 99.7 94.2)">0.01</text>
<text x="102.2" y="93.6" transform="rotate(-90 102.2 93.6)">R3</text>
<text x="111.3" y="91.6">C111</text>
<text x="111.3" y="94.1">1000uF</text>
<text x="121.5" y="91.6">C2</text>
<text x="121.5" y="94.1">22uF</text>
<text x="136.6" y="93.3">R6</text>
<text x="137.6" y="95.6">10K</text>
<text x="195.5" y="93.1">90.9k</text>
<text x="195.5" y="90.6">680K</text>
<text x="196.2" y="95.6">R12</text>
<text x="210.5" y="91.6">C3</text>
<text x="210.5" y="94.1">22uF</text>
<text x="220.7" y="92.1">TP4</text>
<text x="76" y="96.9">J12</text>
<text x="157.4" y="99.4">TPS61023</text>
<text x="191.2" y="99.7" transform="rotate(-90 191.2 99.7)">100k</text>
<text x="193.8" y="99.8" transform="rotate(-90 193.8 99.8)">R105</text>
<text x="76" y="107.1">B2B-PH-K-S(LF)(SN)</text>
<text x="101.2" y="107.3">TP18</text>
<text x="218.2" y="124.6">TP48</text>
<text x="139.6" y="127.4">U19</text>
<text x="182.6" y="127.2">L3</text>
<text x="230.7" y="129">R112</text>
<text x="231.8" y="131.2">0.01</text>
<text x="85.9" y="137.3">C119</text>
<text x="96.1" y="137.3">C120</text>
<text x="106.2" y="137.3">C121</text>
<text x="118.7" y="134">R115</text>
<text x="119.8" y="136.3">10K</text>
<text x="162.5" y="135">C117</text>
<text x="172.6" y="137.6">100nF</text>
<text x="182.6" y="133.3">4.7uH</text>
<text x="200.4" y="134.8">C118</text>
<text x="200.4" y="137.3">10pF</text>
<text x="211.6" y="138" transform="rotate(-90 211.6 138)">R113</text>
<text x="218.1" y="137.3">C122</text>
<text x="228.3" y="137.3">C123</text>
<text x="238.5" y="137.8">TP49</text>
<text x="85.9" y="139.9">22uF</text>
<text x="96.1" y="139.9">22uF</text>
<text x="106.2" y="139.9">100nF</text>
<text x="209" y="138.2" transform="rotate(-90 209 138.2)">57.6k</text>
<text x="218.1" y="139.9">22uF</text>
<text x="228.3" y="139.9">22uF</text>
<text x="139.6" y="145.2">TPS562202</text>
<text x="209" y="150.3" transform="rotate(-90 209 150.3)">10K</text>
<text x="211.6" y="150.7" transform="rotate(-90 211.6 150.7)">R114</text>
</g>
<text font-size="2.3" fill="#00f" x="142.1" y="104.5">Vout = (771.9/100+1)*0.6= 5.23V</text>
</g></defs>
<path d="M2.2 8.4h292.6v193.3h-292.6z" fill-rule="evenodd" fill="#fffcf8"/>
<path d="M2.2 8.4h292.6v193.3h-292.6z" fill="none" stroke="#000" stroke-width=".21"/>
<path d="M7.3 13.5h282.4v183.1h-282.4z" fill-rule="evenodd" fill="#fffcf8"/>
<g fill="none" stroke="#000" stroke-width=".21">
<path d="M2.2 8.4h5.1M7.3 13.5h282.4v183.1h-282.4zM75.3 8.4v5.1M148.5 8.4v5.1M221.6 8.4v5.1M289.7 8.4h5.1v5.1M2.2 56.7h5.1M289.7 56.7h5.1M2.2 105h5.1M289.7 105.1h5.1M2.2 153.4h5.1M289.7 153.4h5.1"/>
<path d="M289.7 176.3h-89.1v20.3M75.3 196.6v5.1M148.5 196.6v5.1M200.6 183.9h89.1M200.6 191.5h89.1M200.6 194.1h89.1M213.4 183.9v7.6M221.6 196.6v5.1M251.5 191.5v5.1M264.2 183.9v7.6M294.8 196.6v5.1"/>
</g>
<g fill="none" stroke="#00be00" stroke-width="1.3">
<path d="M81.1 54.2v2.5M91.2 54.2v2.5M142.1 54.2h2.6v2.5M142.1 51.6h2.6v2.6M154.8 49.1v7.6M165 54.2v2.5M109.1 97.4v5.1M119.2 97.4v5.1M134.5 94.9h-5.1v7.6M180.3 94.9v7.6M208.3 97.4v5.1M116.7 135.6h-2.6v10.1"/>
<path d="M83.6 143.2v2.5M93.8 143.2v2.5M104 143.2v2.5M131.9 140.7h-2.5v5M208.3 153.4v2.5M215.9 143.2v2.6M226.1 143.2v2.6"/>
</g>
<path d="M223.5 82.1v2.6h-2.5M241.3 127.9v2.6h-2.5" fill="none" stroke="#800000" stroke-width="1.3"/>
<path d="M167.6 38.9v2.5h-22.9v2.6h-2.6M142.1 41.4h2.6M165 41.4v2.6M81.1 84.7h5.1M83.6 82.1v2.6" fill="none" stroke="#f90" stroke-width="1.3"/>
<path d="M119.2 87.2v2.6M119.2 94.9v2.5M208.3 87.2v2.6M208.3 94.9v2.5M210.8 84.7h2M219 84.7h2" fill="none" stroke="#000" stroke-width=".25"/>
<path d="M117.2 92.8h4M117.2 91.8h4M119.2 89.8v2M119.2 92.8v2.1M206.3 92.8h4M206.3 91.8h4M208.3 89.8v2M208.3 92.8v2.1M212.9 83.7h6v2.1h-6z" fill="none" stroke="#00f" stroke-width=".25"/>
<path d="M222.3 79.6h2.5M223.5 79.6v2.5M116.7 105h5.1M117.4 105.8h3.6M118.2 106.6h2M119 107.3h.5M119.2 102.5v2.5M205.7 105.1h5.1M206.5 105.8h3.5M207.3 106.6h2M208 107.3h.5M208.3 102.5v2.6" fill="none" stroke="#800000" stroke-width=".25"/>
<circle cx="203.2" cy="84.7" r=".51" fill="#000080"/>
<circle cx="203.2" cy="84.7" r=".51" fill="none" stroke="#000080" stroke-width=".21"/>
<path d="M203.2 82.1v2.6" fill="none" stroke="#000" stroke-width=".25"/>
<circle cx="203.2" cy="84.7" r=".51" fill="#000080"/>
<circle cx="203.2" cy="84.7" r=".51" fill="none" stroke="#000080" stroke-width=".21"/>
<path d="M201.9 79.6h2.5l1.3 2.5h-5.1z" fill="none" stroke="#000" stroke-width=".25"/>
<circle cx="223.5" cy="84.7" r=".51" fill="#000080"/>
<circle cx="223.5" cy="84.7" r=".51" fill="none" stroke="#000080" stroke-width=".21"/>
<path d="M223.5 84.7v2.5" fill="none" stroke="#000" stroke-width=".25"/>
<circle cx="223.5" cy="84.7" r=".51" fill="#000080"/>
<circle cx="223.5" cy="84.7" r=".51" fill="none" stroke="#000080" stroke-width=".21"/>
<path d="M221 87.2h5.1l-1.3 2.6h-2.5z" fill="none" stroke="#000" stroke-width=".25"/>
<path d="M157.4 82.1h15.3v15.3h-15.3z" fill-rule="evenodd" fill="#ffffb0"/>
<path d="M157.4 82.1h15.3v15.3h-15.3z" fill="none" stroke="#800000" stroke-width=".21"/>
<path d="M98.9 87.2v2M98.9 95.4v2M131.9 84.7h2.6M144.7 84.7h2.5M149.8 89.8h7.6M149.8 84.7h7.6M149.8 94.9h7.6M172.7 89.8h7.6M172.7 84.7h7.6M172.7 94.9h7.6" fill="none" stroke="#000" stroke-width=".25"/>
<path d="M177.7 105.1h5.1M178.5 105.8h3.6M179.3 106.6h2M180 107.3h.5M180.3 102.5v2.6" fill="none" stroke="#800000" stroke-width=".25"/>
<path d="M97.9 89.3h2v6h-2zM134.5 84.7a1.27 1.27 0 0 1 1.3-1.3 1.27 1.27 0 0 1 1.2 1.3 1.27 1.27 0 0 1 1.3-1.3 1.27 1.27 0 0 1 1.3 1.3 1.27 1.27 0 0 1 1.3-1.3 1.27 1.27 0 0 1 1.2 1.3 1.27 1.27 0 0 1 1.3-1.3 1.27 1.27 0 0 1 1.3 1.3M134.5 82.7h10.2M134.5 82.1h10.2" fill="none" stroke="#00f" stroke-width=".25"/>
<circle cx="104" cy="84.7" r=".51" fill="#000080"/>
<circle cx="104" cy="84.7" r=".51" fill="none" stroke="#000080" stroke-width=".21"/>
<path d="M104 82.1v2.6" fill="none" stroke="#000" stroke-width=".25"/>
<circle cx="104" cy="84.7" r=".51" fill="#000080"/>
<circle cx="104" cy="84.7" r=".51" fill="none" stroke="#000080" stroke-width=".21"/>
<path d="M102.7 79.6h2.5l1.3 2.5h-5.1zM76 83.4l2.5-1.3v5.1l-2.5-1.2zM78.5 84.7h2.6M86.2 84.7h2M94.3 84.7h2M134.5 94.9h2M142.7 94.9h2" fill="none" stroke="#000" stroke-width=".25"/>
<path d="M82.3 79.6h2.6M83.6 79.6v2.5M126.9 105h5M127.6 105.8h3.6M128.4 106.6h2M129.1 107.3h.6M129.4 102.5v2.5" fill="none" stroke="#800000" stroke-width=".25"/>
<path d="M88.2 83.7h6v2.1h-6zM136.6 93.8h6v2h-6z" fill="none" stroke="#00f" stroke-width=".25"/>
<circle cx="106.5" cy="41.4" r=".51" fill="#000080"/>
<circle cx="106.5" cy="41.4" r=".51" fill="none" stroke="#000080" stroke-width=".21"/>
<path d="M114.1 38.9h20.4v17.8h-20.4z" fill-rule="evenodd" fill="#ffffb0"/>
<path d="M114.1 38.9h20.4v17.8h-20.4z" fill="none" stroke="#800000" stroke-width=".21"/>
<path d="M106.5 41.4h7.6M106.5 54.2h7.6M134.5 41.4h7.6M134.5 44h7.6M134.5 54.2h7.6" fill="none" stroke="#000" stroke-width=".25"/>
<circle cx="106.5" cy="41.4" r=".51" fill="#000080"/>
<circle cx="106.5" cy="41.4" r=".51" fill="none" stroke="#000080" stroke-width=".21"/>
<path d="M81.1 44v2.5M81.1 51.6v2.6M106.5 44h7.6M106.5 49.1h7.6M134.5 49.1h7.6M134.5 51.6h7.6M165 44v2.5M165 51.6v2.6" fill="none" stroke="#000" stroke-width=".25"/>
<path d="M77.3 36.4h2.5M78.5 36.4v2.5M78.5 59.3h5.1M81.1 56.7v2.6M162.5 59.3h5.1M165 56.7v2.6M79.3 60h3.5M80 60.8h2.1M80.8 61.5h.5M163.2 60h3.6M164 60.8h2M164.8 61.5h.5" fill="none" stroke="#800000" stroke-width=".25"/>
<path d="M79.1 49.6h4M79.1 48.6h4M81.1 46.5v2.1M81.1 49.6v2M163 49.6h4M163 48.6h4M165 46.5v2.1M165 49.6v2" fill="none" stroke="#00f" stroke-width=".25"/>
<circle cx="190.5" cy="92.3" r=".51" fill="#000080"/>
<circle cx="190.5" cy="92.3" r=".51" fill="none" stroke="#000080" stroke-width=".21"/>
<path d="M190.5 92.3v2" fill="none" stroke="#000" stroke-width=".25"/>
<circle cx="190.5" cy="92.3" r=".51" fill="#000080"/>
<circle cx="190.5" cy="92.3" r=".51" fill="none" stroke="#000080" stroke-width=".21"/>
<path d="M91.2 54.2h2M99.4 54.2h2M144.7 49.1h2.5M152.3 49.1h2.5M109.1 87.2v2.6M109.1 94.9v2.5M193 92.3h2M193 89.8h2M201.2 92.3h2M201.2 89.8h2M190.5 100.5v2" fill="none" stroke="#000" stroke-width=".25"/>
<g fill="none" stroke="#00f" stroke-width=".25">
<path d="M93.3 53.1h6v2h-6zM147.2 49.1h2.1M149.3 47.1v4M150.3 49.1h2M150.3 47.1v4M107.1 92.8h4M107.1 91.8h4M109.1 89.8v2M109.1 92.8v2.1M110.6 90.3h1M111.1 89.8v1M189.5 94.4h2v6h-2z"/>
<path d="M195.1 91.3h6v2.1h-6zM195.1 88.7h6v2.1h-6z"/>
</g>
<g fill="none" stroke="#800000" stroke-width=".25">
<path d="M166.3 36.4h2.5M167.6 36.4v2.5M88.7 59.3h5.1M91.2 56.7v2.6M142.1 59.3h5.1M144.7 56.7v2.6M152.3 59.3h5.1M154.8 56.7v2.6M89.5 60h3.5M90.2 60.8h2.1M91 61.5h.5M142.9 60h3.5"/>
<path d="M143.6 60.8h2.1M144.4 61.5h.5M153.1 60h3.5M153.8 60.8h2.1M154.6 61.5h.5M106.5 105h5.1M107.3 105.8h3.5M108 106.6h2.1M108.8 107.3h.5M109.1 102.5v2.5M187.9 105.1h5.1M188.7 105.8h3.5"/>
<path d="M189.4 106.6h2.1M190.2 107.3h.5M190.5 102.5v2.6"/>
</g>
<path d="M76 97.4h5.1v7.6h-5.1z" fill-rule="evenodd" fill="#ffffb0"/>
<path d="M76 97.4h5.1v7.6h-5.1z" fill="none" stroke="#800000" stroke-width=".21"/>
<path d="M81.1 100h7.6M81.1 102.5h7.6" fill="none" stroke="#000" stroke-width=".25"/>
<circle cx="98.9" cy="102.5" r=".51" fill="#000080"/>
<circle cx="98.9" cy="102.5" r=".51" fill="none" stroke="#000080" stroke-width=".21"/>
<path d="M98.9 102.5h2.5" fill="none" stroke="#000" stroke-width=".25"/>
<circle cx="98.9" cy="102.5" r=".51" fill="#000080"/>
<circle cx="98.9" cy="102.5" r=".51" fill="none" stroke="#000080" stroke-width=".21"/>
<path d="M101.4 100l2.6 1.2v2.6l-2.6 1.2z" fill="none" stroke="#000" stroke-width=".25"/>
<circle cx="91.2" cy="41.4" r=".51" fill="#000080"/>
<circle cx="91.2" cy="41.4" r=".51" fill="none" stroke="#000080" stroke-width=".21"/>
<path d="M91.2 38.9v2.5" fill="none" stroke="#000" stroke-width=".25"/>
<circle cx="91.2" cy="41.4" r=".51" fill="#000080"/>
<circle cx="91.2" cy="41.4" r=".51" fill="none" stroke="#000080" stroke-width=".21"/>
<path d="M90 36.4h2.5l1.3 2.5h-5.1z" fill="none" stroke="#000" stroke-width=".25"/>
<circle cx="154.8" cy="41.4" r=".51" fill="#000080"/>
<circle cx="154.8" cy="41.4" r=".51" fill="none" stroke="#000080" stroke-width=".21"/>
<path d="M154.8 38.9v2.5" fill="none" stroke="#000" stroke-width=".25"/>
<circle cx="154.8" cy="41.4" r=".51" fill="#000080"/>
<circle cx="154.8" cy="41.4" r=".51" fill="none" stroke="#000080" stroke-width=".21"/>
<path d="M153.6 36.4h2.5l1.3 2.5h-5.1z" fill="none" stroke="#000" stroke-width=".25"/>
<path d="M139.6 127.9h15.2v15.3h-15.2z" fill-rule="evenodd" fill="#ffffb0"/>
<path d="M139.6 127.9h15.2v15.3h-15.2z" fill="none" stroke="#800000" stroke-width=".21"/>
<path d="M104 133v2.6M131.9 130.5h7.7M131.9 135.6h7.7M154.8 130.5h7.7M154.8 135.6h7.7M165 135.6h2.6M172.7 135.6h2.5M104 140.7v2.5M131.9 140.7h7.7M154.8 140.7h7.7M208.3 143.2v2M208.3 151.4v2" fill="none" stroke="#000" stroke-width=".25"/>
<path d="M102 137.6h4M102 138.6h4M104 135.6v2M104 138.6v2.1M167.6 135.6h2M169.6 133.6v4M170.6 135.6h2.1M170.6 133.6v4M207.3 145.3h2v6h-2z" fill="none" stroke="#00f" stroke-width=".25"/>
<g fill="none" stroke="#800000" stroke-width=".25">
<path d="M101.4 148.3h5.1M102.2 149.1h3.5M102.9 149.8h2.1M103.7 150.6h.5M104 145.7v2.6M126.9 148.3h5M127.6 149.1h3.6M128.4 149.8h2M129.1 150.6h.6M129.4 145.7v2.6M205.7 158.5h5.1M206.5 159.2h3.5"/>
<path d="M207.3 160h2M208.3 155.9v2.6M208 160.8h.5"/>
</g>
<circle cx="198.1" cy="140.7" r=".51" fill="#000080"/>
<circle cx="198.1" cy="140.7" r=".51" fill="none" stroke="#000080" stroke-width=".21"/>
<circle cx="198.1" cy="130.5" r=".51" fill="#000080"/>
<circle cx="198.1" cy="130.5" r=".51" fill="none" stroke="#000080" stroke-width=".21"/>
<path d="M198.1 138.1v2.6" fill="none" stroke="#000" stroke-width=".25"/>
<circle cx="198.1" cy="140.7" r=".51" fill="#000080"/>
<circle cx="198.1" cy="140.7" r=".51" fill="none" stroke="#000080" stroke-width=".21"/>
<path d="M198.1 130.5v2.5" fill="none" stroke="#000" stroke-width=".25"/>
<circle cx="198.1" cy="130.5" r=".51" fill="#000080"/>
<circle cx="198.1" cy="130.5" r=".51" fill="none" stroke="#000080" stroke-width=".21"/>
<g fill="none" stroke="#00f" stroke-width=".25">
<path d="M81.6 138.6h4M81.6 137.6h4M83.6 135.6v2M83.6 138.6v2.1M91.8 138.6h4M91.8 137.6h4M93.8 135.6v2M93.8 138.6v2.1M196.1 136.1h4M196.1 135.1h4M198.1 133v2.1M198.1 136.1v2"/>
<path d="M213.9 138.6h4M213.9 137.6h4M215.9 135.6v2M215.9 138.6v2.1M224.1 138.6h4M224.1 137.6h4M226.1 135.6v2M226.1 138.6v2.1"/>
</g>
<path d="M83.6 133v2.6M93.8 133v2.6M215.9 133v2.6M226.1 133v2.6M83.6 140.7v2.5M93.8 140.7v2.5M215.9 140.7v2.5M226.1 140.7v2.5" fill="none" stroke="#000" stroke-width=".25"/>
<g fill="none" stroke="#800000" stroke-width=".25">
<path d="M77.3 125.4h2.5M78.5 125.4v2.5M240.1 125.4h2.5M241.3 125.4v2.5M81.1 148.3h5.1M81.8 149.1h3.6M82.6 149.8h2M83.4 150.6h.5M83.6 145.7v2.6M91.2 148.3h5.1M92 149.1h3.6M92.8 149.8h2"/>
<path d="M93.5 150.6h.5M93.8 145.7v2.6M213.4 148.3h5.1M214.1 149.1h3.6M214.9 149.8h2M215.6 150.6h.6M215.9 145.8v2.5M223.5 148.3h5.1M224.3 149.1h3.6M225.1 149.8h2M225.8 150.6h.5M226.1 145.8v2.5"/>
</g>
<circle cx="208.3" cy="130.5" r=".51" fill="#000080"/>
<circle cx="208.3" cy="130.5" r=".51" fill="none" stroke="#000080" stroke-width=".21"/>
<circle cx="208.3" cy="140.7" r=".51" fill="#000080"/>
<circle cx="208.3" cy="140.7" r=".51" fill="none" stroke="#000080" stroke-width=".21"/>
<path d="M208.3 130.5v2" fill="none" stroke="#000" stroke-width=".25"/>
<circle cx="208.3" cy="130.5" r=".51" fill="#000080"/>
<circle cx="208.3" cy="130.5" r=".51" fill="none" stroke="#000080" stroke-width=".21"/>
<path d="M208.3 138.7v2" fill="none" stroke="#000" stroke-width=".25"/>
<circle cx="208.3" cy="140.7" r=".51" fill="#000080"/>
<circle cx="208.3" cy="140.7" r=".51" fill="none" stroke="#000080" stroke-width=".21"/>
<path d="M182.8 130.5a1.28 1.28 0 0 1 1.3-1.3 1.28 1.28 0 0 1 1.3 1.3 1.27 1.27 0 0 1 1.2-1.3 1.27 1.27 0 0 1 1.3 1.3 1.27 1.27 0 0 1 1.3-1.3 1.27 1.27 0 0 1 1.3 1.3 1.28 1.28 0 0 1 1.2-1.3 1.28 1.28 0 0 1 1.3 1.3M182.8 128.4h10.2M182.8 127.9h10.2M207.3 132.6h2v6h-2zM230.7 129.5h6v2h-6z" fill="none" stroke="#00f" stroke-width=".25"/>
<path d="M180.3 130.5h2.5M193 130.5h2.5M228.6 130.5h2M236.8 130.5h2" fill="none" stroke="#000" stroke-width=".25"/>
<circle cx="221" cy="130.5" r=".51" fill="#000080"/>
<circle cx="221" cy="130.5" r=".51" fill="none" stroke="#000080" stroke-width=".21"/>
<path d="M221 127.9v2.6" fill="none" stroke="#000" stroke-width=".25"/>
<circle cx="221" cy="130.5" r=".51" fill="#000080"/>
<circle cx="221" cy="130.5" r=".51" fill="none" stroke="#000080" stroke-width=".21"/>
<path d="M219.7 125.4h2.6l1.2 2.5h-5z" fill="none" stroke="#000" stroke-width=".25"/>
<circle cx="241.3" cy="130.5" r=".51" fill="#000080"/>
<circle cx="241.3" cy="130.5" r=".51" fill="none" stroke="#000080" stroke-width=".21"/>
<path d="M241.3 130.5v2.5" fill="none" stroke="#000" stroke-width=".25"/>
<circle cx="241.3" cy="130.5" r=".51" fill="#000080"/>
<circle cx="241.3" cy="130.5" r=".51" fill="none" stroke="#000080" stroke-width=".21"/>
<path d="M116.7 135.6h2M124.9 135.6h2M238.8 133h5.1l-1.3 2.6h-2.5z" fill="none" stroke="#000" stroke-width=".25"/>
<path d="M118.8 134.5h6v2.1h-6z" fill="none" stroke="#00f" stroke-width=".25"/>
<path d="M111.6 148.3h5.1M112.4 149.1h3.5M113.1 149.8h2.1M113.9 150.6h.5M114.1 145.7v2.6" fill="none" stroke="#800000" stroke-width=".25"/>
<path d="M119.2 97.4v5.1M208.3 97.4v5.1M223.5 82.1v2.6h-2.5" fill="none" stroke="#000080" stroke-width=".25"/>
<circle cx="223.5" cy="84.7" r=".51" fill="#000080"/>
<circle cx="223.5" cy="84.7" r=".51" fill="none" stroke="#000080" stroke-width=".21"/>
<path d="M129.4 84.7h2.5M144.7 94.9h5.1" fill="none" stroke="#000080" stroke-width=".25"/>
<circle cx="129.4" cy="84.7" r=".51" fill="#000080"/>
<circle cx="129.4" cy="84.7" r=".51" fill="none" stroke="#000080" stroke-width=".21"/>
<path d="M142.1 54.2h2.6v2.5M134.5 94.9h-5.1v7.6M147.2 84.7h2.6M180.3 94.9v7.6" fill="none" stroke="#000080" stroke-width=".25"/>
<circle cx="144.7" cy="54.2" r=".51" fill="#000080"/>
<circle cx="144.7" cy="54.2" r=".51" fill="none" stroke="#000080" stroke-width=".21"/>
<path d="M104 41.4v7.7h2.5" fill="none" stroke="#000080" stroke-width=".25"/>
<circle cx="104" cy="41.4" r=".51" fill="#000080"/>
<circle cx="104" cy="41.4" r=".51" fill="none" stroke="#000080" stroke-width=".21"/>
<path d="M142.1 49.1h2.6M154.8 49.1v7.6M165 41.4v2.6M165 54.2v2.5" fill="none" stroke="#000080" stroke-width=".25"/>
<circle cx="165" cy="41.4" r=".51" fill="#000080"/>
<circle cx="165" cy="41.4" r=".51" fill="none" stroke="#000080" stroke-width=".21"/>
<path d="M142.1 41.4h2.6" fill="none" stroke="#000080" stroke-width=".25"/>
<circle cx="144.7" cy="41.4" r=".51" fill="#000080"/>
<circle cx="144.7" cy="41.4" r=".51" fill="none" stroke="#000080" stroke-width=".21"/>
<path d="M81.1 41.4v2.6M81.1 54.2v2.5" fill="none" stroke="#000080" stroke-width=".25"/>
<circle cx="81.1" cy="41.4" r=".51" fill="#000080"/>
<circle cx="81.1" cy="41.4" r=".51" fill="none" stroke="#000080" stroke-width=".21"/>
<path d="M104 41.4h2.5v2.6" fill="none" stroke="#000080" stroke-width=".25"/>
<circle cx="104" cy="41.4" r=".51" fill="#000080"/>
<circle cx="104" cy="41.4" r=".51" fill="none" stroke="#000080" stroke-width=".21"/>
<circle cx="106.5" cy="41.4" r=".51" fill="#000080"/>
<circle cx="106.5" cy="41.4" r=".51" fill="none" stroke="#000080" stroke-width=".21"/>
<path d="M91.2 54.2v2.5M101.4 54.2h5.1M83.6 82.1v2.6" fill="none" stroke="#000080" stroke-width=".25"/>
<circle cx="83.6" cy="84.7" r=".51" fill="#000080"/>
<circle cx="83.6" cy="84.7" r=".51" fill="none" stroke="#000080" stroke-width=".21"/>
<path d="M98.9 84.7v2.5" fill="none" stroke="#000080" stroke-width=".25"/>
<circle cx="98.9" cy="84.7" r=".51" fill="#000080"/>
<circle cx="98.9" cy="84.7" r=".51" fill="none" stroke="#000080" stroke-width=".21"/>
<path d="M98.9 97.4v2.6h-10.2" fill="none" stroke="#000080" stroke-width=".25"/>
<circle cx="98.9" cy="100" r=".51" fill="#000080"/>
<circle cx="98.9" cy="100" r=".51" fill="none" stroke="#000080" stroke-width=".21"/>
<path d="M119.2 84.7v2.5" fill="none" stroke="#000080" stroke-width=".25"/>
<circle cx="119.2" cy="84.7" r=".51" fill="#000080"/>
<circle cx="119.2" cy="84.7" r=".51" fill="none" stroke="#000080" stroke-width=".21"/>
<path d="M109.1 84.7v2.5M109.1 97.4v5.1" fill="none" stroke="#000080" stroke-width=".25"/>
<circle cx="109" cy="84.7" r=".51" fill="#000080"/>
<circle cx="109" cy="84.7" r=".51" fill="none" stroke="#000080" stroke-width=".21"/>
<path d="M208.3 84.7v2.5" fill="none" stroke="#000080" stroke-width=".25"/>
<circle cx="208.3" cy="84.7" r=".51" fill="#000080"/>
<circle cx="208.3" cy="84.7" r=".51" fill="none" stroke="#000080" stroke-width=".21"/>
<path d="M193 84.7v5.1M203.2 89.8v2.5" fill="none" stroke="#000080" stroke-width=".25"/>
<circle cx="193" cy="84.7" r=".51" fill="#000080"/>
<circle cx="193" cy="84.7" r=".51" fill="none" stroke="#000080" stroke-width=".21"/>
<path d="M180.3 84.7h12.7" fill="none" stroke="#000080" stroke-width=".25"/>
<circle cx="193" cy="84.7" r=".51" fill="#000080"/>
<circle cx="193" cy="84.7" r=".51" fill="none" stroke="#000080" stroke-width=".21"/>
<path d="M180.3 89.8h10.2v2.5h2.5" fill="none" stroke="#000080" stroke-width=".25"/>
<circle cx="190.5" cy="92.3" r=".51" fill="#000080"/>
<circle cx="190.5" cy="92.3" r=".51" fill="none" stroke="#000080" stroke-width=".21"/>
<path d="M98.9 100v2.5h-10.2" fill="none" stroke="#000080" stroke-width=".25"/>
<circle cx="98.9" cy="102.5" r=".51" fill="#000080"/>
<circle cx="98.9" cy="102.5" r=".51" fill="none" stroke="#000080" stroke-width=".21"/>
<circle cx="98.9" cy="100" r=".51" fill="#000080"/>
<circle cx="98.9" cy="100" r=".51" fill="none" stroke="#000080" stroke-width=".21"/>
<path d="M142.1 51.6h2.6v2.6" fill="none" stroke="#000080" stroke-width=".25"/>
<circle cx="144.7" cy="54.2" r=".51" fill="#000080"/>
<circle cx="144.7" cy="54.2" r=".51" fill="none" stroke="#000080" stroke-width=".21"/>
<path d="M81.1 84.7h5.1" fill="none" stroke="#000080" stroke-width=".25"/>
<circle cx="83.6" cy="84.7" r=".51" fill="#000080"/>
<circle cx="83.6" cy="84.7" r=".51" fill="none" stroke="#000080" stroke-width=".21"/>
<path d="M96.3 84.7h33.1v5.1h20.4" fill="none" stroke="#000080" stroke-width=".25"/>
<circle cx="98.9" cy="84.7" r=".51" fill="#000080"/>
<circle cx="98.9" cy="84.7" r=".51" fill="none" stroke="#000080" stroke-width=".21"/>
<circle cx="104" cy="84.7" r=".51" fill="#000080"/>
<circle cx="104" cy="84.7" r=".51" fill="none" stroke="#000080" stroke-width=".21"/>
<circle cx="109" cy="84.7" r=".51" fill="#000080"/>
<circle cx="109" cy="84.7" r=".51" fill="none" stroke="#000080" stroke-width=".21"/>
<circle cx="119.2" cy="84.7" r=".51" fill="#000080"/>
<circle cx="119.2" cy="84.7" r=".51" fill="none" stroke="#000080" stroke-width=".21"/>
<circle cx="129.4" cy="84.7" r=".51" fill="#000080"/>
<circle cx="129.4" cy="84.7" r=".51" fill="none" stroke="#000080" stroke-width=".21"/>
<path d="M193 84.7h17.8" fill="none" stroke="#000080" stroke-width=".25"/>
<circle cx="208.3" cy="84.7" r=".51" fill="#000080"/>
<circle cx="208.3" cy="84.7" r=".51" fill="none" stroke="#000080" stroke-width=".21"/>
<circle cx="203.2" cy="84.7" r=".51" fill="#000080"/>
<circle cx="203.2" cy="84.7" r=".51" fill="none" stroke="#000080" stroke-width=".21"/>
<circle cx="193" cy="84.7" r=".51" fill="#000080"/>
<circle cx="193" cy="84.7" r=".51" fill="none" stroke="#000080" stroke-width=".21"/>
<path d="M162.5 130.5h15.2v5.1h-2.5M162.5 135.6h2.5" fill="none" stroke="#000080" stroke-width=".25"/>
<circle cx="177.7" cy="130.5" r=".51" fill="#000080"/>
<circle cx="177.7" cy="130.5" r=".51" fill="none" stroke="#000080" stroke-width=".21"/>
<path d="M162.5 140.7h45.8v2.5M208.3 153.4v2.5" fill="none" stroke="#000080" stroke-width=".25"/>
<circle cx="208.3" cy="140.7" r=".51" fill="#000080"/>
<circle cx="208.3" cy="140.7" r=".51" fill="none" stroke="#000080" stroke-width=".21"/>
<circle cx="198.1" cy="140.7" r=".51" fill="#000080"/>
<circle cx="198.1" cy="140.7" r=".51" fill="none" stroke="#000080" stroke-width=".21"/>
<path d="M177.7 130.5h2.6M83.6 143.2v2.5M93.8 143.2v2.5M104 143.2v2.5M131.9 140.7h-2.5v5M215.9 143.2v2.6M226.1 143.2v2.6" fill="none" stroke="#000080" stroke-width=".25"/>
<circle cx="177.7" cy="130.5" r=".51" fill="#000080"/>
<circle cx="177.7" cy="130.5" r=".51" fill="none" stroke="#000080" stroke-width=".21"/>
<path d="M241.3 127.9v2.6h-2.5" fill="none" stroke="#000080" stroke-width=".25"/>
<circle cx="241.3" cy="130.5" r=".51" fill="#000080"/>
<circle cx="241.3" cy="130.5" r=".51" fill="none" stroke="#000080" stroke-width=".21"/>
<path d="M104 130.5v2.5" fill="none" stroke="#000080" stroke-width=".25"/>
<circle cx="104" cy="130.5" r=".51" fill="#000080"/>
<circle cx="104" cy="130.5" r=".51" fill="none" stroke="#000080" stroke-width=".21"/>
<path d="M93.8 130.5v2.5" fill="none" stroke="#000080" stroke-width=".25"/>
<circle cx="93.8" cy="130.5" r=".51" fill="#000080"/>
<circle cx="93.8" cy="130.5" r=".51" fill="none" stroke="#000080" stroke-width=".21"/>
<path d="M83.6 130.5v2.5" fill="none" stroke="#000080" stroke-width=".25"/>
<circle cx="83.6" cy="130.5" r=".51" fill="#000080"/>
<circle cx="83.6" cy="130.5" r=".51" fill="none" stroke="#000080" stroke-width=".21"/>
<path d="M215.9 130.5v2.5" fill="none" stroke="#000080" stroke-width=".25"/>
<circle cx="215.9" cy="130.5" r=".51" fill="#000080"/>
<circle cx="215.9" cy="130.5" r=".51" fill="none" stroke="#000080" stroke-width=".21"/>
<path d="M226.1 130.5v2.5" fill="none" stroke="#000080" stroke-width=".25"/>
<circle cx="226.1" cy="130.5" r=".51" fill="#000080"/>
<circle cx="226.1" cy="130.5" r=".51" fill="none" stroke="#000080" stroke-width=".21"/>
<path d="M78.5 127.9v2.6h53.4M126.9 135.6h5" fill="none" stroke="#000080" stroke-width=".25"/>
<circle cx="104" cy="130.5" r=".51" fill="#000080"/>
<circle cx="104" cy="130.5" r=".51" fill="none" stroke="#000080" stroke-width=".21"/>
<circle cx="93.8" cy="130.5" r=".51" fill="#000080"/>
<circle cx="93.8" cy="130.5" r=".51" fill="none" stroke="#000080" stroke-width=".21"/>
<circle cx="83.6" cy="130.5" r=".51" fill="#000080"/>
<circle cx="83.6" cy="130.5" r=".51" fill="none" stroke="#000080" stroke-width=".21"/>
<path d="M195.5 130.5h33.1" fill="none" stroke="#000080" stroke-width=".25"/>
<circle cx="198.1" cy="130.5" r=".51" fill="#000080"/>
<circle cx="198.1" cy="130.5" r=".51" fill="none" stroke="#000080" stroke-width=".21"/>
<circle cx="208.3" cy="130.5" r=".51" fill="#000080"/>
<circle cx="208.3" cy="130.5" r=".51" fill="none" stroke="#000080" stroke-width=".21"/>
<circle cx="215.9" cy="130.5" r=".51" fill="#000080"/>
<circle cx="215.9" cy="130.5" r=".51" fill="none" stroke="#000080" stroke-width=".21"/>
<circle cx="221" cy="130.5" r=".51" fill="#000080"/>
<circle cx="221" cy="130.5" r=".51" fill="none" stroke="#000080" stroke-width=".21"/>
<circle cx="226.1" cy="130.5" r=".51" fill="#000080"/>
<circle cx="226.1" cy="130.5" r=".51" fill="none" stroke="#000080" stroke-width=".21"/>
<path d="M78.5 38.9v2.5h25.5M116.7 135.6h-2.6v10.1" fill="none" stroke="#000080" stroke-width=".25"/>
<circle cx="81.1" cy="41.4" r=".51" fill="#000080"/>
<circle cx="81.1" cy="41.4" r=".51" fill="none" stroke="#000080" stroke-width=".21"/>
<circle cx="91.2" cy="41.4" r=".51" fill="#000080"/>
<circle cx="91.2" cy="41.4" r=".51" fill="none" stroke="#000080" stroke-width=".21"/>
<circle cx="104" cy="41.4" r=".51" fill="#000080"/>
<circle cx="104" cy="41.4" r=".51" fill="none" stroke="#000080" stroke-width=".21"/>
<path d="M167.6 38.9v2.5h-22.9v2.6h-2.6" fill="none" stroke="#000080" stroke-width=".25"/>
<circle cx="165" cy="41.4" r=".51" fill="#000080"/>
<circle cx="165" cy="41.4" r=".51" fill="none" stroke="#000080" stroke-width=".21"/>
<circle cx="154.8" cy="41.4" r=".51" fill="#000080"/>
<circle cx="154.8" cy="41.4" r=".51" fill="none" stroke="#000080" stroke-width=".21"/>
<circle cx="144.7" cy="41.4" r=".51" fill="#000080"/>
<circle cx="144.7" cy="41.4" r=".51" fill="none" stroke="#000080" stroke-width=".21"/>
<path d="M27.6 58h11.5l1.3 1.3-1.3 1.2h-11.5z" fill-rule="evenodd" fill="#ffff80"/>
<path d="M27.6 58h11.5l1.3 1.3-1.3 1.2h-11.5z" fill="none" stroke="#800000" stroke-width=".21"/>
<path d="M27.6 63.1h11.5l1.3 1.2-1.3 1.3h-11.5z" fill-rule="evenodd" fill="#ffff80"/>
<path d="M27.6 63.1h11.5l1.3 1.2-1.3 1.3h-11.5z" fill="none" stroke="#800000" stroke-width=".21"/>
<path d="M40.4 59.3h12.7M40.4 64.3h12.7" fill="none" stroke="#000080" stroke-width=".25"/>
<use href="#words"/>
</svg>
